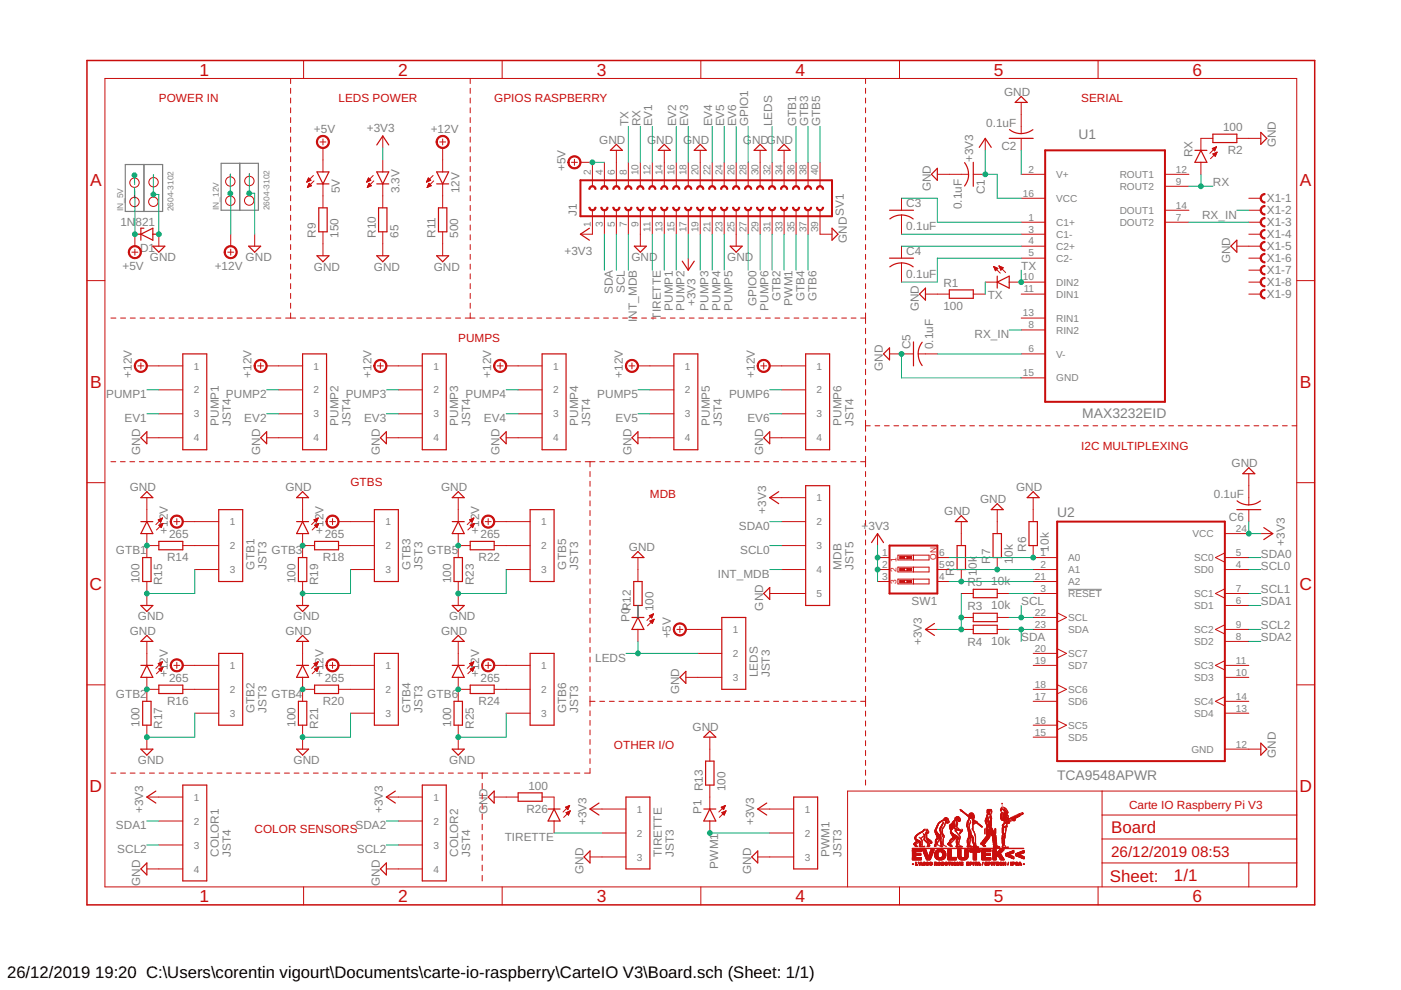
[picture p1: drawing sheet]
<svg xmlns="http://www.w3.org/2000/svg" width="297mm" height="210mm" viewBox="0 0 297 210" stroke-linecap="round" stroke-linejoin="round" font-family="sans-serif">
<defs><g id="words">
<g font-size="3.7" fill="#c90d0c">
<text x="42.3" y="16">1</text>
<text x="84.4" y="16">2</text>
<text x="126.5" y="16">3</text>
<text x="168.6" y="16">4</text>
<text x="210.7" y="16">5</text>
<text x="252.9" y="16">6</text>
<text x="19.1" y="39.4">A</text>
<text x="275.6" y="39.4">A</text>
<text x="19.1" y="82.2">B</text>
<text x="275.6" y="82.2">B</text>
<text x="19" y="125.1">C</text>
<text x="275.5" y="125.1">C</text>
<text x="19" y="167.9">D</text>
<text x="275.5" y="167.9">D</text>
<text x="42.3" y="191.2">1</text>
<text x="84.4" y="191.2">2</text>
<text x="126.5" y="191.2">3</text>
<text x="168.6" y="191.2">4</text>
<text x="210.7" y="191.2">5</text>
<text x="252.9" y="191.2">6</text>
</g>
<g font-size="3.6" fill="#c90d0c">
<text x="235.6" y="176.6">Board</text>
<text x="235.3" y="186.9">Sheet:</text>
<text x="248.9" y="186.8">1/1</text>
</g>
<g font-size="3.5">
<text x="1.5" y="207.4">26/12/2019</text>
<text x="20.2" y="207.4">19:20 C:\Users\corentin vigourt\Documents\carte-io-raspberry\CarteIO V3\Board.sch (Sheet: 1/1)</text>
</g>
<g font-size="3.2" fill="#c90d0c">
<text x="235.6" y="181.7">26/12/2019</text>
<text x="252.6" y="181.7">08:53</text>
</g>
<g font-size="2.9" fill="#808080">
<text x="228.6" y="29.5">U1</text>
<text x="229.5" y="88.6">MAX3232EID</text>
<text x="224.1" y="109.6">U2</text>
<text x="224.1" y="165.4">TCA9548APWR</text>
</g>
<g font-size="2.5" fill="#c90d0c">
<text x="33.7" y="21.7">POWER IN</text>
<text x="71.8" y="21.7">LEDS POWER</text>
<text x="104.8" y="21.7">GPIOS RASPBERRY</text>
<text x="229.2" y="21.7">SERIAL</text>
<text x="97.2" y="72.5">PUMPS</text>
<text x="229.2" y="95.4">I2C MULTIPLEXING</text>
<text x="74.3" y="103">GTBS</text>
<text x="137.8" y="105.5">MDB</text>
<text x="130.2" y="158.8">OTHER I/O</text>
<text x="239.4" y="171.5">Carte IO Raspberry Pi V3</text>
<text x="54" y="176.6">COLOR SENSORS</text>
</g>
<g font-size="2.5" fill="#808080">
<text x="212.9" y="20.3">GND</text>
<text x="66.6" y="28.2">+5V</text>
<text x="77.8" y="28.1">+3V3</text>
<text x="91.3" y="28.2">+12V</text>
<text x="133.2" y="26.8" transform="rotate(-90 133.2 26.8)">TX</text>
<text x="135.8" y="26.8" transform="rotate(-90 135.8 26.8)">RX</text>
<text x="138.3" y="26.8" transform="rotate(-90 138.3 26.8)">EV1</text>
<text x="143.4" y="26.8" transform="rotate(-90 143.4 26.8)">EV2</text>
<text x="145.9" y="26.8" transform="rotate(-90 145.9 26.8)">EV3</text>
<text x="151" y="26.8" transform="rotate(-90 151 26.8)">EV4</text>
<text x="153.5" y="26.8" transform="rotate(-90 153.5 26.8)">EV5</text>
<text x="156.1" y="26.8" transform="rotate(-90 156.1 26.8)">EV6</text>
<text x="158.6" y="26.8" transform="rotate(-90 158.6 26.8)">GPIO1</text>
<text x="163.7" y="26.8" transform="rotate(-90 163.7 26.8)">LEDS</text>
<text x="168.8" y="26.8" transform="rotate(-90 168.8 26.8)">GTB1</text>
<text x="171.3" y="26.8" transform="rotate(-90 171.3 26.8)">GTB3</text>
<text x="173.9" y="26.8" transform="rotate(-90 173.9 26.8)">GTB5</text>
<text x="209.1" y="26.9">0.1uF</text>
<text x="259.3" y="27.8">100</text>
<text x="127" y="30.5">GND</text>
<text x="137.2" y="30.5">GND</text>
<text x="144.8" y="30.5">GND</text>
<text x="157.5" y="30.5">GNDGND</text>
<text x="206.4" y="34.4" transform="rotate(-90 206.4 34.4)">+3V3</text>
<text x="212.3" y="31.7">C2</text>
<text x="252.8" y="33.3" transform="rotate(-90 252.8 33.3)">RX</text>
<text x="260.3" y="32.6">R2</text>
<text x="270.5" y="31.2" transform="rotate(-90 270.5 31.2)">GND</text>
<text x="72" y="41" transform="rotate(-90 72 41)">5V</text>
<text x="84.7" y="41" transform="rotate(-90 84.7 41)">3.3V</text>
<text x="97.4" y="41" transform="rotate(-90 97.4 41)">12V</text>
<text x="119.9" y="36.3" transform="rotate(-90 119.9 36.3)">+5V</text>
<text x="197.3" y="40.6" transform="rotate(-90 197.3 40.6)">GND</text>
<text x="208.8" y="41.2" transform="rotate(-90 208.8 41.2)">C1</text>
<text x="257.2" y="39.5">RX</text>
<text x="122.3" y="45.8" transform="rotate(-90 122.3 45.8)">J1</text>
<text x="178.9" y="45.8" transform="rotate(-90 178.9 45.8)">SV1</text>
<text x="192.1" y="43.9">C3</text>
<text x="204" y="44.4" transform="rotate(-90 204 44.4)">0.1uF</text>
<text x="254.9" y="46.4">RX_IN</text>
<text x="268.6" y="42.8">X1-1</text>
<text x="268.6" y="45.3">X1-2</text>
<text x="268.6" y="47.9">X1-3</text>
<text x="25.5" y="48">1N</text>
<text x="28.7" y="48">821</text>
<text x="29.7" y="53.3">D1</text>
<text x="67" y="50.4" transform="rotate(-90 67 50.4)">R9</text>
<text x="71.8" y="50.4" transform="rotate(-90 71.8 50.4)">150</text>
<text x="79.7" y="50.4" transform="rotate(-90 79.7 50.4)">R10</text>
<text x="84.5" y="50.4" transform="rotate(-90 84.5 50.4)">65</text>
<text x="92.4" y="50.4" transform="rotate(-90 92.4 50.4)">R11</text>
<text x="97.2" y="50.4" transform="rotate(-90 97.2 50.4)">500</text>
<text x="119.7" y="54">+3V3</text>
<text x="179.6" y="51.6" transform="rotate(-90 179.6 51.6)">GND</text>
<text x="192.1" y="48.8">0.1uF</text>
<text x="268.6" y="50.4">X1-4</text>
<text x="268.6" y="53">X1-5</text>
<text x="26" y="57.1">+5V</text>
<text x="31.8" y="55.4">GND</text>
<text x="45.5" y="57.1">+12V</text>
<text x="52.1" y="55.4">GND</text>
<text x="66.6" y="57.4">GND</text>
<text x="79.3" y="57.4">GND</text>
<text x="92" y="57.4">GND</text>
<text x="133.9" y="55.4">GND</text>
<text x="154.2" y="55.4">GND</text>
<text x="192.1" y="58.9">0.1uF</text>
<text x="192.1" y="54.1">C4</text>
<text x="216.5" y="57.3">TX</text>
<text x="260.8" y="55.8" transform="rotate(-90 260.8 55.8)">GND</text>
<text x="268.6" y="55.5">X1-6</text>
<text x="268.6" y="58">X1-7</text>
<text x="129.9" y="62.4" transform="rotate(-90 129.9 62.4)">SDA</text>
<text x="132.5" y="62.1" transform="rotate(-90 132.5 62.1)">SCL</text>
<text x="142.6" y="65.9" transform="rotate(-90 142.6 65.9)">PUMP1</text>
<text x="145.2" y="65.9" transform="rotate(-90 145.2 65.9)">PUMP2</text>
<text x="147.4" y="64.9" transform="rotate(-90 147.4 64.9)">+3V3</text>
<text x="150.2" y="65.9" transform="rotate(-90 150.2 65.9)">PUMP3</text>
<text x="152.8" y="65.9" transform="rotate(-90 152.8 65.9)">PUMP4</text>
<text x="155.3" y="65.9" transform="rotate(-90 155.3 65.9)">PUMP5</text>
<text x="160.4" y="64.9" transform="rotate(-90 160.4 64.9)">GPIO0</text>
<text x="162.9" y="65.9" transform="rotate(-90 162.9 65.9)">PUMP6</text>
<text x="165.5" y="63.8" transform="rotate(-90 165.5 63.8)">GTB2</text>
<text x="168" y="64.8" transform="rotate(-90 168 64.8)">PWM1</text>
<text x="170.6" y="63.8" transform="rotate(-90 170.6 63.8)">GTB4</text>
<text x="173.1" y="63.8" transform="rotate(-90 173.1 63.8)">GTB6</text>
<text x="194.8" y="66" transform="rotate(-90 194.8 66)">GND</text>
<text x="200" y="65.6">100</text>
<text x="200" y="60.8">R1</text>
<text x="209.4" y="63.4">TX</text>
<text x="268.6" y="60.6">X1-8</text>
<text x="268.6" y="63.1">X1-9</text>
<text x="135" y="68.3" transform="rotate(-90 135 68.3)">INT_MDB</text>
<text x="140.1" y="67.7" transform="rotate(-90 140.1 67.7)">TIRETTE</text>
<text x="206.6" y="71.7">RX_IN</text>
<text x="193" y="74" transform="rotate(-90 193 74)">C5</text>
<text x="197.9" y="74" transform="rotate(-90 197.9 74)">0.1uF</text>
<text x="28" y="80.1" transform="rotate(-90 28 80.1)">+12V</text>
<text x="53.4" y="80.1" transform="rotate(-90 53.4 80.1)">+12V</text>
<text x="78.8" y="80.1" transform="rotate(-90 78.8 80.1)">+12V</text>
<text x="104.1" y="80.1" transform="rotate(-90 104.1 80.1)">+12V</text>
<text x="132.1" y="80.1" transform="rotate(-90 132.1 80.1)">+12V</text>
<text x="160" y="80.1" transform="rotate(-90 160 80.1)">+12V</text>
<text x="187.2" y="78.7" transform="rotate(-90 187.2 78.7)">GND</text>
<text x="22.5" y="84.4">PUMP1</text>
<text x="26.4" y="89.5">EV1</text>
<text x="47.9" y="84.4">PUMP2</text>
<text x="51.8" y="89.5">EV2</text>
<text x="73.3" y="84.4">PUMP3</text>
<text x="77.2" y="89.5">EV3</text>
<text x="98.7" y="84.4">PUMP4</text>
<text x="102.6" y="89.5">EV4</text>
<text x="126.6" y="84.4">PUMP5</text>
<text x="130.5" y="89.5">EV5</text>
<text x="154.6" y="84.4">PUMP6</text>
<text x="158.4" y="89.5">EV6</text>
<text x="46.4" y="90.3" transform="rotate(-90 46.4 90.3)">PUMP1</text>
<text x="48.9" y="90.3" transform="rotate(-90 48.9 90.3)">JST4</text>
<text x="71.8" y="90.3" transform="rotate(-90 71.8 90.3)">PUMP2</text>
<text x="74.3" y="90.3" transform="rotate(-90 74.3 90.3)">JST4</text>
<text x="97.2" y="90.3" transform="rotate(-90 97.2 90.3)">PUMP3</text>
<text x="99.7" y="90.3" transform="rotate(-90 99.7 90.3)">JST4</text>
<text x="122.6" y="90.3" transform="rotate(-90 122.6 90.3)">PUMP4</text>
<text x="125.1" y="90.3" transform="rotate(-90 125.1 90.3)">JST4</text>
<text x="150.5" y="90.3" transform="rotate(-90 150.5 90.3)">PUMP5</text>
<text x="153" y="90.3" transform="rotate(-90 153 90.3)">JST4</text>
<text x="178.4" y="90.3" transform="rotate(-90 178.4 90.3)">PUMP6</text>
<text x="181" y="90.3" transform="rotate(-90 181 90.3)">JST4</text>
<text x="29.7" y="96.5" transform="rotate(-90 29.7 96.5)">GND</text>
<text x="55.1" y="96.5" transform="rotate(-90 55.1 96.5)">GND</text>
<text x="80.5" y="96.5" transform="rotate(-90 80.5 96.5)">GND</text>
<text x="105.9" y="96.5" transform="rotate(-90 105.9 96.5)">GND</text>
<text x="133.9" y="96.5" transform="rotate(-90 133.9 96.5)">GND</text>
<text x="161.8" y="96.5" transform="rotate(-90 161.8 96.5)">GND</text>
<text x="261.1" y="99">GND</text>
<text x="27.5" y="104.1">GND</text>
<text x="60.5" y="104.1">GND</text>
<text x="93.5" y="104.1">GND</text>
<text x="207.8" y="106.7">GND</text>
<text x="215.4" y="104.1">GND</text>
<text x="257.3" y="105.6">0.1uF</text>
<text x="35.6" y="113.1" transform="rotate(-90 35.6 113.1)">+12V</text>
<text x="68.6" y="113.1" transform="rotate(-90 68.6 113.1)">+12V</text>
<text x="101.6" y="113.1" transform="rotate(-90 101.6 113.1)">+12V</text>
<text x="156.7" y="112.4">SDA0</text>
<text x="162.4" y="108.9" transform="rotate(-90 162.4 108.9)">+3V3</text>
<text x="182.7" y="112.4">+3V3</text>
<text x="200.2" y="109.2">GND</text>
<text x="260.6" y="110.5">C6</text>
<text x="24.6" y="117.5">GTB1</text>
<text x="35.4" y="119">R14</text>
<text x="35.8" y="114.2">265</text>
<text x="57.6" y="117.5">GTB3</text>
<text x="68.4" y="119">R18</text>
<text x="68.8" y="114.2">265</text>
<text x="90.6" y="117.5">GTB5</text>
<text x="101.5" y="119">R22</text>
<text x="101.9" y="114.2">265</text>
<text x="133.4" y="116.8">GND</text>
<text x="156.9" y="117.5">SCL0</text>
<text x="209.9" y="119.5" transform="rotate(-90 209.9 119.5)">R</text>
<text x="209.9" y="117.7" transform="rotate(-90 209.9 117.7)">7</text>
<text x="214.7" y="119.5" transform="rotate(-90 214.7 119.5)">1</text>
<text x="214.7" y="118.1" transform="rotate(-90 214.7 118.1)">0k</text>
<text x="217.6" y="116.9" transform="rotate(-90 217.6 116.9)">R6</text>
<text x="222.4" y="116.9" transform="rotate(-90 222.4 116.9)">10k</text>
<text x="267.3" y="118.2">SDA0</text>
<text x="272.4" y="115.7" transform="rotate(-90 272.4 115.7)">+3V3</text>
<text x="29.6" y="123.7" transform="rotate(-90 29.6 123.7)">100</text>
<text x="34.4" y="124.1" transform="rotate(-90 34.4 124.1)">R15</text>
<text x="54" y="120.8" transform="rotate(-90 54 120.8)">GTB1</text>
<text x="56.5" y="120.8" transform="rotate(-90 56.5 120.8)">JST3</text>
<text x="62.6" y="123.7" transform="rotate(-90 62.6 123.7)">100</text>
<text x="67.4" y="124.1" transform="rotate(-90 67.4 124.1)">R19</text>
<text x="87" y="120.8" transform="rotate(-90 87 120.8)">GTB3</text>
<text x="89.5" y="120.8" transform="rotate(-90 89.5 120.8)">JST3</text>
<text x="95.6" y="123.7" transform="rotate(-90 95.6 123.7)">100</text>
<text x="100.4" y="124.1" transform="rotate(-90 100.4 124.1)">R23</text>
<text x="120" y="120.8" transform="rotate(-90 120 120.8)">GTB5</text>
<text x="122.6" y="120.8" transform="rotate(-90 122.6 120.8)">JST3</text>
<text x="152.2" y="122.5">INT_MDB</text>
<text x="178.4" y="120.8" transform="rotate(-90 178.4 120.8)">MDB</text>
<text x="181" y="120.8" transform="rotate(-90 181 120.8)">JST5</text>
<text x="202.3" y="122" transform="rotate(-90 202.3 122)">R</text>
<text x="202.3" y="120.2" transform="rotate(-90 202.3 120.2)">8</text>
<text x="205.1" y="124.3">R5</text>
<text x="207.1" y="122" transform="rotate(-90 207.1 122)">1</text>
<text x="207.1" y="120.6" transform="rotate(-90 207.1 120.6)">0k</text>
<text x="210.2" y="124.1">10k</text>
<text x="267.3" y="125.8">SCL1</text>
<text x="267.3" y="120.8">SCL0</text>
<text x="29.2" y="131.5">GND</text>
<text x="62.2" y="131.5">GND</text>
<text x="95.3" y="131.5">GND</text>
<text x="133.5" y="131.9" transform="rotate(-90 133.5 131.9)">P0R12</text>
<text x="138.6" y="129.6" transform="rotate(-90 138.6 129.6)">100</text>
<text x="161.8" y="129.5" transform="rotate(-90 161.8 129.5)">GND</text>
<text x="193.3" y="128.2">SW1</text>
<text x="205.1" y="129.4">R3</text>
<text x="210.2" y="129.1">10k</text>
<text x="216.5" y="128.4">SCL</text>
<text x="267.3" y="128.4">SDA1</text>
<text x="27.5" y="134.6">GND</text>
<text x="60.5" y="134.6">GND</text>
<text x="93.5" y="134.6">GND</text>
<text x="142.2" y="135.4" transform="rotate(-90 142.2 135.4)">+5V</text>
<text x="195.4" y="136.8" transform="rotate(-90 195.4 136.8)">+3V3</text>
<text x="205.1" y="137">R4</text>
<text x="210.2" y="136.8">10k</text>
<text x="216.5" y="136">SDA</text>
<text x="267.3" y="133.4">SCL2</text>
<text x="267.3" y="136">SDA2</text>
<text x="35.6" y="143.6" transform="rotate(-90 35.6 143.6)">+12V</text>
<text x="68.6" y="143.6" transform="rotate(-90 68.6 143.6)">+12V</text>
<text x="101.6" y="143.6" transform="rotate(-90 101.6 143.6)">+12V</text>
<text x="126.2" y="140.3">LEDS</text>
<text x="160.7" y="143.6" transform="rotate(-90 160.7 143.6)">LEDS</text>
<text x="163.2" y="143.6" transform="rotate(-90 163.2 143.6)">JST3</text>
<text x="24.6" y="147.9">GTB2</text>
<text x="35.4" y="149.4">R16</text>
<text x="35.8" y="144.6">265</text>
<text x="57.6" y="147.9">GTB4</text>
<text x="68.4" y="149.4">R20</text>
<text x="68.8" y="144.6">265</text>
<text x="90.6" y="147.9">GTB6</text>
<text x="101.5" y="149.4">R24</text>
<text x="101.9" y="144.6">265</text>
<text x="144" y="147.2" transform="rotate(-90 144 147.2)">GND</text>
<text x="29.6" y="154.1" transform="rotate(-90 29.6 154.1)">100</text>
<text x="34.4" y="154.5" transform="rotate(-90 34.4 154.5)">R17</text>
<text x="54" y="151.2" transform="rotate(-90 54 151.2)">GTB2</text>
<text x="56.5" y="151.2" transform="rotate(-90 56.5 151.2)">JST3</text>
<text x="62.6" y="154.1" transform="rotate(-90 62.6 154.1)">100</text>
<text x="67.4" y="154.5" transform="rotate(-90 67.4 154.5)">R21</text>
<text x="87" y="151.2" transform="rotate(-90 87 151.2)">GTB4</text>
<text x="89.5" y="151.2" transform="rotate(-90 89.5 151.2)">JST3</text>
<text x="95.6" y="154.1" transform="rotate(-90 95.6 154.1)">100</text>
<text x="100.4" y="154.5" transform="rotate(-90 100.4 154.5)">R25</text>
<text x="120" y="151.2" transform="rotate(-90 120 151.2)">GTB6</text>
<text x="122.6" y="151.2" transform="rotate(-90 122.6 151.2)">JST3</text>
<text x="146.9" y="154.9">GND</text>
<text x="270.5" y="160.7" transform="rotate(-90 270.5 160.7)">GND</text>
<text x="29.2" y="162">GND</text>
<text x="62.2" y="162">GND</text>
<text x="95.3" y="162">GND</text>
<text x="112" y="167.5">100</text>
<text x="149" y="167.7" transform="rotate(-90 149 167.7)">R13</text>
<text x="153.8" y="167.7" transform="rotate(-90 153.8 167.7)">100</text>
<text x="30.4" y="172.4" transform="rotate(-90 30.4 172.4)">+3V3</text>
<text x="81.2" y="172.4" transform="rotate(-90 81.2 172.4)">+3V3</text>
<text x="103.4" y="172.6" transform="rotate(-90 103.4 172.6)">GND</text>
<text x="111.6" y="172.3">R26</text>
<text x="148.7" y="172.6" transform="rotate(-90 148.7 172.6)">P1</text>
<text x="24.6" y="175.9">SDA1</text>
<text x="75.4" y="175.9">SDA2</text>
<text x="107" y="178.4">TIRETTE</text>
<text x="124.3" y="174.9" transform="rotate(-90 124.3 174.9)">+3V3</text>
<text x="159.9" y="174.9" transform="rotate(-90 159.9 174.9)">+3V3</text>
<text x="24.9" y="180.9">SCL2</text>
<text x="46.4" y="181.7" transform="rotate(-90 46.4 181.7)">COLOR1</text>
<text x="48.9" y="181.7" transform="rotate(-90 48.9 181.7)">JST4</text>
<text x="75.7" y="180.9">SCL2</text>
<text x="97.2" y="181.7" transform="rotate(-90 97.2 181.7)">COLOR2</text>
<text x="99.7" y="181.7" transform="rotate(-90 99.7 181.7)">JST4</text>
<text x="123.7" y="185.3" transform="rotate(-90 123.7 185.3)">GND</text>
<text x="140.3" y="181.7" transform="rotate(-90 140.3 181.7)">TIRETTE</text>
<text x="142.9" y="181.7" transform="rotate(-90 142.9 181.7)">JST3</text>
<text x="152.3" y="184.2" transform="rotate(-90 152.3 184.2)">PWM1</text>
<text x="159.3" y="185.3" transform="rotate(-90 159.3 185.3)">GND</text>
<text x="175.9" y="181.7" transform="rotate(-90 175.9 181.7)">PWM1</text>
<text x="178.4" y="181.7" transform="rotate(-90 178.4 181.7)">JST3</text>
<text x="29.7" y="187.9" transform="rotate(-90 29.7 187.9)">GND</text>
<text x="80.5" y="187.9" transform="rotate(-90 80.5 187.9)">GND</text>
</g>
<g font-size="2.1" fill="#808080">
<text x="125.2" y="37.2" transform="rotate(-90 125.2 37.2)">2</text>
<text x="127.8" y="37.2" transform="rotate(-90 127.8 37.2)">4</text>
<text x="130.3" y="37.2" transform="rotate(-90 130.3 37.2)">6</text>
<text x="132.9" y="37.2" transform="rotate(-90 132.9 37.2)">8</text>
<text x="135.4" y="37.2" transform="rotate(-90 135.4 37.2)">10</text>
<text x="137.9" y="37.2" transform="rotate(-90 137.9 37.2)">12</text>
<text x="140.5" y="37.2" transform="rotate(-90 140.5 37.2)">14</text>
<text x="143" y="37.2" transform="rotate(-90 143 37.2)">16</text>
<text x="145.6" y="37.2" transform="rotate(-90 145.6 37.2)">18</text>
<text x="148.1" y="37.2" transform="rotate(-90 148.1 37.2)">20</text>
<text x="150.6" y="37.2" transform="rotate(-90 150.6 37.2)">22</text>
<text x="153.2" y="37.2" transform="rotate(-90 153.2 37.2)">24</text>
<text x="155.7" y="37.2" transform="rotate(-90 155.7 37.2)">26</text>
<text x="158.3" y="37.2" transform="rotate(-90 158.3 37.2)">28</text>
<text x="160.8" y="37.2" transform="rotate(-90 160.8 37.2)">30</text>
<text x="163.3" y="37.2" transform="rotate(-90 163.3 37.2)">32</text>
<text x="165.9" y="37.2" transform="rotate(-90 165.9 37.2)">34</text>
<text x="168.4" y="37.2" transform="rotate(-90 168.4 37.2)">36</text>
<text x="171" y="37.2" transform="rotate(-90 171 37.2)">38</text>
<text x="173.5" y="37.2" transform="rotate(-90 173.5 37.2)">40</text>
<text x="216.9" y="41.7">16</text>
<text x="218.1" y="36.6">2</text>
<text x="223.9" y="37.7">V+</text>
<text x="237.4" y="37.7">ROUT1</text>
<text x="237.4" y="40.3">ROUT2</text>
<text x="249.3" y="36.6">12</text>
<text x="249.3" y="39.1">9</text>
<text x="218.1" y="46.8">1</text>
<text x="223.9" y="42.8">VCC</text>
<text x="223.9" y="47.9">C1+</text>
<text x="237.4" y="45.3">DOUT1</text>
<text x="237.4" y="47.9">DOUT2</text>
<text x="249.3" y="44.2">14</text>
<text x="249.3" y="46.8">7</text>
<text x="125.2" y="48.1" transform="rotate(-90 125.2 48.1)">1</text>
<text x="127.8" y="48.1" transform="rotate(-90 127.8 48.1)">3</text>
<text x="130.3" y="48.1" transform="rotate(-90 130.3 48.1)">5</text>
<text x="132.9" y="48.1" transform="rotate(-90 132.9 48.1)">7</text>
<text x="135.4" y="48.1" transform="rotate(-90 135.4 48.1)">9</text>
<text x="137.9" y="49.1" transform="rotate(-90 137.9 49.1)">11</text>
<text x="140.5" y="49.3" transform="rotate(-90 140.5 49.3)">13</text>
<text x="143" y="49.3" transform="rotate(-90 143 49.3)">15</text>
<text x="145.6" y="49.3" transform="rotate(-90 145.6 49.3)">17</text>
<text x="148.1" y="49.3" transform="rotate(-90 148.1 49.3)">19</text>
<text x="150.6" y="49.3" transform="rotate(-90 150.6 49.3)">21</text>
<text x="153.2" y="49.3" transform="rotate(-90 153.2 49.3)">23</text>
<text x="155.7" y="49.3" transform="rotate(-90 155.7 49.3)">25</text>
<text x="158.3" y="49.3" transform="rotate(-90 158.3 49.3)">27</text>
<text x="160.8" y="49.3" transform="rotate(-90 160.8 49.3)">29</text>
<text x="163.3" y="49.3" transform="rotate(-90 163.3 49.3)">31</text>
<text x="165.9" y="49.3" transform="rotate(-90 165.9 49.3)">33</text>
<text x="168.4" y="49.3" transform="rotate(-90 168.4 49.3)">35</text>
<text x="171" y="49.3" transform="rotate(-90 171 49.3)">37</text>
<text x="173.5" y="49.3" transform="rotate(-90 173.5 49.3)">39</text>
<text x="218.1" y="49.3">3</text>
<text x="218.1" y="51.8">4</text>
<text x="223.9" y="50.4">C1-</text>
<text x="223.9" y="53">C2+</text>
<text x="216.9" y="59.5">10</text>
<text x="218.1" y="54.4">5</text>
<text x="223.9" y="55.5">C2-</text>
<text x="217" y="62">11</text>
<text x="223.9" y="60.6">DIN2</text>
<text x="223.9" y="63.1">DIN1</text>
<text x="216.9" y="67.1">13</text>
<text x="218.1" y="69.6">8</text>
<text x="223.9" y="68.2">RIN1</text>
<text x="223.9" y="70.7">RIN2</text>
<text x="218.1" y="74.7">6</text>
<text x="223.9" y="75.8">V-</text>
<text x="41.1" y="78.3">1</text>
<text x="41.1" y="83.4">2</text>
<text x="66.5" y="78.3">1</text>
<text x="66.5" y="83.4">2</text>
<text x="91.9" y="78.3">1</text>
<text x="91.9" y="83.4">2</text>
<text x="117.3" y="78.3">1</text>
<text x="117.3" y="83.4">2</text>
<text x="145.2" y="78.3">1</text>
<text x="145.2" y="83.4">2</text>
<text x="173.1" y="78.3">1</text>
<text x="173.1" y="83.4">2</text>
<text x="216.9" y="79.8">15</text>
<text x="223.9" y="80.9">GND</text>
<text x="41.1" y="88.5">3</text>
<text x="66.5" y="88.5">3</text>
<text x="91.9" y="88.5">3</text>
<text x="117.3" y="88.5">3</text>
<text x="145.2" y="88.5">3</text>
<text x="173.1" y="88.5">3</text>
<text x="41.1" y="93.6">4</text>
<text x="66.5" y="93.6">4</text>
<text x="91.9" y="93.6">4</text>
<text x="117.3" y="93.6">4</text>
<text x="145.2" y="93.6">4</text>
<text x="173.1" y="93.6">4</text>
<text x="173.1" y="106.3">1</text>
<text x="48.7" y="111.4">1</text>
<text x="81.7" y="111.4">1</text>
<text x="114.7" y="111.4">1</text>
<text x="173.1" y="111.4">2</text>
<text x="252.8" y="113.9">VCC</text>
<text x="262" y="112.8">24</text>
<text x="48.7" y="116.4">2</text>
<text x="81.7" y="116.4">2</text>
<text x="114.7" y="116.4">2</text>
<text x="173.1" y="116.4">3</text>
<text x="187" y="117.9">1</text>
<text x="199.1" y="117.9">6</text>
<text x="220.6" y="117.9">1</text>
<text x="226.5" y="119">A0</text>
<text x="253.2" y="119">SC0</text>
<text x="262" y="117.9">5</text>
<text x="48.7" y="121.5">3</text>
<text x="81.7" y="121.5">3</text>
<text x="114.7" y="121.5">3</text>
<text x="173.1" y="121.5">4</text>
<text x="187" y="120.4">2</text>
<text x="187" y="122.9">3</text>
<text x="199.1" y="122.9">4</text>
<text x="199.1" y="120.4">5</text>
<text x="219.4" y="122.9">21</text>
<text x="220.6" y="120.4">2</text>
<text x="220.6" y="125.5">3</text>
<text x="226.5" y="121.5">A1</text>
<text x="226.5" y="124.1">A2</text>
<text x="253.2" y="121.5">SD0</text>
<text x="262" y="125.5">7</text>
<text x="262" y="120.4">4</text>
<text x="173.1" y="126.6">5</text>
<text x="219.4" y="130.6">22</text>
<text x="226.5" y="126.6">RESET</text>
<text x="226.5" y="131.7">SCL</text>
<text x="253.2" y="126.6">SC1</text>
<text x="253.2" y="129.1">SD1</text>
<text x="262" y="128">6</text>
<text x="155.4" y="134.2">1</text>
<text x="219.4" y="133.1">23</text>
<text x="226.5" y="134.2">SDA</text>
<text x="253.2" y="134.2">SC2</text>
<text x="253.2" y="136.8">SD2</text>
<text x="262" y="133.1">9</text>
<text x="262" y="135.6">8</text>
<text x="48.7" y="141.8">1</text>
<text x="81.7" y="141.8">1</text>
<text x="114.7" y="141.8">1</text>
<text x="155.4" y="139.3">2</text>
<text x="219.4" y="138.2">20</text>
<text x="219.4" y="140.7">19</text>
<text x="226.5" y="139.3">SC7</text>
<text x="226.5" y="141.8">SD7</text>
<text x="253.2" y="141.8">SC3</text>
<text x="262" y="140.7">11</text>
<text x="262" y="143.3">10</text>
<text x="48.7" y="146.9">2</text>
<text x="81.7" y="146.9">2</text>
<text x="114.7" y="146.9">2</text>
<text x="155.4" y="144.4">3</text>
<text x="219.4" y="145.8">18</text>
<text x="219.4" y="148.3">17</text>
<text x="226.5" y="146.9">SC6</text>
<text x="226.5" y="149.4">SD6</text>
<text x="253.2" y="149.4">SC4</text>
<text x="253.2" y="144.4">SD3</text>
<text x="262" y="148.3">14</text>
<text x="48.7" y="152">3</text>
<text x="81.7" y="152">3</text>
<text x="114.7" y="152">3</text>
<text x="219.4" y="153.4">16</text>
<text x="219.4" y="155.9">15</text>
<text x="226.5" y="154.5">SC5</text>
<text x="253.2" y="152">SD4</text>
<text x="262" y="150.9">13</text>
<text x="226.5" y="157.1">SD5</text>
<text x="252.6" y="159.6">GND</text>
<text x="262" y="158.5">12</text>
<text x="41.1" y="169.8">1</text>
<text x="91.9" y="169.8">1</text>
<text x="135.1" y="172.3">1</text>
<text x="170.6" y="172.3">1</text>
<text x="41.1" y="174.8">2</text>
<text x="41.1" y="179.9">3</text>
<text x="91.9" y="174.8">2</text>
<text x="91.9" y="179.9">3</text>
<text x="135.1" y="177.4">2</text>
<text x="170.6" y="177.4">2</text>
<text x="41.1" y="185">4</text>
<text x="91.9" y="185">4</text>
<text x="135.1" y="182.5">3</text>
<text x="170.6" y="182.5">3</text>
</g>
<g font-size="1.8" fill="#808080">
<text x="26.1" y="44.8" transform="rotate(-90 26.1 44.8)">IN_5V</text>
<text x="36.8" y="44.8" transform="rotate(-90 36.8 44.8)">2604-3102</text>
<text x="46.4" y="44.6" transform="rotate(-90 46.4 44.6)">IN_12V</text>
<text x="57.1" y="44.6" transform="rotate(-90 57.1 44.6)">2604-3102</text>
</g>
<g font-size="1.8" fill="#c90d0c">
<text x="190.1" y="119.1" transform="rotate(-90 190.1 119.1)">1</text>
<text x="198.5" y="118.7" transform="rotate(-90 198.5 118.7)">ON</text>
<text x="190.1" y="123.9" transform="rotate(-90 190.1 123.9)">3</text>
<text x="190.1" y="121.4" transform="rotate(-90 190.1 121.4)">2</text>
</g>
</g></defs>
<path d="M26.6 34.9h7.9v9.9h-7.9zM30.5 34.9v9.9M46.9 34.6h7.9v10h-7.9zM50.8 34.6v10" fill="none" stroke="#808080" stroke-width=".25"/>
<path d="M226.5 124.9h7.1" fill="none" stroke="#808080" stroke-width=".21"/>
<g fill="none" stroke="#c90d0c" stroke-width=".21">
<path d="M22.2 16.6h252.7v171.4h-252.7zM61.6 16.6v1.1M61.6 18.7v1.1M64.4 12.8v3.8M99.7 16.6v1.1M99.7 18.7v1.1M106.5 12.8v3.8M148.6 12.8v3.8M183.5 16.6v1.1M183.5 18.7v1.1M190.7 12.8v3.8M232.8 12.8v3.8"/>
<path d="M28.5 37.2v.5M32.6 37.1v.5M48.8 36.9v.6M52.9 36.8v.6M61.6 20.8v1M61.6 22.9v1M61.6 24.9v1.1M61.6 27v1.1M61.6 29.1v1M61.6 31.1v1.1M61.6 33.2v1.1M61.6 35.3v1.1"/>
<path d="M61.6 37.4v1M61.6 39.4v1.1M65.1 38.6h.1M65.1 38.4h.3M65.2 38.3h.5M65.2 38.2h.7M65.2 39.6h.2M65.3 38.1h.5M65.3 39.5h.4M65.3 38h.4M65.3 39.4h.7M65.4 37.8h.1"/>
<path d="M65.4 39.3h.6M65.4 37.7l.5 .5-.9 .4zM65.4 39.2h.4M65.5 39h.2M65.5 38.9h.1M65.6 38.9l.5 .5-.9 .4zM66.4 37.2l-1.4 1.4M66.6 38.4l-1.4 1.4M67.8 30.1h1.3M68.5 29.5v1.2M68.5 31.4v5M68.5 39v5.1"/>
<path d="M77.8 38.6h.1M77.8 38.4h.3M77.9 38.3h.5M77.9 38.2h.7M77.9 39.6h.2M78 38.1h.5M78 39.5h.4M78 38h.4M78 39.4h.7M78.1 37.8h.1M78.1 39.3h.6M78.1 39.2h.4"/>
<path d="M78.1 37.7l.5 .5-.9 .4zM78.2 39h.2M78.2 38.9h.1M78.3 38.9l.4 .5-.8 .4zM79.1 37.2l-1.4 1.4M79.2 38.4l-1.3 1.4M81.2 28.8v2.6M81.2 33.9v2.5M81.2 39v5.1M90.4 38.6h.2M90.5 38.4h.3M90.6 38.3h.5"/>
<path d="M90.6 38.2h.7M90.6 39.6h.2M90.7 38.1h.5M90.7 39.5h.4M90.7 39.4h.7M90.7 38h.4M90.8 37.8h.1M90.8 39.3h.6M90.8 39.2h.4M90.8 37.7l.5 .5-.9 .4zM90.9 39h.2M90.9 38.9h.1"/>
<path d="M90.9 38.9l.5 .5-.8 .4zM91.8 37.2l-1.4 1.4M91.9 38.4l-1.3 1.4M93.2 30.1h1.3M93.9 29.5v1.2M93.9 31.4v5M93.9 39v5.1M99.7 20.8v1M99.7 22.9v1M99.7 24.9v1.1M99.7 27v1.1M99.7 29.1v1"/>
<path d="M99.7 31.1v1.1M99.7 33.2v1.1M99.7 35.3v1.1M99.7 37.4v1M99.7 39.4v1.1M121.2 34.4h1.2M121.8 33.8v1.3M123.1 34.4h2.5v5.1M128.1 34.4v5.1M130.7 31.9v7.6M133.2 34.4v5.1M135.8 34.4v5.1"/>
<path d="M138.3 34.4v5.1M140.8 31.9v7.6M143.4 34.4v5.1M145.9 34.4v5.1M148.5 31.9v7.6M151 34.4v5.1M153.5 34.4v5.1M156.1 34.4v5.1M158.6 34.4v5.1M161.2 31.9v7.6M163.7 34.4v5.1M166.2 31.9v7.6"/>
<path d="M168.8 34.4v5.1M171.3 34.4v5.1M173.9 34.4v5.1M183.5 20.8v1M183.5 22.9v1M183.5 24.9v1.1M183.5 27v1.1M183.5 29.1v1M183.5 31.1v1.1M183.5 33.2v1.1M183.5 35.3v1.1M183.5 37.4v1"/>
<path d="M183.5 39.4v1.1M198.7 37h6.6M206.4 37h2.5M208.9 29.3v2.6M216.5 37h5.1M216.5 21.7v6.6M216.5 29.3v2.6M247 37h5.1M247 39.5h5.1M254.6 34.4v2.6M257 31.5l.9-.4-.4 .9zM257.1 31.6h.6"/>
<path d="M257.2 29.3h-2.6v2.6M257.2 32.6l.5 .5M257.2 32.6h.7M257.2 31.4h.6M257.2 31.7h.5M257.3 32.8h.5M257.3 31.8h.3M257.4 32.9h.4M257.4 32.5h.5M257.4 31.3h.4M257.5 31.9h.1M257.5 33h.2"/>
<path d="M257.6 33.1h.1M257.7 32.4h.3M257.7 31.2h.2M257.9 31.1l-1.4 1.4M258 32.3h.1M258 32.3l-1.4 1.4M258 32.3l-.3 .8M258 32.3l-.8 .3M262.2 29.3h5.1M18.4 59.5h3.8M28 53.5h1.2M28.5 41.3v.5"/>
<path d="M28.6 49.7v2.5M28.6 52.8v1.3M32.5 41.2v.6M33.7 49.7v2.5M48.3 53.5h1.3M48.8 41v.6M48.9 49.7v2.5M48.9 52.8v1.3M52.8 41v.5M54 49.7v2.5M61.6 41.5v1.1M61.6 43.6v1"/>
<path d="M61.6 45.6v1.1M61.6 47.7v1.1M61.6 49.8v1.1M61.6 51.9v1M61.6 53.9v1.1M61.6 56v1.1M61.6 58.1v1M68.5 49.1v5.1M81.2 49.1v5.1M93.9 49.1v5.1M99.7 41.5v1.1M99.7 43.6v1"/>
<path d="M99.7 45.6v1.1M99.7 47.7v1.1M99.7 49.8v1.1M99.7 51.9v1M99.7 53.9v1.1M99.7 56v1.1M99.7 58.1v1M125.6 44.6v5.1h-2.5M128.1 44.6v5.1M130.7 44.6v5.1M133.2 44.6v5.1M135.8 44.6v7.6"/>
<path d="M138.3 44.6v5.1M140.8 44.6v5.1M143.4 44.6v5.1M145.9 44.6v5.1M145.9 54.7v2.6M148.5 44.6v5.1M151 44.6v5.1M153.5 44.6v5.1M156.1 44.6v7.6M158.6 44.6v5.1M161.2 44.6v5.1M163.7 44.6v5.1"/>
<path d="M166.2 44.6v5.1M168.8 44.6v5.1M171.3 44.6v5.1M173.9 44.6v5.1h2.5M183.5 41.5v1.1M183.5 43.6v1M183.5 45.6v1.1M183.5 47.7v1.1M183.5 49.8v1.1M183.5 51.9v1M183.5 53.9v1.1M183.5 56v1.1"/>
<path d="M183.5 58.1v1M191.1 42v2.6M191.1 45.6v4.1M191.1 52.2v2.5M191.1 55.8v4M208.9 59.8h2.5M210.7 56.5l1.4 1.4M210.7 56.5l.9 .4M210.7 56.5l.4 .9 .5-.5M210.7 56.5h.1M210.7 56.6h.3M210.8 56.8h.5"/>
<path d="M210.8 56.9h.8M210.9 57h.6M210.9 57.1h.4M211 57.3h.2M211.1 57.4h.1M211.8 56.4l1.4 1.4M211.8 56.4l.9 .4M211.8 56.4l.4 .9 .5-.5M211.8 56.4h.1M211.9 56.5h.3M211.9 56.6h.5M212 56.8h.7"/>
<path d="M212 56.9h.6M212.1 57h.4M212.2 57.1h.1M212.2 57.3h.1M214 59.8h7.6M216.5 49.7h5.1M216.5 42h5.1M216.5 47.1h5.1M216.5 52.2h5.1M216.5 54.7h5.1M247 44.6h5.1M247 47.1h5.1"/>
<path d="M262.2 52.2h5.1M264.8 49.7h2.5M264.8 42h2.5M264.8 44.6h2.5M264.8 47.1h2.5M264.8 54.7h2.5M264.8 57.3h2.5M264.8 59.8h2.5M274.9 59.5h3.8M23.5 67.4h1.1M25.6 67.4h1M27.6 67.4h1.1"/>
<path d="M29.2 77.6h1.3M29.7 67.4h1.1M29.9 76.9v1.3M31.1 77.6h7.7M31.7 67.4h1.1M33.8 67.4h1.1M35.9 67.4h1M37.9 67.4h1.1M40 67.4h1M42 67.4h1.1M44.1 67.4h1M46.1 67.4h1.1"/>
<path d="M48.2 67.4h1.1M50.3 67.4h1M52.3 67.4h1.1M54.4 67.4h1M54.6 77.6h1.3M55.3 76.9v1.3M56.4 67.4h1.1M56.5 77.6h7.7M58.5 67.4h1M60.6 67.4h2.1M61.6 60.1v1.1M61.6 62.2v1.1"/>
<path d="M61.6 64.3v1.1M61.6 66.4v1M63.7 67.4h1M65.7 67.4h1.1M67.8 67.4h1M69.8 67.4h1.1M71.9 67.4h1.1M74 67.4h1M76 67.4h1.1M78.1 67.4h1M80 77.6h1.3M80.1 67.4h1.1"/>
<path d="M80.6 76.9v1.3M81.9 77.6h7.6M82.2 67.4h1M84.2 67.4h1.1M86.3 67.4h1.1M88.3 67.4h1.1M90.4 67.4h1.1M92.5 67.4h1M94.5 67.4h1.1M96.6 67.4h1M98.6 67.4h2.1M99.7 60.1v1.1"/>
<path d="M99.7 62.2v1.1M99.7 64.3v1.1M99.7 66.4v1M101.7 67.4h1M103.7 67.4h1.1M105.4 77.6h1.3M105.8 67.4h1M106 76.9v1.3M107.3 77.6h7.6M107.8 67.4h1M109.8 67.4h1M111.8 67.4h1"/>
<path d="M113.8 67.4h1.1M115.8 67.4h1.1M117.9 67.4h1M119.9 67.4h1M121.9 67.4h1M123.9 67.4h1M125.9 67.4h1.1M128 67.4h1M130 67.4h1M132 67.4h1M133.3 77.6h1.3M134 76.9v1.3"/>
<path d="M134 67.4h1M135.3 77.6h7.6M136 67.4h1.1M138.1 67.4h1M140.1 67.4h1M142.1 67.4h1M144.1 67.4h1M146.1 67.4h1.1M148.2 67.4h1M150.2 67.4h1M152.2 67.4h1M154.2 67.4h1"/>
<path d="M156.2 67.4h1.1M158.3 67.4h1M160.3 67.4h1M161.3 77.6h1.3M161.9 76.9v1.3M162.3 67.4h1M163.2 77.6h7.6M164.3 67.4h1M166.3 67.4h1M168.4 67.4h1M170.4 67.4h1M172.4 67.4h1"/>
<path d="M174.4 67.4h1M176.4 67.4h1M178.5 67.4h1M180.5 67.4h1M182.5 67.4h1M183.5 60.1v1.1M183.5 62.2v1.1M183.5 64.3v1.1M183.5 66.4v2.2M183.5 69.6v1.2M183.5 71.8v1.1M183.5 73.9v1.2"/>
<path d="M183.5 76.1v1.2M183.5 78.3v1.1M188.6 75h5.1M194.7 75h4M196.2 62.4h5.1M206.4 62.4h2.5M216.5 67.4h5.1M216.5 75h5.1M216.5 62.4h5.1M216.5 70h5.1M264.8 62.4h2.5M23.5 97.9h1"/>
<path d="M25.5 97.9h1M27.5 97.9h1.1M29.5 97.9h1.1M31.1 92.8h7.7M31.6 97.9h1M33.6 97.9h1M33.7 82.7h5.1M33.7 87.7h5.1M35.6 97.9h1M37.6 97.9h1M39.6 97.9h1M41.6 97.9h1"/>
<path d="M43.6 97.9h1M45.6 97.9h1.1M47.6 97.9h1.1M49.7 97.9h1M51.7 97.9h1M53.7 97.9h1M55.7 97.9h1M56.5 92.8h7.7M57.7 97.9h1M59.1 82.7h5.1M59.1 87.7h5.1M59.7 97.9h1"/>
<path d="M61.7 97.9h1M63.8 97.9h.9M65.8 97.9h1M67.8 97.9h1M69.8 97.9h1M71.8 97.9h1M73.8 97.9h1M75.8 97.9h1M77.8 97.9h1M79.8 97.9h1.1M81.9 97.9h1M81.9 92.8h7.6"/>
<path d="M83.9 97.9h1M84.5 82.7h5M84.5 87.7h5M85.9 97.9h1M87.9 97.9h1M89.9 97.9h1M91.9 97.9h1M93.9 97.9h1M95.9 97.9h1M97.9 97.9h1.1M99.9 97.9h1.1M102 97.9h1"/>
<path d="M104 97.9h1M106 97.9h1M107.3 92.8h7.6M108 97.9h1M109.9 82.7h5M109.9 87.7h5M110 97.9h1M112 97.9h1M114 97.9h1M116 97.9h1.1M118 97.9h1.1M120.1 97.9h1"/>
<path d="M122.1 97.9h1M124.1 97.9h2.1M125.1 97.9v1.1M125.1 100v1M127.1 97.9h1.1M129.2 97.9h1M131.2 97.9h1.1M133.3 97.9h1M135.3 92.8h7.6M135.3 97.9h1.1M137.4 97.9h1M137.8 82.7h5.1"/>
<path d="M137.8 87.7h5.1M139.4 97.9h1.1M141.5 97.9h1M143.5 97.9h1.1M145.6 97.9h1M147.6 97.9h1.1M149.7 97.9h1M151.7 97.9h1.1M153.8 97.9h1M155.8 97.9h1.1M157.9 97.9h1M159.9 97.9h1.1"/>
<path d="M162 97.9h1M163.2 92.8h7.6M164 97.9h1.1M165.7 82.7h5.1M165.7 87.7h5.1M166.1 97.9h1M168.1 97.9h1.1M170.2 97.9h1M172.2 97.9h1.1M174.3 97.9h1M176.3 97.9h1.1M178.4 97.9h1"/>
<path d="M180.4 97.9h1.1M182.5 97.9h1M183.5 80.4v1.2M183.5 82.6v1.2M183.5 84.8v1.1M183.5 87v1.1M183.5 89.1v2.3M183.5 92.4v1.2M183.5 94.6v1.1M183.5 96.8v2.2M183.5 100v1M183.5 90.3h1"/>
<path d="M185.5 90.3h1M187.5 90.3h1M189.5 90.3h1M191.5 90.3h1.1M193.5 90.3h1.1M195.6 90.3h1M197.6 90.3h1M199.6 90.3h1M201.6 90.3h1M203.6 90.3h1M205.6 90.3h1M207.6 90.3h1"/>
<path d="M209.6 90.3h1M211.6 90.3h1M213.6 90.3h1.1M215.6 90.3h1.1M216.5 80.1h5.1M217.7 90.3h1M219.7 90.3h1M221.7 90.3h1M223.7 90.3h1M225.7 90.3h1M227.7 90.3h1M229.7 90.3h1"/>
<path d="M231.7 90.3h1M233.7 90.3h1M235.8 90.3h.9M237.8 90.3h1M239.8 90.3h1M241.8 90.3h1M243.8 90.3h1M245.8 90.3h1M247.8 90.3h1M249.8 90.3h1M251.8 90.3h1M253.8 90.3h1"/>
<path d="M255.8 90.3h1.1M257.9 90.3h.9M259.9 90.3h1M261.9 90.3h1M263.9 90.3h1M265.9 90.3h1M267.9 90.3h1M269.9 90.3h1M271.9 90.3h1M273.9 90.3h1M18.4 102.3h3.8M31.1 115.7h2.6"/>
<path d="M31.1 105.5v5.1M31.1 113.1v5.1M33.5 110.2l.9-.4-.3 .9zM33.6 110.2h.7M33.7 110.3h.5M33.7 111.4l.9-.4-.4 .9zM33.7 111.4h.7M33.8 110.4h.4M33.8 111.5h.5M33.8 111.3h.6M33.9 110.1h.4M33.9 110.6h.2"/>
<path d="M34 111.7h.3M34 110.7h.1M34.1 111.8h.1M34.1 111.2h.4M34.1 110h.3M34.4 111h.1M34.4 109.8h.1M34.4 109.8l-1.4 1.4M34.6 111l-1.4 1.4M36.9 110.6h1.2M37.5 110v1.2M38.8 110.6h7.6"/>
<path d="M38.8 115.7h7.6M64.2 115.7h2.5M64.2 105.5v5.1M64.2 113.1v5.1M66.6 110.2h.7M66.7 110.3h.5M66.7 111.4l.9-.4-.4 .9zM66.7 111.4h.7M66.8 110.4h.4M66.9 111.5h.4M66.9 111.3h.5M66.9 110.1h.5"/>
<path d="M66.9 110.6h.2M67 111.7h.3M67 110.7h.1M67.1 111.8h.1M67.1 111.2h.4M67.2 110h.2M67.4 111h.1M67.4 109.8h.1M67.5 109.8l-1.4 1.4M67.5 109.8l-.4 .9-.5-.5M67.5 109.8l-.9 .4M67.6 111l-1.4 1.4"/>
<path d="M69.9 110.6h1.2M70.5 110v1.2M71.8 110.6h7.6M71.8 115.7h7.6M97.2 115.7h2.5M97.2 105.5v5.1M97.2 113.1v5.1M99.6 110.2l.9-.4-.4 .9zM99.6 110.2h.7M99.7 110.3h.5M99.7 111.4l.9-.4-.4 .9zM99.8 111.4h.6"/>
<path d="M99.8 110.4h.4M99.9 111.5h.5M99.9 111.3h.6M99.9 110.1h.5M99.9 110.6h.3M100 111.7h.3M100 110.7h.1M100.1 111.8h.1M100.2 111.2h.3M100.2 110h.2M100.4 111h.2M100.5 109.8l-1.4 1.4"/>
<path d="M100.5 109.8v.1M100.6 111l-1.4 1.4M102.9 110.6h1.2M103.5 110v1.2M104.8 110.6h7.6M104.8 115.7h7.6M125.1 102v1.1M125.1 104.1v1.1M125.1 106.2v1.1M125.1 108.2v1.1M125.1 110.3v1.1M125.1 112.4v1.1"/>
<path d="M125.1 114.5v1M125.1 116.5v1.1M125.1 118.6v1.1M135.3 118.2v5.1M163.2 105.5h7.6M165.7 110.6h5.1M165.7 115.7h5.1M183.5 102v1.1M183.5 104.1v1.1M183.5 106.2v1.1M183.5 108.2v1.1M183.5 110.3v1.1"/>
<path d="M183.5 112.4v1.1M183.5 114.5v1M183.5 116.5v1.1M183.5 118.6v1.1M186.1 118.2h2.5M186.1 113.1v2.6M190.4 117.7h6.6v1h-6.6zM191.8 118.5h.5M191.8 118h.5M193.7 117.7v1M198.7 118.2h2.6M203.8 110.6v5.1"/>
<path d="M211.4 108.1v5M211.4 118.2v2.6M219.1 115.7v2.5h5M219.1 105.5v5.1M259.7 118.2h5.1M259.7 117.2l-2 1 2 1M259.7 113.1h5.1M264.8 100.4v6.6M264.8 108.1v2.5M267.3 113.1h2.6M274.9 102.3h3.8M31.1 123.3v5.1"/>
<path d="M31.1 136v5.1M41.3 120.8h5.1M64.2 123.3v5.1M64.2 136v5.1M74.3 120.8h5.1M97.2 123.3v5.1M97.2 136v5.1M107.3 120.8h5.1M125.1 120.7v1.1M125.1 122.8v1M125.1 124.8v1.1M125.1 126.9v1.1"/>
<path d="M125.1 129v1M125.1 131v1.1M125.1 133.1v1.1M125.1 135.2v1M125.1 137.3v1M125.1 139.3v1.1M135.3 128.4v2.5M135.3 133.5v2.5M137.7 130.5l.9-.3-.4 .8zM137.7 130.6h.7M137.8 131.7h.7M137.8 130.5h.6"/>
<path d="M137.8 130.7h.5M137.9 131.8h.6M138 130.8h.3M138 131.9h.4M138.1 131.6h.5M138.1 130.9h.1M138.1 130.3h.4M138.2 132h.2M138.3 132.1h.1M138.4 131.4h.2M138.4 130.2h.1M138.6 130.2l-1.4 1.4"/>
<path d="M138.6 131.3h.1M138.7 131.3l-1.4 1.4M138.7 131.3l-.4 .9-.5-.5M138.7 131.3l-.9 .4M143.5 133.5h1.3M144.1 132.8v1.3M145.4 133.5h7.6M148 138.5h5M163.2 125.8h7.6M165.7 120.8h5.1M183.5 120.7v1.1M183.5 122.8v1"/>
<path d="M183.5 124.8v1.1M183.5 126.9v1.1M183.5 129v1M183.5 131v1.1M183.5 133.1v1.1M183.5 135.2v1M183.5 137.3v1M183.5 139.3v1.1M186.1 120.8h2.5M186.1 123.3h2.5M190.4 122.8h6.6v1h-6.6zM190.4 120.2h6.6v1.1h-6.6z"/>
<path d="M191.8 123.5h.5M191.8 123h.5M191.8 121h.5M191.8 120.5h.5M193.7 120.2v1.1M193.7 122.8v1M196.2 133.5h2.5M198.7 120.8h2.6M198.7 123.3h2.6M203.8 133.5h2.6M203.8 130.9h2.6M203.8 125.8h2.6"/>
<path d="M203.8 120.8v2.5M211.4 133.5h2.6M211.4 130.9h2.6M211.4 125.8h2.6M219.1 133.5h5M219.1 138.5h5M219.1 130.9h5M219.1 120.8h5M219.1 123.3h5M219.1 125.8h5M224.1 137.5l2 1-2 1M224.1 129.9l2 1-2 1"/>
<path d="M259.7 133.5h5.1M259.7 120.8h5.1M259.7 125.8h5.1M259.7 124.8l-2 1 2 1M259.7 132.5l-2 1 2 .9M259.7 128.4h5.1M259.7 136h5.1M18.4 145.2h3.8M31.1 146.2h2.6M31.1 143.6v5.1M31.1 153.8v5M33.5 140.7l.9-.4-.3 .9z"/>
<path d="M33.6 140.7h.7M33.7 141.8l.9-.3-.4 .8zM33.7 140.8h.5M33.7 141.8h.7M33.8 141.9h.6M33.8 140.6h.5M33.8 140.9h.4M33.9 142h.4M33.9 141.1h.2M34 142.2h.2M34 141.7h.5M34 140.5h.4"/>
<path d="M34.1 142.3h.1M34.3 141.6h.2M34.3 140.4h.1M34.4 140.3l-1.4 1.4M34.6 141.5l-1.4 1.4M36.9 141.1h1.2M37.5 140.4v1.3M38.8 141.1h7.6M38.8 146.2h7.6M41.3 151.2h5.1M64.2 146.2h2.5M64.2 143.6v5.1"/>
<path d="M64.2 153.8v5M66.6 140.7l.9-.4-.4 .9zM66.6 140.7h.7M66.7 141.8l.9-.3-.4 .8zM66.7 140.8h.5M66.8 141.8h.6M66.8 141.9h.6M66.8 140.6h.5M66.8 140.9h.4M66.9 142h.4M67 141.1h.1M67 142.2h.3"/>
<path d="M67 141.7h.5M67.1 140.5h.3M67.1 142.3h.1M67.3 141.6h.2M67.3 140.4h.1M67.5 140.3l-1.4 1.4M67.6 141.5l-1.4 1.4M69.9 141.1h1.2M70.5 140.4v1.3M71.8 141.1h7.6M71.8 146.2h7.6M74.3 151.2h5.1"/>
<path d="M97.2 146.2h2.5M97.2 143.6v5.1M97.2 153.8v5M99.6 140.7l.9-.4-.4 .9zM99.6 140.7h.7M99.7 141.8l.9-.3-.4 .8zM99.7 140.8h.5M99.8 141.8h.6M99.8 141.9h.6M99.8 140.6h.5M99.8 140.9h.4M99.9 142h.4"/>
<path d="M100 141.1h.1M100 142.2h.3M100.1 141.7h.4M100.1 140.5h.3M100.2 142.3h.1M100.3 141.6h.2M100.4 140.4h.1M100.5 140.3l-1.4 1.4M100.6 141.5l-1.4 1.4M102.9 141.1h1.2M103.5 140.4v1.3M104.8 141.1h7.6"/>
<path d="M104.8 146.2h7.6M107.3 151.2h5.1M125.1 141.4v1.1M125.1 143.5v1M125.1 145.5v1.1M125.1 147.6v2.1M125.1 150.7v1M125.1 152.7v1.1M125.1 154.8v1M125.1 156.8v1M125.1 158.8v1.1M125.1 148.7h1.1"/>
<path d="M127.1 148.7h1.1M129.2 148.7h1M131.2 148.7h1.1M133.3 148.7h1M135.3 148.7h1.1M137.4 148.7h1M139.4 148.7h1.1M141.5 148.7h1M143.5 148.7h1.1M145.4 143.6h7.6M145.6 148.7h1M147.6 148.7h1.1"/>
<path d="M149.7 148.7h1M150.5 156.3v5.1M151.7 148.7h1.1M153.8 148.7h1M155.8 148.7h1.1M157.9 148.7h1M159.9 148.7h1.1M162 148.7h1M164 148.7h1.1M166.1 148.7h1M168.1 148.7h1.1M170.2 148.7h1"/>
<path d="M172.2 148.7h1.1M174.3 148.7h1M176.3 148.7h1.1M178.4 148.7h1M180.4 148.7h1.1M182.5 148.7h1M183.5 141.4v1.1M183.5 143.5v1M183.5 145.5v1.1M183.5 147.6v2.2M183.5 150.8v1M183.5 152.9v1"/>
<path d="M183.5 154.9v1.1M183.5 157v1.1M183.5 159.1v1.1M219.1 148.7h5M219.1 141.1h5M219.1 153.8h5M219.1 146.2h5M219.1 156.3h5M224.1 152.8l2 1-2 .9M224.1 145.2l2 1-2 .9M259.7 148.7h5.1M259.7 143.6h5.1"/>
<path d="M259.7 140.1l-2 1 2 .9M259.7 141.1h5.1M259.7 147.7l-2 1 2 1M259.7 151.2h5.1M259.7 158.8h7.6M274.9 145.2h3.8M23.5 163.9h1.1M25.6 163.9h1M27.6 163.9h1M29.7 163.9h1M31.1 169h7.7M31.7 163.9h1"/>
<path d="M33.7 174.1h5.1M33.7 179.2h5.1M33.7 163.9h1.1M35.8 163.9h1M37.8 163.9h1.1M39.9 163.9h1M41.9 163.9h1.1M44 163.9h1M46 163.9h1.1M48 163.9h1.1M50.1 163.9h1M52.1 163.9h1.1"/>
<path d="M54.2 163.9h1M56.2 163.9h1.1M58.3 163.9h1M60.3 163.9h1.1M62.4 163.9h1M64.4 163.9h1M66.4 163.9h1.1M68.5 163.9h1M70.5 163.9h1.1M72.6 163.9h1M74.6 163.9h1.1M76.7 163.9h1"/>
<path d="M78.7 163.9h1.1M80.8 163.9h1M81.9 169h7.6M82.8 163.9h1M84.5 174.1h5M84.5 179.2h5M84.8 163.9h1.1M86.9 163.9h1M88.9 163.9h1.1M91 163.9h1M93 163.9h1.1M95.1 163.9h1"/>
<path d="M97.1 163.9h1M99.1 163.9h1.1M101.2 163.9h2.2M102.2 163.9v1.2M102.2 166.1v1.2M102.2 168.3v1.1M102.2 170.4v1.2M102.2 172.6v1.2M102.2 174.8v1.1M102.2 176.9v1.2M102.2 179.1v1.2M104.4 163.9h1.2"/>
<path d="M104.8 169h5.1M106.6 163.9h1.1M108.8 163.9h1.1M110.9 163.9h1.2M113.1 163.9h1.2M114.9 169h2.6v2.5M115.3 163.9h1.1M117.4 163.9h1.2M117.5 174.1v2.5M119.6 163.9h1.2M119.9 171.2l.9-.4-.4 .9zM120 171.2h.6"/>
<path d="M120 171.1h.6M120 172.3h.7M120.1 171.3h.4M120.2 172.4h.5M120.2 171.5h.3M120.3 172.6h.3M120.3 172.2h.5M120.3 171h.4M120.3 171.6h.1M120.4 172.7h.2M120.5 172.1h.3M120.6 170.9h.1"/>
<path d="M120.8 170.8l-1.4 1.4M120.8 172h.1M120.9 171.9l-1.4 1.4M120.9 171.9l-.4 .9M120.9 171.9l-.9 .4 .5 .5M121.8 163.9h1.1M125.1 162.9v1h-1.2M125.1 160.9v1M125.1 171.5h7.6M127.6 176.6h5.1M150.5 166.5v5M150.5 174.1v2.5"/>
<path d="M152.9 171.2l.9-.4-.4 .9zM153 171.2h.6M153 171.1h.6M153.1 172.3h.7M153.1 171.3h.4M153.2 172.4h.5M153.2 171.5h.3M153.3 172.6h.3M153.3 172.2h.5M153.3 171h.4M153.3 171.6h.1M153.4 172.7h.2"/>
<path d="M153.5 172.8h.1M153.6 172.1h.3M153.6 170.9h.2M153.8 170.8l-1.4 1.4M153.8 172h.1M153.9 171.9l-1.4 1.4M153.9 171.9l-.4 .9M153.9 171.9l-.9 .4 .5 .5M160.7 171.5h7.6M163.2 176.6h5.1M183.5 161.2v1.1M183.5 163.3v1.1"/>
<path d="M183.5 165.4v1.1M233.7 172.8h41.2M233.7 167.7v20.3M233.7 177.9h41.2M274.9 167.7h-95.2v20.3M31.1 184.2h7.7M64.4 188v3.9M81.9 184.2h7.6M102.2 181.3v1.1M102.2 183.4v1.2M102.2 185.6v1.2M106.5 188v3.9"/>
<path d="M125.1 181.7h7.6M148.6 188v3.9M160.7 181.7h7.6M190.7 188v3.9M232.8 188v3.9M233.7 183h41.2M264.8 183v5"/>
<circle cx="28.5" cy="38.7" r=".99"/>
<circle cx="32.6" cy="38.6" r=".99"/>
<circle cx="48.8" cy="38.5" r=".99"/>
<circle cx="52.9" cy="38.4" r=".99"/>
<circle cx="28.5" cy="42.8" r=".99"/>
<circle cx="32.5" cy="42.8" r=".99"/>
<circle cx="48.8" cy="42.6" r=".99"/>
<circle cx="52.8" cy="42.5" r=".99"/>
</g>
<g fill="#c90d0c" stroke="#c90d0c" stroke-width=".21">
<path d="M194.1 183.4l.5 .1z"/>
<path d="M194.9 183.4l.2 .1z"/>
<path d="M195.4 183.4l.2 .1z"/>
<path d="M195.8 183.4l.3 .1z"/>
<path d="M196.4 183.4l.4 .1z"/>
<path d="M197.2 183.4l.3 .1z"/>
<path d="M198.1 183.4l.2 .1z"/>
<path d="M198.5 183.4l.3 .1z"/>
<path d="M199 183.4l.3 .1z"/>
<path d="M199.6 183.4l.5 .1z"/>
<path d="M200.4 183.4l.4 .1z"/>
<path d="M201.2 183.4l.2 .1z"/>
<path d="M201.8 183.4l.2 .1z"/>
<path d="M202.2 183.4l.6 .1z"/>
<path d="M203 183.4l.3 .1z"/>
<path d="M203.6 183.4l.6 .1z"/>
<path d="M204.9 183.4l.6 .1z"/>
<path d="M205.6 183.4l.2 .1z"/>
<path d="M206.3 183.4l.2 .1z"/>
<path d="M206.8 183.4l.2 .1z"/>
<path d="M207.2 183.4l.2 .1z"/>
<path d="M207.7 183.4l.2 .1z"/>
<path d="M208.8 183.4l.6 .1z"/>
<path d="M209.5 183.4l.2 .1z"/>
<path d="M210.2 183.4l.2 .1z"/>
<path d="M210.7 183.4l.2 .1z"/>
<path d="M211.2 183.4l.6 .1z"/>
<path d="M212 183.4l.4 .1z"/>
<path d="M212.6 183.4l.2 .1z"/>
<path d="M213 183.4l.3 .1z"/>
<path d="M214.2 183.4l.3 .1z"/>
<path d="M214.6 183.4l.2 .1z"/>
<path d="M215.4 183.4l.3 .1z"/>
<path d="M215.9 183.4l.2 .1z"/>
<path d="M216.4 183.4l.2 .1z"/>
<path d="M194.1 183.3l.5 .1z"/>
<path d="M194.9 183.3l.2 .1z"/>
<path d="M195.4 183.3l.2 .1z"/>
<path d="M195.7 183.3l.5 .1z"/>
<path d="M196.4 183.3l.5 .1z"/>
<path d="M197.1 183.3l.5 .1z"/>
<path d="M198.1 183.3l.2 .1z"/>
<path d="M198.5 183.3l.2 .1z"/>
<path d="M198.9 183.3l.5 .1z"/>
<path d="M199.6 183.3l.5 .1z"/>
<path d="M200.4 183.3l.5 .1z"/>
<path d="M201.2 183.3l.2 .1z"/>
<path d="M201.7 183.3l.3 .1z"/>
<path d="M202.2 183.3l.5 .1z"/>
<path d="M202.9 183.3l.5 .1z"/>
<path d="M203.6 183.3l.6 .1z"/>
<path d="M204.9 183.3l.6 .1z"/>
<path d="M205.6 183.3l.2 .1z"/>
<path d="M206.3 183.3l.2 .1z"/>
<path d="M206.8 183.3l.2 .1z"/>
<path d="M207.2 183.3l.2 .1z"/>
<path d="M207.6 183.3l.3 .1z"/>
<path d="M208.8 183.3l.6 .1z"/>
<path d="M209.5 183.3l.2 .1z"/>
<path d="M210.2 183.3l.2 .1z"/>
<path d="M210.7 183.3l.2 .1z"/>
<path d="M211.2 183.3l.6 .1z"/>
<path d="M212 183.3l.4 .1z"/>
<path d="M212.6 183.3l.2 .1z"/>
<path d="M213 183.3l.3 .1z"/>
<path d="M214.2 183.3l.3 .1z"/>
<path d="M214.6 183.3l.2 .1z"/>
<path d="M215.3 183.3l.5 .1z"/>
<path d="M215.9 183.3l.3 .1z"/>
<path d="M216.4 183.3l.2 .1z"/>
<path d="M194.1 183.3h.5z"/>
<path d="M195 183.3h.6z"/>
<path d="M195.7 183.3h.2z"/>
<path d="M196 183.3h.2z"/>
<path d="M196.3 183.3h.3z"/>
<path d="M196.6 183.3h.3z"/>
<path d="M197.1 183.3h.6z"/>
<path d="M198.1 183.3h.2z"/>
<path d="M198.5 183.3h.2z"/>
<path d="M198.8 183.3h.6z"/>
<path d="M199.6 183.3h.6z"/>
<path d="M200.3 183.3h.6z"/>
<path d="M201.2 183.3h.2z"/>
<path d="M201.7 183.3h.3z"/>
<path d="M202.1 183.3h.6z"/>
<path d="M202.9 183.3h.6z"/>
<path d="M203.6 183.3h.6z"/>
<path d="M204.9 183.3h.6z"/>
<path d="M205.6 183.3h.2z"/>
<path d="M206.3 183.3h.2z"/>
<path d="M206.8 183.3h.2z"/>
<path d="M207.2 183.3h.7z"/>
<path d="M208.8 183.3h.6z"/>
<path d="M209.5 183.3h.2z"/>
<path d="M210.2 183.3h.2z"/>
<path d="M210.7 183.3h.2z"/>
<path d="M211.2 183.3h.6z"/>
<path d="M211.9 183.3h.6z"/>
<path d="M212.6 183.3h.2z"/>
<path d="M213 183.3h.3z"/>
<path d="M214.2 183.3h.3z"/>
<path d="M214.6 183.3h.2z"/>
<path d="M215.3 183.3h.2z"/>
<path d="M215.6 183.3h.2z"/>
<path d="M215.9 183.3h.7z"/>
<path d="M193.4 183.3h.3z"/>
<path d="M194.1 183.3h.2z"/>
<path d="M196.3 183.3h.2z"/>
<path d="M196.7 183.3h.2z"/>
<path d="M197 183.3h.3z"/>
<path d="M197.4 183.3h.3z"/>
<path d="M198.4 183.3h.3z"/>
<path d="M198.8 183.3h.3z"/>
<path d="M199.2 183.3h.3z"/>
<path d="M199.6 183.3h.2z"/>
<path d="M200 183.3h.2z"/>
<path d="M200.3 183.3h.3z"/>
<path d="M200.7 183.3h.3z"/>
<path d="M202.1 183.3h.2z"/>
<path d="M202.4 183.3h.3z"/>
<path d="M202.9 183.3h.2z"/>
<path d="M203.3 183.3h.2z"/>
<path d="M203.6 183.3h.3z"/>
<path d="M204.9 183.3h.3z"/>
<path d="M207.3 183.3h.5z"/>
<path d="M208.8 183.3h.2z"/>
<path d="M211.2 183.3h.2z"/>
<path d="M211.9 183.3h.2z"/>
<path d="M212.3 183.3h.2z"/>
<path d="M215.9 183.3h.6z"/>
<path d="M217 183.3h.2z"/>
<path d="M193.4 183.2h.3z"/>
<path d="M194.1 183.2h.2z"/>
<path d="M195 183.2h.5z"/>
<path d="M196 183.2h.2z"/>
<path d="M196.7 183.2h.2z"/>
<path d="M197 183.2h.3z"/>
<path d="M197.4 183.2h.3z"/>
<path d="M198.1 183.2h.2z"/>
<path d="M198.4 183.2h.3z"/>
<path d="M198.8 183.2h.2z"/>
<path d="M199.3 183.2h.2z"/>
<path d="M199.6 183.2h.2z"/>
<path d="M200 183.2h.2z"/>
<path d="M200.3 183.2h.2z"/>
<path d="M200.7 183.2h.3z"/>
<path d="M201.2 183.2h.2z"/>
<path d="M201.7 183.2h.3z"/>
<path d="M202.1 183.2h.2z"/>
<path d="M202.5 183.2h.2z"/>
<path d="M202.9 183.2h.2z"/>
<path d="M203.3 183.2h.2z"/>
<path d="M203.6 183.2h.3z"/>
<path d="M204.9 183.2h.2z"/>
<path d="M205.6 183.2h.2z"/>
<path d="M206.3 183.2h.2z"/>
<path d="M206.8 183.2h.2z"/>
<path d="M207.3 183.2h.5z"/>
<path d="M208.8 183.2h.2z"/>
<path d="M209.5 183.2h.2z"/>
<path d="M210.2 183.2h.2z"/>
<path d="M210.7 183.2h.2z"/>
<path d="M211.2 183.2h.2z"/>
<path d="M211.9 183.2h.2z"/>
<path d="M212.3 183.2h.2z"/>
<path d="M212.6 183.2h.2z"/>
<path d="M213 183.2h.3z"/>
<path d="M214.2 183.2h.3z"/>
<path d="M214.6 183.2h.2z"/>
<path d="M215.6 183.2h.2z"/>
<path d="M216 183.2h.5z"/>
<path d="M217 183.2h.2z"/>
<path d="M195 183.2h.2z"/>
<path d="M195.3 183.2h.2z"/>
<path d="M195.9 183.2h.3z"/>
<path d="M196.6 183.2h.3z"/>
<path d="M197 183.2h.2z"/>
<path d="M197.5 183.2h.2z"/>
<path d="M198.1 183.2h.5z"/>
<path d="M199.6 183.2h.6z"/>
<path d="M202.5 183.2h.3z"/>
<path d="M203.6 183.2h.6z"/>
<path d="M204.9 183.2h.5z"/>
<path d="M205.6 183.2h.5z"/>
<path d="M207.2 183.2h.3z"/>
<path d="M207.6 183.2h.2z"/>
<path d="M208.8 183.2h.5z"/>
<path d="M209.5 183.2h.5z"/>
<path d="M211.2 183.2h.5z"/>
<path d="M212.6 183.2h.7z"/>
<path d="M214.6 183.2h.5z"/>
<path d="M215.5 183.2h.3z"/>
<path d="M216 183.2h.2z"/>
<path d="M216.3 183.2h.2z"/>
<path d="M194.1 183.1h.2z"/>
<path d="M195 183.1h.2z"/>
<path d="M195.3 183.1h.2z"/>
<path d="M195.7 183.1h.5z"/>
<path d="M196.4 183.1h.5z"/>
<path d="M197 183.1h.2z"/>
<path d="M197.5 183.1h.2z"/>
<path d="M198.1 183.1h.6z"/>
<path d="M198.8 183.1h.2z"/>
<path d="M199.3 183.1h.2z"/>
<path d="M199.6 183.1h.5z"/>
<path d="M200.3 183.1h.2z"/>
<path d="M200.7 183.1h.3z"/>
<path d="M201.2 183.1h.2z"/>
<path d="M201.7 183.1h.3z"/>
<path d="M202.1 183.1h.2z"/>
<path d="M202.5 183.1h.3z"/>
<path d="M202.9 183.1h.2z"/>
<path d="M203.3 183.1h.2z"/>
<path d="M203.6 183.1h.6z"/>
<path d="M204.9 183.1h.6z"/>
<path d="M205.6 183.1h.5z"/>
<path d="M206.3 183.1h.2z"/>
<path d="M206.8 183.1h.2z"/>
<path d="M207.3 183.1h.2z"/>
<path d="M207.6 183.1h.2z"/>
<path d="M208.8 183.1h.6z"/>
<path d="M209.5 183.1h.5z"/>
<path d="M210.2 183.1h.2z"/>
<path d="M210.7 183.1h.2z"/>
<path d="M211.2 183.1h.5z"/>
<path d="M211.9 183.1h.2z"/>
<path d="M212.6 183.1h.7z"/>
<path d="M214.2 183.1h.3z"/>
<path d="M214.6 183.1h.6z"/>
<path d="M215.3 183.1h.5z"/>
<path d="M216 183.1h.2z"/>
<path d="M216.3 183.1h.2z"/>
<path d="M194.1 183l.2 .1z"/>
<path d="M195.1 183l.1 .1z"/>
<path d="M195.3 183l.2 .1z"/>
<path d="M195.7 183l.4 .1z"/>
<path d="M196.4 183l.4 .1z"/>
<path d="M197 183l.2 .1z"/>
<path d="M197.5 183l.2 .1z"/>
<path d="M198.1 183l.6 .1z"/>
<path d="M198.8 183l.2 .1z"/>
<path d="M199.3 183l.2 .1z"/>
<path d="M199.6 183l.5 .1z"/>
<path d="M200.3 183l.2 .1z"/>
<path d="M200.7 183l.3 .1z"/>
<path d="M201.2 183l.2 .1z"/>
<path d="M201.7 183l.3 .1z"/>
<path d="M202.1 183l.2 .1z"/>
<path d="M202.5 183l.2 .1z"/>
<path d="M202.9 183l.2 .1z"/>
<path d="M203.3 183l.2 .1z"/>
<path d="M203.6 183l.6 .1z"/>
<path d="M204.9 183l.6 .1z"/>
<path d="M205.6 183l.2 .1z"/>
<path d="M205.9 183l.2 .1z"/>
<path d="M206.3 183l.2 .1z"/>
<path d="M206.8 183l.2 .1z"/>
<path d="M207.3 183l.2 .1z"/>
<path d="M207.6 183l.2 .1z"/>
<path d="M208.8 183l.6 .1z"/>
<path d="M209.5 183l.2 .1z"/>
<path d="M209.8 183l.3 .1z"/>
<path d="M210.2 183l.2 .1z"/>
<path d="M210.7 183l.2 .1z"/>
<path d="M211.2 183l.5 .1z"/>
<path d="M211.9 183l.2 .1z"/>
<path d="M212.6 183l.7 .1z"/>
<path d="M214.2 183l.3 .1z"/>
<path d="M214.6 183l.2 .1z"/>
<path d="M214.9 183l.3 .1z"/>
<path d="M215.3 183l.4 .1z"/>
<path d="M216 183l.2 .1z"/>
<path d="M216.3 183l.2 .1z"/>
<path d="M194.1 183h.2z"/>
<path d="M194.7 183h.2z"/>
<path d="M195.1 183h.4z"/>
<path d="M195.7 183h.3z"/>
<path d="M196.3 183h.3z"/>
<path d="M197 183h.3z"/>
<path d="M197.4 183h.3z"/>
<path d="M198.1 183h.2z"/>
<path d="M198.5 183h.2z"/>
<path d="M198.8 183h.2z"/>
<path d="M199.2 183h.3z"/>
<path d="M199.6 183h.2z"/>
<path d="M199.9 183h.3z"/>
<path d="M200.3 183h.2z"/>
<path d="M200.7 183h.3z"/>
<path d="M201.2 183h.2z"/>
<path d="M201.7 183h.3z"/>
<path d="M202.1 183h.2z"/>
<path d="M202.5 183h.2z"/>
<path d="M202.9 183h.2z"/>
<path d="M203.3 183h.2z"/>
<path d="M203.6 183h.3z"/>
<path d="M204.9 183h.2z"/>
<path d="M205.6 183h.2z"/>
<path d="M206 183h.2z"/>
<path d="M206.3 183h.2z"/>
<path d="M206.8 183h.2z"/>
<path d="M207.4 183h.3z"/>
<path d="M208.8 183h.2z"/>
<path d="M209.5 183h.2z"/>
<path d="M209.8 183h.3z"/>
<path d="M210.2 183h.2z"/>
<path d="M210.7 183h.2z"/>
<path d="M211.2 183h.2z"/>
<path d="M211.9 183h.2z"/>
<path d="M212.6 183h.2z"/>
<path d="M213 183h.3z"/>
<path d="M214.2 183h.3z"/>
<path d="M214.6 183h.2z"/>
<path d="M215 183h.2z"/>
<path d="M215.3 183h.3z"/>
<path d="M216 183h.5z"/>
<path d="M194.1 182.9l.2 .1z"/>
<path d="M194.6 182.9l.3 .1z"/>
<path d="M195.1 182.9l.3 .1z"/>
<path d="M195.7 182.9l.2 .1z"/>
<path d="M196 182.9l.2 .1z"/>
<path d="M196.3 182.9l.2 .1z"/>
<path d="M196.7 182.9l.2 .1z"/>
<path d="M197 182.9l.3 .1z"/>
<path d="M197.4 182.9l.3 .1z"/>
<path d="M198.1 182.9l.2 .1z"/>
<path d="M198.5 182.9l.2 .1z"/>
<path d="M198.8 182.9l.3 .1z"/>
<path d="M199.2 182.9l.2 .1z"/>
<path d="M199.6 182.9l.2 .1z"/>
<path d="M199.9 182.9l.3 .1z"/>
<path d="M200.3 182.9l.3 .1z"/>
<path d="M200.7 182.9l.3 .1z"/>
<path d="M201 182.9l.6 .1z"/>
<path d="M201.7 182.9l.3 .1z"/>
<path d="M202.1 182.9l.3 .1z"/>
<path d="M202.5 182.9l.2 .1z"/>
<path d="M202.9 182.9l.2 .1z"/>
<path d="M203.3 182.9l.2 .1z"/>
<path d="M203.6 182.9l.3 .1z"/>
<path d="M204.9 182.9l.3 .1z"/>
<path d="M205.6 182.9l.2 .1z"/>
<path d="M205.9 182.9l.3 .1z"/>
<path d="M206.3 182.9l.2 .1z"/>
<path d="M206.6 182.9l.6 .1z"/>
<path d="M207.4 182.9l.3 .1z"/>
<path d="M208.8 182.9l.3 .1z"/>
<path d="M209.5 182.9l.2 .1z"/>
<path d="M209.8 182.9l.3 .1z"/>
<path d="M210.2 182.9l.2 .1z"/>
<path d="M210.5 182.9l.6 .1z"/>
<path d="M211.2 182.9l.2 .1z"/>
<path d="M211.9 182.9l.2 .1z"/>
<path d="M212.2 182.9l.3 .1z"/>
<path d="M212.6 182.9l.2 .1z"/>
<path d="M213 182.9l.3 .1z"/>
<path d="M214.2 182.9l.3 .1z"/>
<path d="M214.6 182.9l.2 .1z"/>
<path d="M215 182.9l.2 .1z"/>
<path d="M215.3 182.9l.2 .1z"/>
<path d="M215.6 182.9l.2 .1z"/>
<path d="M216.1 182.9l.3 .1z"/>
<path d="M194.1 182.9h.2z"/>
<path d="M194.6 182.9h.3z"/>
<path d="M195.1 182.9h.3z"/>
<path d="M195.7 182.9h.5z"/>
<path d="M196.4 182.9h.5z"/>
<path d="M197.1 182.9h.6z"/>
<path d="M198.1 182.9h.6z"/>
<path d="M198.9 182.9h.5z"/>
<path d="M199.6 182.9h.5z"/>
<path d="M200.3 182.9h.6z"/>
<path d="M201 182.9h.7z"/>
<path d="M201.7 182.9h.3z"/>
<path d="M202.1 182.9h.6z"/>
<path d="M202.9 182.9h.2z"/>
<path d="M203.3 182.9h.2z"/>
<path d="M203.6 182.9h.6z"/>
<path d="M204.9 182.9h.6z"/>
<path d="M205.6 182.9h.5z"/>
<path d="M206.3 182.9h.2z"/>
<path d="M206.6 182.9h.6z"/>
<path d="M207.4 182.9h.3z"/>
<path d="M208.8 182.9h.6z"/>
<path d="M209.5 182.9h.5z"/>
<path d="M210.2 182.9h.2z"/>
<path d="M210.5 182.9h.6z"/>
<path d="M211.2 182.9h.6z"/>
<path d="M211.9 182.9h.6z"/>
<path d="M212.6 182.9h.2z"/>
<path d="M213 182.9h.3z"/>
<path d="M214.2 182.9h.3z"/>
<path d="M214.6 182.9h.6z"/>
<path d="M215.3 182.9h.5z"/>
<path d="M216.1 182.9h.3z"/>
<path d="M194.1 182.8l.2 .1z"/>
<path d="M194.6 182.8l.3 .1z"/>
<path d="M195.1 182.8l.3 .1z"/>
<path d="M195.7 182.8l.5 .1z"/>
<path d="M196.4 182.8l.4 .1z"/>
<path d="M197.1 182.8l.5 .1z"/>
<path d="M198.1 182.8l.6 .1z"/>
<path d="M198.9 182.8l.5 .1z"/>
<path d="M199.6 182.8l.5 .1z"/>
<path d="M200.4 182.8l.5 .1z"/>
<path d="M201 182.8l.7 .1z"/>
<path d="M201.7 182.8l.3 .1z"/>
<path d="M202.2 182.8l.4 .1z"/>
<path d="M202.9 182.8l.2 .1z"/>
<path d="M203.3 182.8l.2 .1z"/>
<path d="M203.6 182.8l.6 .1z"/>
<path d="M204.9 182.8l.6 .1z"/>
<path d="M205.6 182.8l.5 .1z"/>
<path d="M206.3 182.8l.2 .1z"/>
<path d="M206.6 182.8l.6 .1z"/>
<path d="M207.4 182.8l.3 .1z"/>
<path d="M208.8 182.8l.6 .1z"/>
<path d="M209.5 182.8l.5 .1z"/>
<path d="M210.2 182.8l.2 .1z"/>
<path d="M210.5 182.8l.6 .1z"/>
<path d="M211.2 182.8l.6 .1z"/>
<path d="M212 182.8l.4 .1z"/>
<path d="M212.6 182.8l.2 .1z"/>
<path d="M213 182.8l.3 .1z"/>
<path d="M214.2 182.8l.3 .1z"/>
<path d="M214.6 182.8l.5 .1z"/>
<path d="M215.3 182.8l.5 .1z"/>
<path d="M216.1 182.8l.3 .1z"/>
<path d="M194.1 182.8h.2z"/>
<path d="M194.7 182.8h.2z"/>
<path d="M195.2 182.8h.2z"/>
<path d="M195.8 182.8h.3z"/>
<path d="M196.5 182.8h.2z"/>
<path d="M197.2 182.8h.2z"/>
<path d="M198.1 182.8h.4z"/>
<path d="M199 182.8h.3z"/>
<path d="M199.6 182.8h.4z"/>
<path d="M200.5 182.8h.2z"/>
<path d="M201 182.8h.6z"/>
<path d="M201.8 182.8h.1z"/>
<path d="M202.3 182.8h.2z"/>
<path d="M202.9 182.8h.2z"/>
<path d="M203.3 182.8h.2z"/>
<path d="M203.6 182.8h.6z"/>
<path d="M205 182.8h.5z"/>
<path d="M205.6 182.8h.4z"/>
<path d="M206.3 182.8h.1z"/>
<path d="M206.6 182.8h.6z"/>
<path d="M207.5 182.8h.1z"/>
<path d="M208.9 182.8h.5z"/>
<path d="M209.5 182.8h.4z"/>
<path d="M210.2 182.8h.2z"/>
<path d="M210.5 182.8h.6z"/>
<path d="M211.2 182.8h.5z"/>
<path d="M212.1 182.8h.2z"/>
<path d="M212.6 182.8h.2z"/>
<path d="M213 182.8h.3z"/>
<path d="M214.2 182.8h.3z"/>
<path d="M214.6 182.8h.4z"/>
<path d="M215.4 182.8h.3z"/>
<path d="M216.1 182.8h.2z"/>
<path d="M193.4 182.3h2z"/>
<path d="M196.4 182.3h.8z"/>
<path d="M198.9 182.3h.9z"/>
<path d="M201 182.3h1.8z"/>
<path d="M203.7 182.3h1z"/>
<path d="M206.4 182.3h.7z"/>
<path d="M208.2 182.3h1.9z"/>
<path d="M210.5 182.3h.7z"/>
<path d="M212.1 182.3h.8z"/>
<path d="M193.4 182.2l2 .1z"/>
<path d="M196.4 182.2l.9 .1z"/>
<path d="M198.8 182.2l1.1 .1z"/>
<path d="M201 182.2l1.8 .1z"/>
<path d="M203.5 182.2l1.3 .1z"/>
<path d="M206.3 182.2l.8 .1z"/>
<path d="M208.2 182.2l1.9 .1z"/>
<path d="M210.5 182.2l.7 .1z"/>
<path d="M212.1 182.2l.8 .1z"/>
<path d="M193.4 182.2h2z"/>
<path d="M196.4 182.2h.8z"/>
<path d="M198.7 182.2h1.3z"/>
<path d="M201 182.2h1.8z"/>
<path d="M203.4 182.2h1.5z"/>
<path d="M206.3 182.2h.8z"/>
<path d="M208.2 182.2h1.9z"/>
<path d="M210.5 182.2h.7z"/>
<path d="M212 182.2h.9z"/>
<path d="M193.4 182.1l2 .1z"/>
<path d="M196.4 182.1l.9 .1z"/>
<path d="M198.6 182.1l1.5 .1z"/>
<path d="M201 182.1l1.8 .1z"/>
<path d="M203.4 182.1l1.6 .1z"/>
<path d="M206.3 182.1l.8 .1z"/>
<path d="M208.2 182.1l1.9 .1z"/>
<path d="M210.5 182.1l.7 .1z"/>
<path d="M212 182.1l.9 .1z"/>
<path d="M193.4 182.1h2z"/>
<path d="M196.4 182.1h.9z"/>
<path d="M198.5 182.1h1.7z"/>
<path d="M201 182.1h1.8z"/>
<path d="M203.3 182.1h1.7z"/>
<path d="M206.3 182.1h.8z"/>
<path d="M208.2 182.1h1.9z"/>
<path d="M210.5 182.1h.7z"/>
<path d="M212 182.1h.8z"/>
<path d="M193.4 182l2 .1z"/>
<path d="M196.3 182l1.1 .1z"/>
<path d="M198.5 182l1.7 .1z"/>
<path d="M201 182l1.8 .1z"/>
<path d="M203.3 182l1.8 .1z"/>
<path d="M206.3 182l.8 .1z"/>
<path d="M208.2 182l1.9 .1z"/>
<path d="M210.5 182l.7 .1z"/>
<path d="M212 182l.8 .1z"/>
<path d="M214.8 182l.2 .1z"/>
<path d="M216.9 182l.2 .1z"/>
<path d="M193.4 182h2z"/>
<path d="M196.3 182h1.1z"/>
<path d="M198.4 182h1.9z"/>
<path d="M201 182h1.8z"/>
<path d="M203.2 182h1.9z"/>
<path d="M206.3 182h.8z"/>
<path d="M208.2 182h1.9z"/>
<path d="M210.5 182h.7z"/>
<path d="M211.9 182h.9z"/>
<path d="M214.6 182h.4z"/>
<path d="M216.7 182h.5z"/>
<path d="M193.4 181.9l2 .1z"/>
<path d="M196.3 181.9l1 .1z"/>
<path d="M198.4 181.9l1.9 .1z"/>
<path d="M201 181.9l1.8 .1z"/>
<path d="M203.2 181.9l2 .1z"/>
<path d="M206.3 181.9l.8 .1z"/>
<path d="M208.2 181.9l1.9 .1z"/>
<path d="M210.5 181.9l.7 .1z"/>
<path d="M211.9 181.9l.8 .1z"/>
<path d="M214.5 181.9l.5 .1z"/>
<path d="M216.6 181.9l.5 .1z"/>
<path d="M193.4 181.9h2z"/>
<path d="M196.3 181.9h1.1z"/>
<path d="M198.3 181.9h2.1z"/>
<path d="M201 181.9h1.8z"/>
<path d="M203.1 181.9h2.1z"/>
<path d="M206.3 181.9h.8z"/>
<path d="M208.2 181.9h1.9z"/>
<path d="M210.5 181.9h.7z"/>
<path d="M211.9 181.9h.8z"/>
<path d="M214.4 181.9h.6z"/>
<path d="M216.5 181.9h.7z"/>
<path d="M193.4 181.8l2 .1z"/>
<path d="M196.2 181.8l1.2 .1z"/>
<path d="M198.3 181.8l1 .1z"/>
<path d="M199.4 181.8l1 .1z"/>
<path d="M201 181.8l1.8 .1z"/>
<path d="M203.1 181.8l2.1 .1z"/>
<path d="M206.3 181.8l.8 .1z"/>
<path d="M208.2 181.8l1.9 .1z"/>
<path d="M210.5 181.8l.7 .1z"/>
<path d="M211.9 181.8l.8 .1z"/>
<path d="M214.2 181.8l.8 .1z"/>
<path d="M216.4 181.8l.7 .1z"/>
<path d="M193.4 181.8h.8z"/>
<path d="M196.2 181.8h1.3z"/>
<path d="M198.3 181.8h.8z"/>
<path d="M199.6 181.8h.8z"/>
<path d="M201 181.8h1.8z"/>
<path d="M203.1 181.8h.8z"/>
<path d="M204.4 181.8h.8z"/>
<path d="M206.3 181.8h.8z"/>
<path d="M208.2 181.8h.7z"/>
<path d="M210.5 181.8h.7z"/>
<path d="M211.8 181.8h.8z"/>
<path d="M214.1 181.8h.9z"/>
<path d="M216.2 181.8h1z"/>
<path d="M193.4 181.7l.8 .1z"/>
<path d="M196.2 181.7l1.3 .1z"/>
<path d="M198.2 181.7l.8 .1z"/>
<path d="M199.7 181.7l.7 .1z"/>
<path d="M201 181.7l.7 .1z"/>
<path d="M203.1 181.7l.8 .1z"/>
<path d="M204.4 181.7l.8 .1z"/>
<path d="M206.3 181.7l.8 .1z"/>
<path d="M208.2 181.7l.7 .1z"/>
<path d="M210.5 181.7l.8 .1z"/>
<path d="M211.8 181.7l.8 .1z"/>
<path d="M214 181.7l1 .1z"/>
<path d="M216.1 181.7l1 .1z"/>
<path d="M193.4 181.7h.8z"/>
<path d="M196.2 181.7h1.2z"/>
<path d="M198.2 181.7h.8z"/>
<path d="M199.7 181.7h.8z"/>
<path d="M201 181.7h.7z"/>
<path d="M203.1 181.7h.8z"/>
<path d="M204.5 181.7h.8z"/>
<path d="M206.3 181.7h.8z"/>
<path d="M208.2 181.7h.7z"/>
<path d="M210.5 181.7h.8z"/>
<path d="M211.8 181.7h.8z"/>
<path d="M213.9 181.7h1.1z"/>
<path d="M216 181.7h1.2z"/>
<path d="M193.4 181.6l.8 .1z"/>
<path d="M196.2 181.6l1.3 .1z"/>
<path d="M198.2 181.6l.7 .1z"/>
<path d="M199.7 181.6l.8 .1z"/>
<path d="M201 181.6l.7 .1z"/>
<path d="M203.1 181.6l.7 .1z"/>
<path d="M204.6 181.6l.7 .1z"/>
<path d="M206.3 181.6l.8 .1z"/>
<path d="M208.2 181.6l.7 .1z"/>
<path d="M210.5 181.6l.8 .1z"/>
<path d="M211.7 181.6l.8 .1z"/>
<path d="M213.7 181.6l1.3 .1z"/>
<path d="M215.9 181.6l1.2 .1z"/>
<path d="M193.4 181.6h.8z"/>
<path d="M196.1 181.6h.7z"/>
<path d="M196.9 181.6h.6z"/>
<path d="M198.2 181.6h.7z"/>
<path d="M199.8 181.6h.7z"/>
<path d="M201 181.6h.7z"/>
<path d="M203.1 181.6h.7z"/>
<path d="M204.6 181.6h.7z"/>
<path d="M206.3 181.6h.8z"/>
<path d="M208.2 181.6h.7z"/>
<path d="M210.5 181.6h.9z"/>
<path d="M211.7 181.6h.8z"/>
<path d="M213.6 181.6h1.3z"/>
<path d="M215.7 181.6h1.3z"/>
<path d="M193.4 181.5l.8 .1z"/>
<path d="M196.1 181.5l.7 .1z"/>
<path d="M196.9 181.5l.7 .1z"/>
<path d="M198.2 181.5l.7 .1z"/>
<path d="M199.8 181.5l.7 .1z"/>
<path d="M201 181.5l.7 .1z"/>
<path d="M203 181.5l.8 .1z"/>
<path d="M204.6 181.5l.7 .1z"/>
<path d="M206.3 181.5l.8 .1z"/>
<path d="M208.2 181.5l.7 .1z"/>
<path d="M210.5 181.5l1 .1z"/>
<path d="M211.7 181.5l.8 .1z"/>
<path d="M213.4 181.5l1.4 .1z"/>
<path d="M215.6 181.5l1.3 .1z"/>
<path d="M193.4 181.5h.8z"/>
<path d="M196.1 181.5h.7z"/>
<path d="M196.9 181.5h.7z"/>
<path d="M198.2 181.5h.7z"/>
<path d="M199.8 181.5h.8z"/>
<path d="M201 181.5h.7z"/>
<path d="M203 181.5h.8z"/>
<path d="M204.6 181.5h.7z"/>
<path d="M206.3 181.5h.8z"/>
<path d="M208.2 181.5h.7z"/>
<path d="M210.5 181.5h1z"/>
<path d="M211.7 181.5h.7z"/>
<path d="M213.3 181.5h1.3z"/>
<path d="M215.5 181.5h1.3z"/>
<path d="M193.4 181.4l.8 .1z"/>
<path d="M196.1 181.4l.6 .1z"/>
<path d="M197 181.4l.5 .1z"/>
<path d="M198.2 181.4l.7 .1z"/>
<path d="M199.8 181.4l.8 .1z"/>
<path d="M201 181.4l.7 .1z"/>
<path d="M203 181.4l.8 .1z"/>
<path d="M204.6 181.4l.7 .1z"/>
<path d="M206.3 181.4l.8 .1z"/>
<path d="M208.2 181.4l.7 .1z"/>
<path d="M210.5 181.4l1.1 .1z"/>
<path d="M211.6 181.4l.8 .1z"/>
<path d="M213.2 181.4l1.3 .1z"/>
<path d="M215.3 181.4l1.3 .1z"/>
<path d="M193.4 181.4h.8z"/>
<path d="M196.1 181.4h.6z"/>
<path d="M196.9 181.4h.7z"/>
<path d="M198.2 181.4h.7z"/>
<path d="M199.8 181.4h.8z"/>
<path d="M201 181.4h.7z"/>
<path d="M203 181.4h.8z"/>
<path d="M204.6 181.4h.7z"/>
<path d="M206.3 181.4h.8z"/>
<path d="M208.2 181.4h.7z"/>
<path d="M210.5 181.4h1.9z"/>
<path d="M213.2 181.4h1.2z"/>
<path d="M215.3 181.4h1.2z"/>
<path d="M193.4 181.3l1.9 .1z"/>
<path d="M196 181.3l.7 .1z"/>
<path d="M196.9 181.3l.7 .1z"/>
<path d="M198.2 181.3l.7 .1z"/>
<path d="M199.8 181.3l.8 .1z"/>
<path d="M201 181.3l.7 .1z"/>
<path d="M203 181.3l.8 .1z"/>
<path d="M204.6 181.3l.7 .1z"/>
<path d="M206.3 181.3l.8 .1z"/>
<path d="M208.2 181.3l1.8 .1z"/>
<path d="M210.5 181.3l1.8 .1z"/>
<path d="M213.2 181.3l1 .1z"/>
<path d="M215.3 181.3l1 .1z"/>
<path d="M193.4 181.3h1.9z"/>
<path d="M196 181.3h.7z"/>
<path d="M197 181.3h.6z"/>
<path d="M198.1 181.3h.8z"/>
<path d="M199.8 181.3h.8z"/>
<path d="M201 181.3h.7z"/>
<path d="M203 181.3h.8z"/>
<path d="M204.6 181.3h.7z"/>
<path d="M206.3 181.3h.8z"/>
<path d="M208.2 181.3h1.8z"/>
<path d="M210.5 181.3h1.8z"/>
<path d="M213.2 181.3h.9z"/>
<path d="M215.3 181.3h1z"/>
<path d="M193.4 181.2l1.9 .1z"/>
<path d="M196 181.2l.7 .1z"/>
<path d="M197 181.2l.7 .1z"/>
<path d="M198.1 181.2l.8 .1z"/>
<path d="M199.8 181.2l.8 .1z"/>
<path d="M201 181.2l.7 .1z"/>
<path d="M203 181.2l.8 .1z"/>
<path d="M204.6 181.2l.7 .1z"/>
<path d="M206.3 181.2l.8 .1z"/>
<path d="M208.2 181.2l1.8 .1z"/>
<path d="M210.5 181.2l1.8 .1z"/>
<path d="M213.2 181.2l.7 .1z"/>
<path d="M215.3 181.2l.8 .1z"/>
<path d="M193.4 181.2h1.9z"/>
<path d="M196 181.2h.7z"/>
<path d="M197 181.2h.7z"/>
<path d="M198.1 181.2h.8z"/>
<path d="M199.8 181.2h.8z"/>
<path d="M201 181.2h.7z"/>
<path d="M203 181.2h.8z"/>
<path d="M204.6 181.2h.7z"/>
<path d="M206.3 181.2h.8z"/>
<path d="M208.2 181.2h1.8z"/>
<path d="M210.5 181.2h1.7z"/>
<path d="M213.2 181.2h.8z"/>
<path d="M215.3 181.2h.8z"/>
<path d="M193.4 181.1l1.9 .1z"/>
<path d="M196 181.1l.6 .1z"/>
<path d="M197 181.1l.7 .1z"/>
<path d="M198.1 181.1l.8 .1z"/>
<path d="M199.8 181.1l.8 .1z"/>
<path d="M201 181.1l.7 .1z"/>
<path d="M203 181.1l.8 .1z"/>
<path d="M204.6 181.1l.7 .1z"/>
<path d="M206.3 181.1l.8 .1z"/>
<path d="M208.2 181.1l1.8 .1z"/>
<path d="M210.5 181.1l1.7 .1z"/>
<path d="M213.2 181.1l.9 .1z"/>
<path d="M215.3 181.1l1 .1z"/>
<path d="M193.4 181.1h1.9z"/>
<path d="M195.9 181.1h.7z"/>
<path d="M197 181.1h.7z"/>
<path d="M198.2 181.1h.7z"/>
<path d="M199.8 181.1h.8z"/>
<path d="M201 181.1h.7z"/>
<path d="M203 181.1h.8z"/>
<path d="M204.6 181.1h.7z"/>
<path d="M206.3 181.1h.8z"/>
<path d="M208.2 181.1h1.8z"/>
<path d="M210.5 181.1h1.7z"/>
<path d="M213.2 181.1h1z"/>
<path d="M215.3 181.1h1.1z"/>
<path d="M193.4 181l1.9 .1z"/>
<path d="M195.9 181l.7 .1z"/>
<path d="M197 181l.7 .1z"/>
<path d="M198.2 181l.7 .1z"/>
<path d="M199.8 181l.8 .1z"/>
<path d="M201 181l.7 .1z"/>
<path d="M203 181l.8 .1z"/>
<path d="M204.6 181l.7 .1z"/>
<path d="M206.3 181l.8 .1z"/>
<path d="M208.2 181l1.8 .1z"/>
<path d="M210.5 181l1.7 .1z"/>
<path d="M213.2 181l1.2 .1z"/>
<path d="M215.3 181l1.3 .1z"/>
<path d="M193.4 181h1.9z"/>
<path d="M195.9 181h.7z"/>
<path d="M197.1 181h.7z"/>
<path d="M198.2 181h.7z"/>
<path d="M199.8 181h.8z"/>
<path d="M201 181h.7z"/>
<path d="M203 181h.8z"/>
<path d="M204.6 181h.7z"/>
<path d="M206.3 181h.8z"/>
<path d="M208.2 181h1.8z"/>
<path d="M210.5 181h1.6z"/>
<path d="M213.2 181h1.3z"/>
<path d="M215.4 181h1.2z"/>
<path d="M193.4 180.9l.8 .1z"/>
<path d="M195.9 180.9l.7 .1z"/>
<path d="M197.1 180.9l.7 .1z"/>
<path d="M198.2 180.9l.7 .1z"/>
<path d="M199.8 180.9l.8 .1z"/>
<path d="M201 180.9l.7 .1z"/>
<path d="M203 180.9l.8 .1z"/>
<path d="M204.6 180.9l.7 .1z"/>
<path d="M206.3 180.9l.8 .1z"/>
<path d="M208.2 180.9l.7 .1z"/>
<path d="M210.5 180.9l1.6 .1z"/>
<path d="M213.3 180.9l1.4 .1z"/>
<path d="M215.5 180.9l1.3 .1z"/>
<path d="M193.4 180.9h.8z"/>
<path d="M195.9 180.9h.7z"/>
<path d="M197.1 180.9h.7z"/>
<path d="M198.2 180.9h.7z"/>
<path d="M199.8 180.9h.7z"/>
<path d="M201 180.9h.7z"/>
<path d="M203 180.9h.8z"/>
<path d="M204.6 180.9h.7z"/>
<path d="M206.3 180.9h.8z"/>
<path d="M208.2 180.9h.7z"/>
<path d="M210.5 180.9h.7z"/>
<path d="M211.3 180.9h.9z"/>
<path d="M213.4 180.9h1.4z"/>
<path d="M215.6 180.9h1.4z"/>
<path d="M193.4 180.8h.8z"/>
<path d="M195.8 180.8h.7z"/>
<path d="M197.1 180.8h.7z"/>
<path d="M198.2 180.8h.7z"/>
<path d="M199.8 180.8h.7z"/>
<path d="M201 180.8h.7z"/>
<path d="M203 180.8h.8z"/>
<path d="M204.6 180.8h.7z"/>
<path d="M206.3 180.8h.8z"/>
<path d="M208.2 180.8h.7z"/>
<path d="M210.5 180.8h.7z"/>
<path d="M211.4 180.8h.8z"/>
<path d="M213.6 180.8h1.3z"/>
<path d="M215.8 180.8h1.3z"/>
<path d="M199.7 180.8h.8z"/>
<path d="M211.3 180.8h1z"/>
<path d="M213.7 180.8h1.3z"/>
<path d="M215.9 180.8h1.2z"/>
<path d="M193.4 180.7l.8 .1z"/>
<path d="M195.8 180.7l.7 .1z"/>
<path d="M197.1 180.7l.8 .1z"/>
<path d="M198.2 180.7l.8 .1z"/>
<path d="M199.7 180.7l.8 .1z"/>
<path d="M201 180.7l.7 .1z"/>
<path d="M203 180.7l.8 .1z"/>
<path d="M204.6 180.7l.7 .1z"/>
<path d="M206.3 180.7l.8 .1z"/>
<path d="M208.2 180.7l.7 .1z"/>
<path d="M210.5 180.7l.7 .1z"/>
<path d="M211.4 180.7l.9 .1z"/>
<path d="M213.9 180.7l1.1 .1z"/>
<path d="M216 180.7l1.2 .1z"/>
<path d="M193.4 180.7h.8z"/>
<path d="M195.8 180.7h.7z"/>
<path d="M197.2 180.7h.7z"/>
<path d="M198.3 180.7h.7z"/>
<path d="M199.6 180.7h.8z"/>
<path d="M201 180.7h.7z"/>
<path d="M203 180.7h.8z"/>
<path d="M204.6 180.7h.7z"/>
<path d="M206.3 180.7h.8z"/>
<path d="M208.2 180.7h.7z"/>
<path d="M210.5 180.7h.7z"/>
<path d="M211.5 180.7h.9z"/>
<path d="M214 180.7h1z"/>
<path d="M216.1 180.7h1z"/>
<path d="M193.4 180.6l.8 .1z"/>
<path d="M195.8 180.6l.7 .1z"/>
<path d="M197.2 180.6l.7 .1z"/>
<path d="M198.3 180.6l.8 .1z"/>
<path d="M199.5 180.6l.9 .1z"/>
<path d="M201 180.6l.7 .1z"/>
<path d="M203 180.6l.8 .1z"/>
<path d="M204.6 180.6l.7 .1z"/>
<path d="M205.6 180.6l2.2 .1z"/>
<path d="M208.2 180.6l.7 .1z"/>
<path d="M210.5 180.6l.7 .1z"/>
<path d="M211.5 180.6l.9 .1z"/>
<path d="M214.1 180.6l.9 .1z"/>
<path d="M216.3 180.6l.8 .1z"/>
<path d="M193.4 180.6h1.9z"/>
<path d="M195.7 180.6h.8z"/>
<path d="M197.2 180.6h.7z"/>
<path d="M198.3 180.6h2.1z"/>
<path d="M201 180.6h.7z"/>
<path d="M203 180.6h.8z"/>
<path d="M204.6 180.6h.7z"/>
<path d="M205.6 180.6h2.2z"/>
<path d="M208.2 180.6h1.8z"/>
<path d="M210.5 180.6h.7z"/>
<path d="M211.6 180.6h.9z"/>
<path d="M214.2 180.6h.8z"/>
<path d="M216.4 180.6h.7z"/>
<path d="M193.4 180.5l2 .1z"/>
<path d="M195.7 180.5l.7 .1z"/>
<path d="M197.2 180.5l.7 .1z"/>
<path d="M198.3 180.5l2 .1z"/>
<path d="M201 180.5l.7 .1z"/>
<path d="M203 180.5l.8 .1z"/>
<path d="M204.6 180.5l.7 .1z"/>
<path d="M205.6 180.5l2.2 .1z"/>
<path d="M208.2 180.5l1.9 .1z"/>
<path d="M210.5 180.5l.7 .1z"/>
<path d="M211.6 180.5l.9 .1z"/>
<path d="M214.4 180.5l.6 .1z"/>
<path d="M216.6 180.5l.5 .1z"/>
<path d="M193.4 180.5h2z"/>
<path d="M195.7 180.5h.7z"/>
<path d="M197.3 180.5h.7z"/>
<path d="M198.4 180.5h1.9z"/>
<path d="M201 180.5h.7z"/>
<path d="M203 180.5h.8z"/>
<path d="M204.6 180.5h.7z"/>
<path d="M205.6 180.5h2.2z"/>
<path d="M208.2 180.5h1.9z"/>
<path d="M210.5 180.5h.7z"/>
<path d="M211.7 180.5h.9z"/>
<path d="M214.5 180.5h.5z"/>
<path d="M216.6 180.5h.5z"/>
<path d="M193.4 180.4h2z"/>
<path d="M195.7 180.4h.7z"/>
<path d="M197.3 180.4h.7z"/>
<path d="M198.4 180.4h1.9z"/>
<path d="M201 180.4h.7z"/>
<path d="M203 180.4h.8z"/>
<path d="M204.6 180.4h.7z"/>
<path d="M205.6 180.4h2.2z"/>
<path d="M208.2 180.4h1.9z"/>
<path d="M210.5 180.4h.7z"/>
<path d="M211.7 180.4h.9z"/>
<path d="M214.6 180.4h.4z"/>
<path d="M216.8 180.4h.3z"/>
<path d="M198.5 180.4h1.7z"/>
<path d="M211.8 180.4h.9z"/>
<path d="M214.8 180.4h.2z"/>
<path d="M216.9 180.4h.2z"/>
<path d="M193.4 180.3h2z"/>
<path d="M195.6 180.3h.8z"/>
<path d="M197.3 180.3h.7z"/>
<path d="M198.5 180.3h1.7z"/>
<path d="M201 180.3h.7z"/>
<path d="M203 180.3h.8z"/>
<path d="M204.6 180.3h.7z"/>
<path d="M205.6 180.3h2.2z"/>
<path d="M208.2 180.3h1.9z"/>
<path d="M210.5 180.3h.7z"/>
<path d="M211.8 180.3h.9z"/>
<path d="M198.6 180.3h1.5z"/>
<path d="M211.9 180.3h.9z"/>
<path d="M193.4 180.2l2 .1z"/>
<path d="M195.6 180.2l.7 .1z"/>
<path d="M197.3 180.2l.8 .1z"/>
<path d="M198.7 180.2l1.3 .1z"/>
<path d="M201 180.2l.7 .1z"/>
<path d="M203 180.2l.8 .1z"/>
<path d="M204.6 180.2l.7 .1z"/>
<path d="M205.6 180.2l2.2 .1z"/>
<path d="M208.2 180.2l1.9 .1z"/>
<path d="M210.5 180.2l.7 .1z"/>
<path d="M211.9 180.2l1 .1z"/>
<path d="M193.4 180.1l2 .1z"/>
<path d="M195.6 180.1l.7 .1z"/>
<path d="M197.3 180.1l.8 .1z"/>
<path d="M198.8 180.1l1.1 .1z"/>
<path d="M201 180.1l.7 .1z"/>
<path d="M203 180.1l.8 .1z"/>
<path d="M204.6 180.1l.7 .1z"/>
<path d="M205.6 180.1l2.2 .1z"/>
<path d="M208.2 180.1l1.9 .1z"/>
<path d="M210.5 180.1l.7 .1z"/>
<path d="M211.9 180.1l1 .1z"/>
<path d="M193.4 180.1h1.9z"/>
<path d="M195.6 180.1h.7z"/>
<path d="M197.4 180.1h.7z"/>
<path d="M198.9 180.1h.8z"/>
<path d="M201 180.1h.7z"/>
<path d="M203.1 180.1h.7z"/>
<path d="M204.6 180.1h.7z"/>
<path d="M205.6 180.1h2.2z"/>
<path d="M208.2 180.1h1.8z"/>
<path d="M210.5 180.1h.7z"/>
<path d="M212 180.1h.9z"/>
<path d="M193.4 179.9h23.6z"/>
<path d="M193.4 179.9h23.7z"/>
<path d="M211.4 179.7h.6z"/>
<path d="M212.5 179.7h1.2z"/>
<path d="M206.4 179.6l.3 .1z"/>
<path d="M207.1 179.6l.4 .1z"/>
<path d="M210.6 179.6l.5 .1z"/>
<path d="M211.2 179.6l.8 .1z"/>
<path d="M212.5 179.6l1.3 .1z"/>
<path d="M206 179.6h.1z"/>
<path d="M206.3 179.6h1z"/>
<path d="M210.6 179.6h1.4z"/>
<path d="M212.5 179.6h.1z"/>
<path d="M202.7 179.5l1.3 .1z"/>
<path d="M205.1 179.5l.3 .1z"/>
<path d="M205.6 179.5l.4 .1z"/>
<path d="M206.3 179.5l.8 .1z"/>
<path d="M210.6 179.5l1.4 .1z"/>
<path d="M195 179.5h1.1z"/>
<path d="M199.5 179.5h.3z"/>
<path d="M202.7 179.5h.7z"/>
<path d="M205.1 179.5h.7z"/>
<path d="M206.3 179.5h.2z"/>
<path d="M210.6 179.5h1.3z"/>
<path d="M194.1 179.5h.5z"/>
<path d="M196.5 179.5h.5z"/>
<path d="M199.5 179.5h.4z"/>
<path d="M201.5 179.5h.3z"/>
<path d="M202.7 179.5h.4z"/>
<path d="M205 179.5h.3z"/>
<path d="M205.5 179.5h.1z"/>
<path d="M208.6 179.5h.4z"/>
<path d="M210.7 179.5h1z"/>
<path d="M194 179.4h.5z"/>
<path d="M194.9 179.4h.2z"/>
<path d="M196.6 179.4h.3z"/>
<path d="M198.2 179.4h.2z"/>
<path d="M199.5 179.4h.1z"/>
<path d="M201.4 179.4h.2z"/>
<path d="M202.7 179.4h.3z"/>
<path d="M205.1 179.4h.2z"/>
<path d="M206.3 179.4h.3z"/>
<path d="M208.5 179.4h.5z"/>
<path d="M210.7 179.4h.9z"/>
<path d="M212.5 179.4h.1z"/>
<path d="M194 179.3l.2 .1z"/>
<path d="M194.9 179.3l.2 .1z"/>
<path d="M196.6 179.3l.3 .1z"/>
<path d="M198.1 179.3l.4 .1z"/>
<path d="M201.4 179.3l.2 .1z"/>
<path d="M202.7 179.3l.2 .1z"/>
<path d="M205.1 179.3l.2 .1z"/>
<path d="M206.4 179.3l.2 .1z"/>
<path d="M208.5 179.3l.5 .1z"/>
<path d="M210.7 179.3l.7 .1z"/>
<path d="M212.5 179.3l.2 .1z"/>
<path d="M194 179.3h.2z"/>
<path d="M194.9 179.3h.2z"/>
<path d="M196.7 179.3h.1z"/>
<path d="M198.1 179.3h.3z"/>
<path d="M199.5 179.3h.1z"/>
<path d="M202.8 179.3h.1z"/>
<path d="M205.1 179.3h.2z"/>
<path d="M206.4 179.3h.3z"/>
<path d="M208.4 179.3h.5z"/>
<path d="M210.7 179.3h.6z"/>
<path d="M212.5 179.3h.2z"/>
<path d="M193.9 179.2l.2 .1z"/>
<path d="M194.9 179.2l.2 .1z"/>
<path d="M198.2 179.2l.2 .1z"/>
<path d="M201.3 179.2l.1 .1z"/>
<path d="M202.8 179.2l.1 .1z"/>
<path d="M205.1 179.2l.3 .1z"/>
<path d="M206.4 179.2l.3 .1z"/>
<path d="M208.4 179.2l.4 .1z"/>
<path d="M210.7 179.2l.5 .1z"/>
<path d="M212.6 179.2l.1 .1z"/>
<path d="M193.9 179.2h.2z"/>
<path d="M194.9 179.2h.2z"/>
<path d="M198.2 179.2h.2z"/>
<path d="M199.5 179.2h.2z"/>
<path d="M201.2 179.2h.2z"/>
<path d="M202.8 179.2h.2z"/>
<path d="M205.1 179.2h.3z"/>
<path d="M206.4 179.2h.3z"/>
<path d="M208.3 179.2h.4z"/>
<path d="M210.7 179.2h.5z"/>
<path d="M193.8 179.1l.3 .1z"/>
<path d="M194.9 179.1l.2 .1z"/>
<path d="M198.2 179.1l.2 .1z"/>
<path d="M199.5 179.1l.2 .1z"/>
<path d="M201.1 179.1l.2 .1z"/>
<path d="M202.8 179.1l.2 .1z"/>
<path d="M205.1 179.1l.3 .1z"/>
<path d="M206.4 179.1l.3 .1z"/>
<path d="M208.3 179.1l.4 .1z"/>
<path d="M210.7 179.1l.5 .1z"/>
<path d="M193.8 179.1h.2z"/>
<path d="M194.9 179.1h.2z"/>
<path d="M198.2 179.1h.3z"/>
<path d="M199.5 179.1h.2z"/>
<path d="M201 179.1h.3z"/>
<path d="M202.8 179.1h.2z"/>
<path d="M205.1 179.1h.3z"/>
<path d="M206.4 179.1h.3z"/>
<path d="M208.2 179.1h.5z"/>
<path d="M210.6 179.1h.4z"/>
<path d="M212.5 179.1h.2z"/>
<path d="M193.7 179l.3 .1z"/>
<path d="M194.9 179l.2 .1z"/>
<path d="M198.2 179l.2 .1z"/>
<path d="M199.5 179l.2 .1z"/>
<path d="M201 179l.2 .1z"/>
<path d="M202.8 179l.2 .1z"/>
<path d="M205.1 179l.3 .1z"/>
<path d="M206.4 179l.3 .1z"/>
<path d="M208 179l.7 .1z"/>
<path d="M210.6 179l.4 .1z"/>
<path d="M212.5 179l.2 .1z"/>
<path d="M193.7 179h.3z"/>
<path d="M194.9 179h.2z"/>
<path d="M198.2 179h.2z"/>
<path d="M199.5 179h.2z"/>
<path d="M200.9 179h.2z"/>
<path d="M202.8 179h.2z"/>
<path d="M205.1 179h.2z"/>
<path d="M206.4 179h.2z"/>
<path d="M208 179h.6z"/>
<path d="M210.6 179h.4z"/>
<path d="M212.5 179h.2z"/>
<path d="M193.7 178.9l.3 .1z"/>
<path d="M194.9 178.9l.2 .1z"/>
<path d="M198.3 178.9l.2 .1z"/>
<path d="M199.5 178.9l.2 .1z"/>
<path d="M200.9 178.9l.2 .1z"/>
<path d="M202.8 178.9l.2 .1z"/>
<path d="M205.1 178.9l.2 .1z"/>
<path d="M206.4 178.9l.2 .1z"/>
<path d="M208 178.9l.6 .1z"/>
<path d="M210.6 178.9l.5 .1z"/>
<path d="M212.5 178.9l.2 .1z"/>
<path d="M193.7 178.9h.3z"/>
<path d="M194.9 178.9h.2z"/>
<path d="M198.3 178.9h.2z"/>
<path d="M199.5 178.9h.2z"/>
<path d="M200.9 178.9h.3z"/>
<path d="M202.8 178.9h.2z"/>
<path d="M205.1 178.9h.2z"/>
<path d="M206.4 178.9h.2z"/>
<path d="M208 178.9h.6z"/>
<path d="M210.6 178.9h.5z"/>
<path d="M212.5 178.9h.2z"/>
<path d="M193.8 178.8l.3 .1z"/>
<path d="M194.9 178.8l.2 .1z"/>
<path d="M198.3 178.8l.2 .1z"/>
<path d="M199.5 178.8l.2 .1z"/>
<path d="M201 178.8l.2 .1z"/>
<path d="M202.8 178.8l.2 .1z"/>
<path d="M205.1 178.8l.2 .1z"/>
<path d="M206.3 178.8l.2 .1z"/>
<path d="M207.9 178.8l.7 .1z"/>
<path d="M208.6 178.8l.2 .1z"/>
<path d="M210.6 178.8l.5 .1z"/>
<path d="M212.5 178.8l.2 .1z"/>
<path d="M193.8 178.8h.3z"/>
<path d="M194.9 178.8h.2z"/>
<path d="M198.3 178.8h.2z"/>
<path d="M199.4 178.8h.2z"/>
<path d="M201 178.8h.3z"/>
<path d="M202.8 178.8h.2z"/>
<path d="M205.1 178.8h.2z"/>
<path d="M206.3 178.8h.2z"/>
<path d="M207.9 178.8h1z"/>
<path d="M210.6 178.8h.5z"/>
<path d="M212.5 178.8h.2z"/>
<path d="M193.9 178.7l.2 .1z"/>
<path d="M194.9 178.7l.2 .1z"/>
<path d="M197.2 178.7l.3 .1z"/>
<path d="M198.3 178.7l.3 .1z"/>
<path d="M199.4 178.7l.2 .1z"/>
<path d="M201.1 178.7l.2 .1z"/>
<path d="M202.8 178.7l.2 .1z"/>
<path d="M205.1 178.7l.2 .1z"/>
<path d="M206.3 178.7l.2 .1z"/>
<path d="M208 178.7l.9 .1z"/>
<path d="M210.6 178.7l.5 .1z"/>
<path d="M212.5 178.7l.2 .1z"/>
<path d="M194 178.7h.2z"/>
<path d="M194.9 178.7h.2z"/>
<path d="M196.5 178.7h.2z"/>
<path d="M197.2 178.7h.2z"/>
<path d="M198.3 178.7h.3z"/>
<path d="M199.4 178.7h.2z"/>
<path d="M201.1 178.7h.3z"/>
<path d="M202.8 178.7h.2z"/>
<path d="M205.1 178.7h.2z"/>
<path d="M206.3 178.7h.2z"/>
<path d="M208.1 178.7h.8z"/>
<path d="M210.6 178.7h.5z"/>
<path d="M212.5 178.7h.2z"/>
<path d="M194 178.6l.3 .1z"/>
<path d="M195 178.6l.2 .1z"/>
<path d="M196.5 178.6l.1 .1z"/>
<path d="M197.2 178.6l.2 .1z"/>
<path d="M198.3 178.6l.3 .1z"/>
<path d="M199.4 178.6l.2 .1z"/>
<path d="M201.1 178.6l.3 .1z"/>
<path d="M202.7 178.6l.3 .1z"/>
<path d="M205.1 178.6l.2 .1z"/>
<path d="M206.2 178.6l.3 .1z"/>
<path d="M208.1 178.6l.9 .1z"/>
<path d="M210.5 178.6l.6 .1z"/>
<path d="M212.5 178.6l.2 .1z"/>
<path d="M194.1 178.6h.3z"/>
<path d="M195 178.6h.2z"/>
<path d="M196.4 178.6h.2z"/>
<path d="M198.3 178.6h.3z"/>
<path d="M199.4 178.6h.2z"/>
<path d="M201.2 178.6h.3z"/>
<path d="M202.7 178.6h.2z"/>
<path d="M205.1 178.6h.2z"/>
<path d="M206.2 178.6h.2z"/>
<path d="M208.2 178.6h.8z"/>
<path d="M210.6 178.6h.5z"/>
<path d="M212.5 178.6h.2z"/>
<path d="M194.1 178.5l.3 .1z"/>
<path d="M195 178.5l.2 .1z"/>
<path d="M196.4 178.5l.2 .1z"/>
<path d="M198.3 178.5l.3 .1z"/>
<path d="M199.4 178.5l.2 .1z"/>
<path d="M201.3 178.5l.2 .1z"/>
<path d="M202.7 178.5l.2 .1z"/>
<path d="M205.1 178.5l.2 .1z"/>
<path d="M206.2 178.5l.2 .1z"/>
<path d="M208.2 178.5l.8 .1z"/>
<path d="M210.6 178.5l.5 .1z"/>
<path d="M212.5 178.5l.2 .1z"/>
<path d="M194.2 178.5h.3z"/>
<path d="M195 178.5h.2z"/>
<path d="M196.3 178.5h.2z"/>
<path d="M198.3 178.5h.3z"/>
<path d="M199.4 178.5h.1z"/>
<path d="M201.3 178.5h.2z"/>
<path d="M202.7 178.5h.2z"/>
<path d="M205.1 178.5h.2z"/>
<path d="M206.2 178.5h.2z"/>
<path d="M208.2 178.5h.9z"/>
<path d="M210.6 178.5h.5z"/>
<path d="M212.5 178.5h.2z"/>
<path d="M194.2 178.4l.3 .1z"/>
<path d="M195 178.4l.2 .1z"/>
<path d="M196.3 178.4l.1 .1z"/>
<path d="M198.3 178.4l.3 .1z"/>
<path d="M199.4 178.4l.1 .1z"/>
<path d="M201.3 178.4l.2 .1z"/>
<path d="M202.7 178.4l.2 .1z"/>
<path d="M205.1 178.4l.2 .1z"/>
<path d="M206.2 178.4l.2 .1z"/>
<path d="M208.3 178.4l.8 .1z"/>
<path d="M210.5 178.4l.6 .1z"/>
<path d="M212.5 178.4l.2 .1z"/>
<path d="M194.3 178.4h.3z"/>
<path d="M194.9 178.4h.3z"/>
<path d="M196.2 178.4h.2z"/>
<path d="M198.3 178.4h.3z"/>
<path d="M199.3 178.4h.2z"/>
<path d="M201.4 178.4h.1z"/>
<path d="M202.7 178.4h.2z"/>
<path d="M205.1 178.4h.2z"/>
<path d="M206.1 178.4h.3z"/>
<path d="M208.3 178.4h.9z"/>
<path d="M210.5 178.4h.6z"/>
<path d="M212.5 178.4h.2z"/>
<path d="M194.3 178.3l.8 .1z"/>
<path d="M196.2 178.3l.1 .1z"/>
<path d="M197 178.3l.2 .1z"/>
<path d="M198.3 178.3l.2 .1z"/>
<path d="M199.3 178.3l.2 .1z"/>
<path d="M201.4 178.3l.1 .1z"/>
<path d="M202.7 178.3l.2 .1z"/>
<path d="M205.1 178.3l.1 .1z"/>
<path d="M206.1 178.3l.3 .1z"/>
<path d="M208.3 178.3l.9 .1z"/>
<path d="M210.5 178.3l.6 .1z"/>
<path d="M212.5 178.3l.2 .1z"/>
<path d="M194.3 178.3h.7z"/>
<path d="M196.1 178.3h.2z"/>
<path d="M197 178.3h.1z"/>
<path d="M198.3 178.3h.2z"/>
<path d="M199.3 178.3h.2z"/>
<path d="M201.4 178.3h.2z"/>
<path d="M202.7 178.3h.2z"/>
<path d="M205.1 178.3h.1z"/>
<path d="M206.1 178.3h.2z"/>
<path d="M208.4 178.3h.8z"/>
<path d="M210.6 178.3h.5z"/>
<path d="M212.5 178.3h.2z"/>
<path d="M194.3 178.2l.6 .1z"/>
<path d="M196.1 178.2l.1 .1z"/>
<path d="M196.9 178.2l.2 .1z"/>
<path d="M198.3 178.2l.2 .1z"/>
<path d="M199.3 178.2l.2 .1z"/>
<path d="M201.4 178.2l.2 .1z"/>
<path d="M202.7 178.2l.2 .1z"/>
<path d="M205.1 178.2l.1 .1z"/>
<path d="M206.1 178.2l.2 .1z"/>
<path d="M208.4 178.2l.9 .1z"/>
<path d="M210.5 178.2l.6 .1z"/>
<path d="M212.5 178.2l.2 .1z"/>
<path d="M194.2 178.2h.6z"/>
<path d="M196 178.2h.2z"/>
<path d="M196.6 178.2h.4z"/>
<path d="M198.3 178.2h.2z"/>
<path d="M199.3 178.2h.2z"/>
<path d="M201.4 178.2h.2z"/>
<path d="M202.8 178.2h.2z"/>
<path d="M205.1 178.2h.1z"/>
<path d="M206.1 178.2h.2z"/>
<path d="M208.4 178.2h.9z"/>
<path d="M210.5 178.2h.6z"/>
<path d="M212.5 178.2h.2z"/>
<path d="M194.2 178.1l.5 .1z"/>
<path d="M196 178.1l.1 .1z"/>
<path d="M196.5 178.1l.5 .1z"/>
<path d="M198.4 178.1l.2 .1z"/>
<path d="M199.3 178.1l.2 .1z"/>
<path d="M201.4 178.1l.2 .1z"/>
<path d="M202.8 178.1l.2 .1z"/>
<path d="M205.1 178.1l.2 .1z"/>
<path d="M206.1 178.1l.2 .1z"/>
<path d="M208.5 178.1l.9 .1z"/>
<path d="M210.5 178.1l.6 .1z"/>
<path d="M212.5 178.1l.2 .1z"/>
<path d="M194.1 178.1h.5z"/>
<path d="M195.9 178.1h.2z"/>
<path d="M196.6 178.1h.3z"/>
<path d="M198.4 178.1h.2z"/>
<path d="M199.3 178.1h.2z"/>
<path d="M201.5 178.1h.2z"/>
<path d="M202.8 178.1h.2z"/>
<path d="M205.1 178.1h.2z"/>
<path d="M206.1 178.1h.2z"/>
<path d="M208.5 178.1h.9z"/>
<path d="M210.5 178.1h.6z"/>
<path d="M212.5 178.1h.2z"/>
<path d="M194.1 178l.3 .1z"/>
<path d="M195.9 178l.1 .1z"/>
<path d="M198.4 178l.2 .1z"/>
<path d="M199.3 178l.2 .1z"/>
<path d="M201.5 178l.3 .1z"/>
<path d="M202.8 178l.3 .1z"/>
<path d="M205.1 178l.2 .1z"/>
<path d="M206.1 178l.2 .1z"/>
<path d="M208.6 178l.8 .1z"/>
<path d="M210.5 178l.6 .1z"/>
<path d="M212.5 178l.2 .1z"/>
<path d="M194.1 178h.3z"/>
<path d="M195.9 178h.1z"/>
<path d="M198.4 178h.3z"/>
<path d="M199.3 178h.2z"/>
<path d="M201.5 178h.4z"/>
<path d="M202.8 178h.3z"/>
<path d="M205.1 178h.3z"/>
<path d="M206.1 178h.2z"/>
<path d="M208.6 178h.9z"/>
<path d="M210.5 178h.6z"/>
<path d="M212.5 178h.2z"/>
<path d="M194 177.9l.3 .1z"/>
<path d="M195.9 177.9l.1 .1z"/>
<path d="M198.5 177.9l.2 .1z"/>
<path d="M199.3 177.9l.2 .1z"/>
<path d="M201.5 177.9l.5 .1z"/>
<path d="M202.9 177.9l.2 .1z"/>
<path d="M205.2 177.9l.2 .1z"/>
<path d="M206.1 177.9l.2 .1z"/>
<path d="M208.6 177.9l.9 .1z"/>
<path d="M210.5 177.9l.6 .1z"/>
<path d="M212.5 177.9l.2 .1z"/>
<path d="M194 177.9h.2z"/>
<path d="M195.9 177.9h.1z"/>
<path d="M198.5 177.9h.3z"/>
<path d="M199.3 177.9h.2z"/>
<path d="M201.7 177.9h.4z"/>
<path d="M202.9 177.9h.3z"/>
<path d="M205.2 177.9h.2z"/>
<path d="M206.1 177.9h.2z"/>
<path d="M208.7 177.9h.8z"/>
<path d="M210.5 177.9h.6z"/>
<path d="M212.5 177.9h.2z"/>
<path d="M194 177.8l.2 .1z"/>
<path d="M198.5 177.8l.4 .1z"/>
<path d="M199 177.8l.3 .1z"/>
<path d="M199.3 177.8l.2 .1z"/>
<path d="M201.7 177.8l.5 .1z"/>
<path d="M202.9 177.8l.3 .1z"/>
<path d="M205.2 177.8l.3 .1z"/>
<path d="M206.1 177.8l.3 .1z"/>
<path d="M208.7 177.8l.7 .1z"/>
<path d="M210.5 177.8l.6 .1z"/>
<path d="M212.4 177.8l.3 .1z"/>
<path d="M194 177.8h.2z"/>
<path d="M198.6 177.8h.7z"/>
<path d="M199.3 177.8h.2z"/>
<path d="M201.8 177.8h.5z"/>
<path d="M202.9 177.8h.3z"/>
<path d="M205.2 177.8h.3z"/>
<path d="M206.1 177.8h.3z"/>
<path d="M208.8 177.8h.6z"/>
<path d="M210.5 177.8h.6z"/>
<path d="M212.4 177.8h.3z"/>
<path d="M194 177.7l.2 .1z"/>
<path d="M198.6 177.7l.9 .1z"/>
<path d="M201.9 177.7l.5 .1z"/>
<path d="M202.9 177.7l.3 .1z"/>
<path d="M205.2 177.7l.4 .1z"/>
<path d="M206.1 177.7l.3 .1z"/>
<path d="M208.8 177.7l.7 .1z"/>
<path d="M210.5 177.7l.6 .1z"/>
<path d="M212.4 177.7l.3 .1z"/>
<path d="M194 177.7h.2z"/>
<path d="M198.7 177.7h.8z"/>
<path d="M201.9 177.7h.8z"/>
<path d="M202.9 177.7h.3z"/>
<path d="M205.3 177.7h.4z"/>
<path d="M206.1 177.7h.3z"/>
<path d="M208.8 177.7h.7z"/>
<path d="M210.5 177.7h.6z"/>
<path d="M212.4 177.7h.2z"/>
<path d="M212.9 177.7h.2z"/>
<path d="M194 177.6l.2 .1z"/>
<path d="M198.7 177.6l.8 .1z"/>
<path d="M202 177.6l.7 .1z"/>
<path d="M202.9 177.6l.3 .1z"/>
<path d="M205.3 177.6l.5 .1z"/>
<path d="M206.1 177.6l.3 .1z"/>
<path d="M208.9 177.6l.7 .1z"/>
<path d="M210.5 177.6l.6 .1z"/>
<path d="M212.4 177.6l.2 .1z"/>
<path d="M194 177.6h.2z"/>
<path d="M198.7 177.6h.8z"/>
<path d="M202 177.6h.7z"/>
<path d="M202.9 177.6h.3z"/>
<path d="M205.3 177.6h.6z"/>
<path d="M206.1 177.6h.3z"/>
<path d="M208.9 177.6h.7z"/>
<path d="M210.5 177.6h.6z"/>
<path d="M212.5 177.6h.1z"/>
<path d="M194 177.5h.2z"/>
<path d="M198.7 177.5h.8z"/>
<path d="M202 177.5h.7z"/>
<path d="M202.8 177.5h.4z"/>
<path d="M205.3 177.5h.6z"/>
<path d="M206.1 177.5h.2z"/>
<path d="M209 177.5h.6z"/>
<path d="M210.5 177.5h.6z"/>
<path d="M212.5 177.5h.4z"/>
<path d="M198.7 177.5h.7z"/>
<path d="M205.3 177.5h.7z"/>
<path d="M209 177.5h.5z"/>
<path d="M212.5 177.5h.5z"/>
<path d="M194 177.4l.2 .1z"/>
<path d="M198.7 177.4l.6 .1z"/>
<path d="M199.3 177.4l.2 .1z"/>
<path d="M202 177.4l.7 .1z"/>
<path d="M202.8 177.4l.3 .1z"/>
<path d="M205.3 177.4l.7 .1z"/>
<path d="M206.1 177.4l.2 .1z"/>
<path d="M209 177.4l.7 .1z"/>
<path d="M210.5 177.4l.6 .1z"/>
<path d="M212.5 177.4l.2 .1z"/>
<path d="M194 177.4h.2z"/>
<path d="M198.6 177.4h.6z"/>
<path d="M199.2 177.4h.3z"/>
<path d="M202 177.4h.7z"/>
<path d="M202.7 177.4h.4z"/>
<path d="M205.3 177.4h.9z"/>
<path d="M209.1 177.4h.6z"/>
<path d="M210.5 177.4h.6z"/>
<path d="M212.5 177.4h.1z"/>
<path d="M194.1 177.3l.2 .1z"/>
<path d="M198.6 177.3l.5 .1z"/>
<path d="M199.2 177.3l.3 .1z"/>
<path d="M202 177.3l1 .1z"/>
<path d="M205.4 177.3l.6 .1z"/>
<path d="M206 177.3l.2 .1z"/>
<path d="M209.1 177.3l.6 .1z"/>
<path d="M210.4 177.3l.6 .1z"/>
<path d="M212.9 177.3l.2 .1z"/>
<path d="M194.1 177.2l.2 .1z"/>
<path d="M198.6 177.2l.4 .1z"/>
<path d="M199.1 177.2l.4 .1z"/>
<path d="M201.9 177.2l.6 .1z"/>
<path d="M202.5 177.2l.4 .1z"/>
<path d="M205.4 177.2l.6 .1z"/>
<path d="M206 177.2l.2 .1z"/>
<path d="M209.2 177.2l.5 .1z"/>
<path d="M210.4 177.2l.6 .1z"/>
<path d="M212.4 177.2l.2 .1z"/>
<path d="M212.9 177.2l.2 .1z"/>
<path d="M194.1 177.2h.3z"/>
<path d="M198.6 177.2h.4z"/>
<path d="M199 177.2h.5z"/>
<path d="M201.9 177.2h.5z"/>
<path d="M202.5 177.2h.3z"/>
<path d="M205.4 177.2h.7z"/>
<path d="M209.2 177.2h.5z"/>
<path d="M210.3 177.2h.7z"/>
<path d="M212.9 177.2h.2z"/>
<path d="M194.2 177.2h.2z"/>
<path d="M198.6 177.2h.3z"/>
<path d="M198.9 177.2h.6z"/>
<path d="M201.9 177.2h.4z"/>
<path d="M202.4 177.2h.4z"/>
<path d="M205.4 177.2h.5z"/>
<path d="M194.2 177.1h.3z"/>
<path d="M198.5 177.1h.3z"/>
<path d="M198.9 177.1h.6z"/>
<path d="M201.9 177.1h.3z"/>
<path d="M202.3 177.1h.4z"/>
<path d="M205.4 177.1h.5z"/>
<path d="M209.2 177.1h.6z"/>
<path d="M210.2 177.1h.8z"/>
<path d="M212.5 177.1h.1z"/>
<path d="M212.9 177.1h.2z"/>
<path d="M194.3 177.1h.2z"/>
<path d="M198.8 177.1h.5z"/>
<path d="M201.8 177.1h.4z"/>
<path d="M202.2 177.1h.4z"/>
<path d="M205.4 177.1h.6z"/>
<path d="M212.5 177.1h.2z"/>
<path d="M194.4 177h.2z"/>
<path d="M198.5 177h.7z"/>
<path d="M201.8 177h.3z"/>
<path d="M202.2 177h.3z"/>
<path d="M205.4 177h.6z"/>
<path d="M209.2 177h.6z"/>
<path d="M210.2 177h.7z"/>
<path d="M198.5 177h.6z"/>
<path d="M202.1 177h.3z"/>
<path d="M205.4 177h.5z"/>
<path d="M210.1 177h.8z"/>
<path d="M194.5 176.9l.2 .1z"/>
<path d="M198.4 176.9l.3 .1z"/>
<path d="M198.7 176.9l.4 .1z"/>
<path d="M201.7 176.9l.3 .1z"/>
<path d="M202.1 176.9l.2 .1z"/>
<path d="M205.4 176.9l.6 .1z"/>
<path d="M209.2 176.9l.6 .1z"/>
<path d="M210.1 176.9l.8 .1z"/>
<path d="M212.6 176.9l.3 .1z"/>
<path d="M194.5 176.8l.3 .1z"/>
<path d="M198.4 176.8l.2 .1z"/>
<path d="M198.7 176.8l.3 .1z"/>
<path d="M201.7 176.8l.5 .1z"/>
<path d="M205.4 176.8l.6 .1z"/>
<path d="M209.2 176.8l.6 .1z"/>
<path d="M210.1 176.8l.8 .1z"/>
<path d="M212.6 176.8l.3 .1z"/>
<path d="M194.6 176.8h.3z"/>
<path d="M198.4 176.8h.2z"/>
<path d="M198.6 176.8h.4z"/>
<path d="M199.8 176.8h.1z"/>
<path d="M201.7 176.8h.5z"/>
<path d="M205.4 176.8h.4z"/>
<path d="M209.1 176.8h.7z"/>
<path d="M209.9 176.8h.9z"/>
<path d="M212.6 176.8h.5z"/>
<path d="M194.6 176.7l.3 .1z"/>
<path d="M198.4 176.7l.5 .1z"/>
<path d="M201.6 176.7l.5 .1z"/>
<path d="M205.4 176.7l.4 .1z"/>
<path d="M209.2 176.7l.6 .1z"/>
<path d="M209.9 176.7l.9 .1z"/>
<path d="M212.6 176.7l.5 .1z"/>
<path d="M194.8 176.7h.2z"/>
<path d="M198.4 176.7h.1z"/>
<path d="M198.6 176.7h.3z"/>
<path d="M199.4 176.7h.1z"/>
<path d="M201.6 176.7h.5z"/>
<path d="M203.4 176.7h.2z"/>
<path d="M205.4 176.7h.5z"/>
<path d="M209.2 176.7h1.6z"/>
<path d="M212.5 176.7h.7z"/>
<path d="M194.8 176.7h.3z"/>
<path d="M196.5 176.7h.2z"/>
<path d="M198.3 176.7h.2z"/>
<path d="M198.5 176.7h.4z"/>
<path d="M201.5 176.7h.5z"/>
<path d="M205.4 176.7h.4z"/>
<path d="M210.8 176.7h.2z"/>
<path d="M212.5 176.7h.2z"/>
<path d="M194.9 176.6h.3z"/>
<path d="M196.4 176.6h.4z"/>
<path d="M198.3 176.6h.5z"/>
<path d="M199.4 176.6h.1z"/>
<path d="M201.6 176.6h.3z"/>
<path d="M205.4 176.6h.4z"/>
<path d="M209.2 176.6h1.5z"/>
<path d="M212.5 176.6h.2z"/>
<path d="M195 176.6h.3z"/>
<path d="M196.3 176.6h.2z"/>
<path d="M196.7 176.6h.1z"/>
<path d="M195.1 176.5h.3z"/>
<path d="M198.3 176.5h.4z"/>
<path d="M199.4 176.5h.1z"/>
<path d="M201.5 176.5h.3z"/>
<path d="M205.4 176.5h.4z"/>
<path d="M209.2 176.5h1.5z"/>
<path d="M212.5 176.5h.2z"/>
<path d="M195.2 176.4l.3 .1z"/>
<path d="M198.3 176.4l.4 .1z"/>
<path d="M199.4 176.4l.1 .1z"/>
<path d="M201.5 176.4l.3 .1z"/>
<path d="M205.4 176.4l.5 .1z"/>
<path d="M209.2 176.4l1.4 .1z"/>
<path d="M212.5 176.4l.2 .1z"/>
<path d="M195.3 176.4h.3z"/>
<path d="M198.2 176.4h.5z"/>
<path d="M199.4 176.4h.1z"/>
<path d="M201.5 176.4h.3z"/>
<path d="M203.5 176.4h.2z"/>
<path d="M205.3 176.4h.4z"/>
<path d="M209.2 176.4h1.4z"/>
<path d="M212.5 176.4h.2z"/>
<path d="M195.4 176.3l.2 .1z"/>
<path d="M198.2 176.3l.4 .1z"/>
<path d="M199.3 176.3l.2 .1z"/>
<path d="M201.5 176.3l.3 .1z"/>
<path d="M203.6 176.3l.2 .1z"/>
<path d="M205.3 176.3l.3 .1z"/>
<path d="M209.2 176.3l1.3 .1z"/>
<path d="M212.5 176.3l.2 .1z"/>
<path d="M195.5 176.3h.2z"/>
<path d="M198.2 176.3h.4z"/>
<path d="M199.3 176.3h.2z"/>
<path d="M201.5 176.3h.2z"/>
<path d="M205.3 176.3h.3z"/>
<path d="M209.2 176.3h1.3z"/>
<path d="M212.5 176.3h.2z"/>
<path d="M195.6 176.2l.2 .1z"/>
<path d="M198.2 176.2l.4 .1z"/>
<path d="M199.3 176.2l.2 .1z"/>
<path d="M201.5 176.2l.2 .1z"/>
<path d="M203.8 176.2l.2 .1z"/>
<path d="M205.3 176.2l.3 .1z"/>
<path d="M209.2 176.2l1.3 .1z"/>
<path d="M212.5 176.2l.2 .1z"/>
<path d="M195.6 176.2h.2z"/>
<path d="M198.2 176.2h.3z"/>
<path d="M199.3 176.2h.2z"/>
<path d="M201.5 176.2h.2z"/>
<path d="M202.5 176.2h.2z"/>
<path d="M203.8 176.2h.2z"/>
<path d="M205.3 176.2h.2z"/>
<path d="M209.2 176.2h1.3z"/>
<path d="M212.5 176.2h.2z"/>
<path d="M195.7 176.1l.1 .1z"/>
<path d="M198.2 176.1l.3 .1z"/>
<path d="M199.3 176.1l.2 .1z"/>
<path d="M201.5 176.1l.2 .1z"/>
<path d="M203.8 176.1l.2 .1z"/>
<path d="M205.3 176.1l.2 .1z"/>
<path d="M209.2 176.1l1.3 .1z"/>
<path d="M212.5 176.1l.3 .1z"/>
<path d="M195.7 176.1h.2z"/>
<path d="M198.2 176.1h.3z"/>
<path d="M199.3 176.1h.2z"/>
<path d="M201.5 176.1h.2z"/>
<path d="M203.5 176.1h.2z"/>
<path d="M203.7 176.1h.2z"/>
<path d="M205.3 176.1h.2z"/>
<path d="M209.2 176.1h1.2z"/>
<path d="M212.5 176.1h.3z"/>
<path d="M195.8 176l.1 .1z"/>
<path d="M196.5 176l.2 .1z"/>
<path d="M198.2 176l.3 .1z"/>
<path d="M199.2 176l.3 .1z"/>
<path d="M201.5 176l.2 .1z"/>
<path d="M203.5 176l.3 .1z"/>
<path d="M205.2 176l.3 .1z"/>
<path d="M209.2 176l1.2 .1z"/>
<path d="M212.5 176l.3 .1z"/>
<path d="M195.8 176h.2z"/>
<path d="M198.2 176h.3z"/>
<path d="M199.3 176h.2z"/>
<path d="M201.5 176h.3z"/>
<path d="M203.1 176h.6z"/>
<path d="M205.2 176h.3z"/>
<path d="M209.2 176h1.2z"/>
<path d="M212.5 176h.3z"/>
<path d="M195.8 175.9l.2 .1z"/>
<path d="M198.3 175.9l.2 .1z"/>
<path d="M199.3 175.9l.2 .1z"/>
<path d="M201.5 175.9l.3 .1z"/>
<path d="M202.8 175.9l.8 .1z"/>
<path d="M205.2 175.9l.3 .1z"/>
<path d="M209.2 175.9l1.2 .1z"/>
<path d="M212.5 175.9l.3 .1z"/>
<path d="M195.9 175.9h.2z"/>
<path d="M198.3 175.9h.2z"/>
<path d="M199.3 175.9h.2z"/>
<path d="M201.5 175.9h.3z"/>
<path d="M202.7 175.9h.7z"/>
<path d="M205.2 175.9h.3z"/>
<path d="M209.2 175.9h1.1z"/>
<path d="M212.5 175.9h.3z"/>
<path d="M196 175.8l.1 .1z"/>
<path d="M198.3 175.8l.2 .1z"/>
<path d="M199.3 175.8l.2 .1z"/>
<path d="M201.4 175.8l.5 .1z"/>
<path d="M202.6 175.8l.5 .1z"/>
<path d="M205.2 175.8l.3 .1z"/>
<path d="M209.2 175.8l1 .1z"/>
<path d="M212.5 175.8l.3 .1z"/>
<path d="M198.3 175.8h.3z"/>
<path d="M199.3 175.8h.2z"/>
<path d="M201.4 175.8h.2z"/>
<path d="M201.7 175.8h.2z"/>
<path d="M202.5 175.8h.4z"/>
<path d="M205.2 175.8h.3z"/>
<path d="M206.1 175.8h.2z"/>
<path d="M209.2 175.8h.3z"/>
<path d="M209.7 175.8h.5z"/>
<path d="M212.5 175.8h.3z"/>
<path d="M198.4 175.7l.2 .1z"/>
<path d="M199.3 175.7l.2 .1z"/>
<path d="M201.4 175.7l.2 .1z"/>
<path d="M201.7 175.7l.2 .1z"/>
<path d="M202.4 175.7l.4 .1z"/>
<path d="M205.2 175.7l.2 .1z"/>
<path d="M209.1 175.7l.3 .1z"/>
<path d="M209.8 175.7l.4 .1z"/>
<path d="M212.5 175.7l.3 .1z"/>
<path d="M198.4 175.7h.2z"/>
<path d="M199.3 175.7h.2z"/>
<path d="M201.4 175.7h.2z"/>
<path d="M201.8 175.7h.2z"/>
<path d="M202.4 175.7h.3z"/>
<path d="M205.2 175.7h.2z"/>
<path d="M209.1 175.7h.3z"/>
<path d="M209.7 175.7h.5z"/>
<path d="M212.5 175.7h.3z"/>
<path d="M198.4 175.6l.2 .1z"/>
<path d="M199.3 175.6l.2 .1z"/>
<path d="M199.8 175.6l.1 .1z"/>
<path d="M201.4 175.6l.2 .1z"/>
<path d="M201.8 175.6l.2 .1z"/>
<path d="M202.3 175.6l.3 .1z"/>
<path d="M205.2 175.6l.2 .1z"/>
<path d="M209.1 175.6l.3 .1z"/>
<path d="M209.7 175.6l.5 .1z"/>
<path d="M212.5 175.6l.3 .1z"/>
<path d="M198.4 175.6h.2z"/>
<path d="M199.3 175.6h.2z"/>
<path d="M201.4 175.6h.1z"/>
<path d="M201.8 175.6h.2z"/>
<path d="M202.2 175.6h.3z"/>
<path d="M205.2 175.6h.1z"/>
<path d="M209.1 175.6h.3z"/>
<path d="M209.7 175.6h.5z"/>
<path d="M212.5 175.6h.3z"/>
<path d="M198.5 175.5l.2 .1z"/>
<path d="M199.3 175.5l.2 .1z"/>
<path d="M201.4 175.5l.1 .1z"/>
<path d="M201.8 175.5l.2 .1z"/>
<path d="M202.2 175.5l.3 .1z"/>
<path d="M205.1 175.5l.2 .1z"/>
<path d="M209.1 175.5l.3 .1z"/>
<path d="M209.7 175.5l.4 .1z"/>
<path d="M212.5 175.5l.3 .1z"/>
<path d="M198.5 175.5h.2z"/>
<path d="M199.3 175.5h.2z"/>
<path d="M201.4 175.5h.1z"/>
<path d="M201.8 175.5h.2z"/>
<path d="M202.2 175.5h.2z"/>
<path d="M205.1 175.5h.2z"/>
<path d="M209.1 175.5h.3z"/>
<path d="M209.7 175.5h.3z"/>
<path d="M212.5 175.5h.3z"/>
<path d="M198.5 175.4l.2 .1z"/>
<path d="M199.4 175.4l.1 .1z"/>
<path d="M201.4 175.4l.1 .1z"/>
<path d="M201.8 175.4l.2 .1z"/>
<path d="M202.2 175.4l.2 .1z"/>
<path d="M205.1 175.4l.2 .1z"/>
<path d="M209.1 175.4l.3 .1z"/>
<path d="M212.5 175.4l.3 .1z"/>
<path d="M198.5 175.4h.2z"/>
<path d="M199.4 175.4h.2z"/>
<path d="M201.4 175.4h.1z"/>
<path d="M201.8 175.4h.2z"/>
<path d="M202.2 175.4h.2z"/>
<path d="M205.1 175.4h.1z"/>
<path d="M209.1 175.4h.3z"/>
<path d="M209.6 175.4h.2z"/>
<path d="M212.6 175.4h.2z"/>
<path d="M198.6 175.3l.1 .1z"/>
<path d="M199.4 175.3l.2 .1z"/>
<path d="M201.3 175.3l.2 .1z"/>
<path d="M201.8 175.3l.2 .1z"/>
<path d="M202.2 175.3l.2 .1z"/>
<path d="M205.1 175.3l.1 .1z"/>
<path d="M208.1 175.3l.2 .1z"/>
<path d="M209.2 175.3l.2 .1z"/>
<path d="M209.6 175.3l.5 .1z"/>
<path d="M212.6 175.3l.5 .1z"/>
<path d="M198.6 175.3h.2z"/>
<path d="M199.4 175.3h.2z"/>
<path d="M201.3 175.3h.2z"/>
<path d="M201.8 175.3h.2z"/>
<path d="M202.2 175.3h.2z"/>
<path d="M205 175.3h.2z"/>
<path d="M208.1 175.3h.2z"/>
<path d="M209.2 175.3h.2z"/>
<path d="M209.6 175.3h.5z"/>
<path d="M212.6 175.3h.5z"/>
<path d="M213.4 175.3h.2z"/>
<path d="M198.6 175.2l.2 .1z"/>
<path d="M199.5 175.2l.1 .1z"/>
<path d="M201.3 175.2l.2 .1z"/>
<path d="M201.7 175.2l.3 .1z"/>
<path d="M202.2 175.2l.2 .1z"/>
<path d="M205 175.2l.2 .1z"/>
<path d="M208 175.2l.2 .1z"/>
<path d="M209.2 175.2l.3 .1z"/>
<path d="M212.7 175.2l.2 .1z"/>
<path d="M198.6 175.2h.2z"/>
<path d="M199.5 175.2h.2z"/>
<path d="M201.3 175.2h.2z"/>
<path d="M201.8 175.2h.2z"/>
<path d="M202.2 175.2h.2z"/>
<path d="M205 175.2h.2z"/>
<path d="M208 175.2h.2z"/>
<path d="M209.2 175.2h.2z"/>
<path d="M212.6 175.2h.2z"/>
<path d="M213.2 175.2h.2z"/>
<path d="M198.6 175.1l.2 .1z"/>
<path d="M199.5 175.1l.2 .1z"/>
<path d="M201.3 175.1l.2 .1z"/>
<path d="M201.7 175.1l.3 .1z"/>
<path d="M202.2 175.1l.2 .1z"/>
<path d="M205 175.1l.2 .1z"/>
<path d="M207.9 175.1l.2 .1z"/>
<path d="M209.2 175.1l.2 .1z"/>
<path d="M212.5 175.1l.2 .1z"/>
<path d="M213.2 175.1l.2 .1z"/>
<path d="M198.6 175.1h.2z"/>
<path d="M199.6 175.1h.1z"/>
<path d="M201.3 175.1h.2z"/>
<path d="M201.8 175.1h.2z"/>
<path d="M202.2 175.1h.2z"/>
<path d="M205 175.1h.2z"/>
<path d="M207.8 175.1h.2z"/>
<path d="M209.2 175.1h.2z"/>
<path d="M209.6 175.1h.2z"/>
<path d="M212.5 175.1h.2z"/>
<path d="M198.7 175l.2 .1z"/>
<path d="M199.6 175l.1 .1z"/>
<path d="M201.3 175l.2 .1z"/>
<path d="M201.8 175l.2 .1z"/>
<path d="M202.2 175l.2 .1z"/>
<path d="M202.7 175l.2 .1z"/>
<path d="M205 175l.2 .1z"/>
<path d="M207.8 175l.1 .1z"/>
<path d="M209.2 175l.2 .1z"/>
<path d="M212.5 175l.2 .1z"/>
<path d="M198.7 175h.2z"/>
<path d="M199.6 175h.2z"/>
<path d="M201.3 175h.2z"/>
<path d="M201.8 175h.2z"/>
<path d="M202.2 175h.2z"/>
<path d="M205 175h.2z"/>
<path d="M207.7 175h.3z"/>
<path d="M209.2 175h.2z"/>
<path d="M212.5 175h.3z"/>
<path d="M198.7 174.9l.2 .1z"/>
<path d="M199.6 174.9l.2 .1z"/>
<path d="M201.4 174.9l.2 .1z"/>
<path d="M201.8 174.9l.2 .1z"/>
<path d="M202.2 174.9l.2 .1z"/>
<path d="M205 174.9l.2 .1z"/>
<path d="M207.6 174.9l.3 .1z"/>
<path d="M209.2 174.9l.1 .1z"/>
<path d="M209.7 174.9l.3 .1z"/>
<path d="M212.7 174.9l.2 .1z"/>
<path d="M198.8 174.9h.1z"/>
<path d="M199.7 174.9h.1z"/>
<path d="M201.4 174.9h.2z"/>
<path d="M201.8 174.9h.2z"/>
<path d="M202.2 174.9h.2z"/>
<path d="M205 174.9h.2z"/>
<path d="M207.5 174.9h.2z"/>
<path d="M209.1 174.9h.2z"/>
<path d="M209.6 174.9h.5z"/>
<path d="M212.5 174.9h.2z"/>
<path d="M198.8 174.8l.1 .1z"/>
<path d="M201.5 174.8l.2 .1z"/>
<path d="M201.8 174.8l.2 .1z"/>
<path d="M202.2 174.8l.2 .1z"/>
<path d="M205 174.8l.2 .1z"/>
<path d="M207.5 174.8l.2 .1z"/>
<path d="M209.1 174.8l.2 .1z"/>
<path d="M209.6 174.8l.5 .1z"/>
<path d="M212.6 174.8l.1 .1z"/>
<path d="M198.8 174.8h.2z"/>
<path d="M199.7 174.8h.2z"/>
<path d="M201.5 174.8h.2z"/>
<path d="M201.9 174.8h.1z"/>
<path d="M202.1 174.8h.3z"/>
<path d="M205 174.8h.2z"/>
<path d="M207.5 174.8h.2z"/>
<path d="M209.1 174.8h.2z"/>
<path d="M209.6 174.8h.3z"/>
<path d="M212.6 174.8h.2z"/>
<path d="M198.8 174.7l.2 .1z"/>
<path d="M201.6 174.7l.2 .1z"/>
<path d="M201.9 174.7l.1 .1z"/>
<path d="M202.1 174.7l.3 .1z"/>
<path d="M205 174.7l.2 .1z"/>
<path d="M206.2 174.7l.3 .1z"/>
<path d="M207.4 174.7l.2 .1z"/>
<path d="M209.1 174.7l.2 .1z"/>
<path d="M209.6 174.7l.3 .1z"/>
<path d="M212.7 174.7l.2 .1z"/>
<path d="M198.9 174.7h.1z"/>
<path d="M199.8 174.7h.1z"/>
<path d="M201.7 174.7h.1z"/>
<path d="M201.9 174.7h.2z"/>
<path d="M202.1 174.7h.3z"/>
<path d="M205 174.7h.2z"/>
<path d="M206.3 174.7h.2z"/>
<path d="M207.3 174.7h.2z"/>
<path d="M209.1 174.7h.1z"/>
<path d="M209.5 174.7h.3z"/>
<path d="M212.8 174.7h.2z"/>
<path d="M201.7 174.6l.4 .1z"/>
<path d="M202.1 174.6l.3 .1z"/>
<path d="M205 174.6l.2 .1z"/>
<path d="M206.3 174.6l.3 .1z"/>
<path d="M207.2 174.6l.3 .1z"/>
<path d="M209.1 174.6l.1 .1z"/>
<path d="M209.5 174.6l.3 .1z"/>
<path d="M210 174.6l.2 .1z"/>
<path d="M198.9 174.6h.2z"/>
<path d="M201.8 174.6h.3z"/>
<path d="M202.1 174.6h.3z"/>
<path d="M205 174.6h.2z"/>
<path d="M206.5 174.6h.2z"/>
<path d="M207.2 174.6h.2z"/>
<path d="M209 174.6h.2z"/>
<path d="M209.5 174.6h.3z"/>
<path d="M210 174.6h.2z"/>
<path d="M213.7 174.6h.2z"/>
<path d="M199 174.5l.1 .1z"/>
<path d="M201.8 174.5l.6 .1z"/>
<path d="M205 174.5l.2 .1z"/>
<path d="M206.6 174.5l.2 .1z"/>
<path d="M207.1 174.5l.2 .1z"/>
<path d="M209 174.5l.2 .1z"/>
<path d="M209.5 174.5l.4 .1z"/>
<path d="M210 174.5l.2 .1z"/>
<path d="M212.9 174.5l.2 .1z"/>
<path d="M213.7 174.5l.3 .1z"/>
<path d="M199 174.5h.2z"/>
<path d="M200.7 174.5h.3z"/>
<path d="M201.9 174.5h.5z"/>
<path d="M205 174.5h.2z"/>
<path d="M206.7 174.5h.2z"/>
<path d="M207 174.5h.2z"/>
<path d="M209 174.5h.2z"/>
<path d="M209.5 174.5h.3z"/>
<path d="M210 174.5h.2z"/>
<path d="M212.9 174.5h.4z"/>
<path d="M199.1 174.4l.1 .1z"/>
<path d="M200.5 174.4l.5 .1z"/>
<path d="M201.9 174.4l.5 .1z"/>
<path d="M205.1 174.4l.2 .1z"/>
<path d="M206.1 174.4l.2 .1z"/>
<path d="M206.8 174.4l.5 .1z"/>
<path d="M209 174.4l.1 .1z"/>
<path d="M209.5 174.4l.3 .1z"/>
<path d="M210 174.4l.2 .1z"/>
<path d="M213 174.4l.3 .1z"/>
<path d="M199.1 174.4h.2z"/>
<path d="M199.9 174.4h.2z"/>
<path d="M200.5 174.4h.5z"/>
<path d="M202 174.4h.4z"/>
<path d="M202.8 174.4h.2z"/>
<path d="M205.1 174.4h.2z"/>
<path d="M206.2 174.4h.2z"/>
<path d="M206.9 174.4h.3z"/>
<path d="M209 174.4h.1z"/>
<path d="M209.5 174.4h.4z"/>
<path d="M210 174.4h.2z"/>
<path d="M212.9 174.4h.5z"/>
<path d="M213.6 174.4h.2z"/>
<path d="M199.2 174.3h.2z"/>
<path d="M200.5 174.3h.5z"/>
<path d="M202 174.3h.4z"/>
<path d="M205.1 174.3h.2z"/>
<path d="M206.9 174.3h.3z"/>
<path d="M208.9 174.3h.2z"/>
<path d="M209.5 174.3h.3z"/>
<path d="M210 174.3h.2z"/>
<path d="M212.9 174.3h.2z"/>
<path d="M213.4 174.3h.2z"/>
<path d="M199.2 174.3h.3z"/>
<path d="M200.6 174.3h.3z"/>
<path d="M206.3 174.3h.1z"/>
<path d="M206.8 174.3h.2z"/>
<path d="M209.4 174.3h.4z"/>
<path d="M212.9 174.3h.1z"/>
<path d="M199.3 174.2h.2z"/>
<path d="M200.5 174.2h.3z"/>
<path d="M202 174.2h.4z"/>
<path d="M205.1 174.2h.2z"/>
<path d="M208.9 174.2h.3z"/>
<path d="M209.4 174.2h.4z"/>
<path d="M210 174.2h.2z"/>
<path d="M212.9 174.2h.1z"/>
<path d="M199.4 174.2h.2z"/>
<path d="M202.1 174.2h.3z"/>
<path d="M203.2 174.2h.2z"/>
<path d="M206.7 174.2h.2z"/>
<path d="M208.9 174.2h.2z"/>
<path d="M213.4 174.2h.2z"/>
<path d="M199.5 174.1l.2 .1z"/>
<path d="M200.5 174.1l.2 .1z"/>
<path d="M202.1 174.1l.3 .1z"/>
<path d="M203.1 174.1l.4 .1z"/>
<path d="M205.1 174.1l.2 .1z"/>
<path d="M206.7 174.1l.2 .1z"/>
<path d="M208.9 174.1l.2 .1z"/>
<path d="M209.4 174.1l.3 .1z"/>
<path d="M210 174.1l.2 .1z"/>
<path d="M213.3 174.1l.5 .1z"/>
<path d="M199.5 174.1h.3z"/>
<path d="M200.4 174.1h.3z"/>
<path d="M202.2 174.1h.2z"/>
<path d="M203.1 174.1h.5z"/>
<path d="M205.2 174.1h.2z"/>
<path d="M206.6 174.1h.2z"/>
<path d="M208.9 174.1h.3z"/>
<path d="M209.4 174.1h.3z"/>
<path d="M210 174.1h.2z"/>
<path d="M213 174.1h.1z"/>
<path d="M213.3 174.1h.2z"/>
<path d="M199.6 174l.3 .1z"/>
<path d="M200.4 174l.3 .1z"/>
<path d="M202.2 174l.2 .1z"/>
<path d="M202.7 174l.2 .1z"/>
<path d="M203.1 174l.5 .1z"/>
<path d="M205.2 174l.2 .1z"/>
<path d="M206.5 174l.2 .1z"/>
<path d="M208.9 174l.2 .1z"/>
<path d="M209.4 174l.3 .1z"/>
<path d="M210 174l.2 .1z"/>
<path d="M213.7 174l.3 .1z"/>
<path d="M214.9 174l.2 .1z"/>
<path d="M199.7 173.9l.3 .1z"/>
<path d="M200.3 173.9l.4 .1z"/>
<path d="M202.3 173.9l.2 .1z"/>
<path d="M202.6 173.9l.3 .1z"/>
<path d="M203.1 173.9l.3 .1z"/>
<path d="M205.2 173.9l.2 .1z"/>
<path d="M206.4 173.9l.3 .1z"/>
<path d="M208.9 173.9l.3 .1z"/>
<path d="M209.4 173.9l.2 .1z"/>
<path d="M210 173.9l.2 .1z"/>
<path d="M213.2 173.9l.2 .1z"/>
<path d="M215 173.9l.2 .1z"/>
<path d="M199.8 173.9h.8z"/>
<path d="M200.6 173.9h.2z"/>
<path d="M202.3 173.9h.6z"/>
<path d="M203.1 173.9h.3z"/>
<path d="M205.3 173.9h.1z"/>
<path d="M206.4 173.9h.2z"/>
<path d="M208.9 173.9h.2z"/>
<path d="M209.4 173.9h.2z"/>
<path d="M210 173.9h.2z"/>
<path d="M212.5 173.9h.2z"/>
<path d="M212.9 173.9h.2z"/>
<path d="M214.7 173.9h.2z"/>
<path d="M199.9 173.9h.6z"/>
<path d="M202.4 173.9h.5z"/>
<path d="M203.1 173.9h.2z"/>
<path d="M206.3 173.9h.2z"/>
<path d="M212.4 173.9h.3z"/>
<path d="M200 173.8h.5z"/>
<path d="M200.9 173.8h.2z"/>
<path d="M202.4 173.8h.5z"/>
<path d="M203.1 173.8h.2z"/>
<path d="M206.2 173.8h.3z"/>
<path d="M208.9 173.8h.2z"/>
<path d="M209.4 173.8h.2z"/>
<path d="M210 173.8h.2z"/>
<path d="M212.3 173.8h.4z"/>
<path d="M212.9 173.8h.2z"/>
<path d="M213.2 173.8h.2z"/>
<path d="M215.1 173.8h.2z"/>
<path d="M200.6 173.8h.2z"/>
<path d="M200.9 173.8h.1z"/>
<path d="M202.5 173.8h.4z"/>
<path d="M203 173.8h.3z"/>
<path d="M205.3 173.8h.2z"/>
<path d="M206.1 173.8h.3z"/>
<path d="M212.3 173.8h.5z"/>
<path d="M214.5 173.8h.3z"/>
<path d="M200.1 173.7h.4z"/>
<path d="M200.6 173.7h.3z"/>
<path d="M202.5 173.7h.5z"/>
<path d="M206.1 173.7h.2z"/>
<path d="M209 173.7h.2z"/>
<path d="M210 173.7h.2z"/>
<path d="M212.3 173.7h.2z"/>
<path d="M212.6 173.7h.3z"/>
<path d="M213.2 173.7h.2z"/>
<path d="M214.6 173.7h.3z"/>
<path d="M200.1 173.7h.9z"/>
<path d="M205.4 173.7h.1z"/>
<path d="M212.2 173.7h.2z"/>
<path d="M212.6 173.7h.4z"/>
<path d="M213.6 173.7h.2z"/>
<path d="M214.8 173.7h.2z"/>
<path d="M200.2 173.6l.8 .1z"/>
<path d="M202.5 173.6l.5 .1z"/>
<path d="M209 173.6l.2 .1z"/>
<path d="M210 173.6l.2 .1z"/>
<path d="M212.2 173.6l.2 .1z"/>
<path d="M212.6 173.6l.4 .1z"/>
<path d="M214.1 173.6l.1 .1z"/>
<path d="M214.4 173.6l.1 .1z"/>
<path d="M200.2 173.5l.8 .1z"/>
<path d="M202.5 173.5l.5 .1z"/>
<path d="M203.1 173.5l.1 .1z"/>
<path d="M203.3 173.5l.2 .1z"/>
<path d="M206.1 173.5l.1 .1z"/>
<path d="M209 173.5l.3 .1z"/>
<path d="M210 173.5l.2 .1z"/>
<path d="M212.2 173.5l.1 .1z"/>
<path d="M212.6 173.5l.3 .1z"/>
<path d="M214 173.5l.2 .1z"/>
<path d="M214.2 173.5l.4 .1z"/>
<path d="M215 173.5l.2 .1z"/>
<path d="M200.2 173.5h.8z"/>
<path d="M202.5 173.5h.8z"/>
<path d="M203.3 173.5h.2z"/>
<path d="M206.1 173.5h.1z"/>
<path d="M209 173.5h.3z"/>
<path d="M210 173.5h.2z"/>
<path d="M212.2 173.5h.1z"/>
<path d="M212.6 173.5h.2z"/>
<path d="M214.2 173.5h.5z"/>
<path d="M215 173.5h.2z"/>
<path d="M200.3 173.4l.6 .1z"/>
<path d="M202.5 173.4l.8 .1z"/>
<path d="M205.5 173.4l.3 .1z"/>
<path d="M206 173.4l.5 .1z"/>
<path d="M209.1 173.4l.2 .1z"/>
<path d="M210 173.4l.2 .1z"/>
<path d="M212.2 173.4l.1 .1z"/>
<path d="M212.6 173.4l.2 .1z"/>
<path d="M213.1 173.4l.2 .1z"/>
<path d="M214.5 173.4l.3 .1z"/>
<path d="M215.1 173.4l.2 .1z"/>
<path d="M200.3 173.4h.5z"/>
<path d="M202.5 173.4h1z"/>
<path d="M205.5 173.4h.4z"/>
<path d="M206 173.4h.5z"/>
<path d="M209.1 173.4h.2z"/>
<path d="M210 173.4h.2z"/>
<path d="M212.2 173.4h.1z"/>
<path d="M212.6 173.4h.2z"/>
<path d="M214.7 173.4h.2z"/>
<path d="M215.2 173.4h.2z"/>
<path d="M205.4 173.4h.5z"/>
<path d="M206 173.4h.6z"/>
<path d="M213 173.4h.2z"/>
<path d="M214.8 173.4h.2z"/>
<path d="M215.1 173.4h.1z"/>
<path d="M215.3 173.4h.2z"/>
<path d="M202.6 173.3h.8z"/>
<path d="M205.4 173.3h.5z"/>
<path d="M206 173.3h.6z"/>
<path d="M209.1 173.3h.3z"/>
<path d="M210 173.3h.2z"/>
<path d="M212.2 173.3h.1z"/>
<path d="M212.6 173.3h.2z"/>
<path d="M214.9 173.3h.1z"/>
<path d="M215.2 173.3h.1z"/>
<path d="M215.4 173.3h.2z"/>
<path d="M202.7 173.2l.6 .1z"/>
<path d="M205.4 173.2l.5 .1z"/>
<path d="M206 173.2l.5 .1z"/>
<path d="M209.1 173.2l.2 .1z"/>
<path d="M210 173.2l.2 .1z"/>
<path d="M212.2 173.2l.1 .1z"/>
<path d="M213 173.2l.1 .1z"/>
<path d="M215 173.2l.1 .1z"/>
<path d="M215.3 173.2l.1 .1z"/>
<path d="M215.6 173.2l.2 .1z"/>
<path d="M202.8 173.2h.5z"/>
<path d="M205.4 173.2h1z"/>
<path d="M209.2 173.2h.2z"/>
<path d="M210 173.2h.2z"/>
<path d="M212.2 173.2h.1z"/>
<path d="M213 173.2h.1z"/>
<path d="M215.1 173.2h.1z"/>
<path d="M215.4 173.2h.1z"/>
<path d="M215.7 173.2h.1z"/>
<path d="M205.3 173.1l.9 .1z"/>
<path d="M206.2 173.1l.3 .1z"/>
<path d="M209.2 173.1l.2 .1z"/>
<path d="M210 173.1l.2 .1z"/>
<path d="M212.2 173.1l.1 .1z"/>
<path d="M215.2 173.1l.1 .1z"/>
<path d="M215.5 173.1l.1 .1z"/>
<path d="M215.8 173.1l.1 .1z"/>
<path d="M205.3 173.1h.8z"/>
<path d="M206.3 173.1h.2z"/>
<path d="M209.2 173.1h.2z"/>
<path d="M210 173.1h.2z"/>
<path d="M212.2 173.1h.1z"/>
<path d="M212.9 173.1h.2z"/>
<path d="M215.3 173.1h.1z"/>
<path d="M215.6 173.1h.2z"/>
<path d="M215.9 173.1h.1z"/>
<path d="M205.2 173l.7 .1z"/>
<path d="M206 173l.1 .1z"/>
<path d="M209.2 173l.2 .1z"/>
<path d="M212.2 173l.1 .1z"/>
<path d="M213.2 173l.2 .1z"/>
<path d="M215.7 173l.1 .1z"/>
<path d="M216 173l.2 .1z"/>
<path d="M205.2 173h.2z"/>
<path d="M205.4 173h.4z"/>
<path d="M206 173h.1z"/>
<path d="M209.2 173h.2z"/>
<path d="M212.2 173h.1z"/>
<path d="M212.9 173h.1z"/>
<path d="M215.8 173h.1z"/>
<path d="M216.1 173h.2z"/>
<path d="M205.1 172.9l.2 .1z"/>
<path d="M205.4 172.9l.5 .1z"/>
<path d="M206 172.9l.1 .1z"/>
<path d="M209.2 172.9l.2 .1z"/>
<path d="M212.2 172.9l.1 .1z"/>
<path d="M212.8 172.9l.2 .1z"/>
<path d="M215.9 172.9l.1 .1z"/>
<path d="M205 172.9h.3z"/>
<path d="M205.4 172.9h.5z"/>
<path d="M206 172.9h.1z"/>
<path d="M209.2 172.9h.2z"/>
<path d="M212.2 172.9h.1z"/>
<path d="M212.8 172.9h.2z"/>
<path d="M213.3 172.9h.2z"/>
<path d="M215.6 172.9h.2z"/>
<path d="M216 172.9h.2z"/>
<path d="M205 172.8l.2 .1z"/>
<path d="M205.4 172.8l.7 .1z"/>
<path d="M206.3 172.8l.2 .1z"/>
<path d="M209.9 172.8l.2 .1z"/>
<path d="M212.2 172.8l.1 .1z"/>
<path d="M212.8 172.8l.2 .1z"/>
<path d="M213.3 172.8l.2 .1z"/>
<path d="M215.7 172.8l.2 .1z"/>
<path d="M216.1 172.8l.2 .1z"/>
<path d="M204.9 172.8h.2z"/>
<path d="M205.4 172.8h.7z"/>
<path d="M206.3 172.8h.2z"/>
<path d="M209.9 172.8h.2z"/>
<path d="M212.2 172.8h.1z"/>
<path d="M212.8 172.8h.2z"/>
<path d="M213.3 172.8h.2z"/>
<path d="M216.2 172.8h.2z"/>
<path d="M204.9 172.7l.2 .1z"/>
<path d="M205.4 172.7l.7 .1z"/>
<path d="M209.8 172.7l.3 .1z"/>
<path d="M212.2 172.7l.1 .1z"/>
<path d="M212.8 172.7l.3 .1z"/>
<path d="M213.3 172.7l.2 .1z"/>
<path d="M216.3 172.7l.3 .1z"/>
<path d="M204.8 172.7h.2z"/>
<path d="M205.5 172.7h.6z"/>
<path d="M209.6 172.7h.2z"/>
<path d="M209.9 172.7h.2z"/>
<path d="M212.2 172.7h.1z"/>
<path d="M212.8 172.7h.2z"/>
<path d="M213.2 172.7h.2z"/>
<path d="M216 172.7h.2z"/>
<path d="M216.5 172.7h.2z"/>
<path d="M204.7 172.6l.2 .1z"/>
<path d="M205.5 172.6l.6 .1z"/>
<path d="M212.9 172.6l.1 .1z"/>
<path d="M213.3 172.6l.2 .1z"/>
<path d="M216.1 172.6l.2 .1z"/>
<path d="M216.5 172.6l.2 .1z"/>
<path d="M204.7 172.6h.2z"/>
<path d="M205.5 172.6h.6z"/>
<path d="M212.2 172.6h.2z"/>
<path d="M213.2 172.6h.2z"/>
<path d="M216.6 172.6h.3z"/>
<path d="M204.6 172.5l.2 .1z"/>
<path d="M205.5 172.5l.8 .1z"/>
<path d="M209.5 172.5l.2 .1z"/>
<path d="M212.2 172.5l.2 .1z"/>
<path d="M212.9 172.5l.3 .1z"/>
<path d="M216.7 172.5l.2 .1z"/>
<path d="M204.5 172.5h.3z"/>
<path d="M205.6 172.5h.7z"/>
<path d="M209.5 172.5h.2z"/>
<path d="M212.2 172.5h.2z"/>
<path d="M213.1 172.5h.2z"/>
<path d="M216.8 172.5h.2z"/>
<path d="M204.4 172.4l.3 .1z"/>
<path d="M205.6 172.4l.7 .1z"/>
<path d="M209.5 172.4l.2 .1z"/>
<path d="M213.1 172.4l.2 .1z"/>
<path d="M216.7 172.4l.2 .1z"/>
<path d="M204.4 172.4h.2z"/>
<path d="M205.8 172.4h.4z"/>
<path d="M209.3 172.4h.4z"/>
<path d="M213.5 172.4h.2z"/>
<path d="M216.7 172.4h.2z"/>
<path d="M209.3 172.3l.4 .1z"/>
<path d="M213 172.3l.2 .1z"/>
<path d="M213.5 172.3l.2 .1z"/>
<path d="M204.3 172.3h.2z"/>
<path d="M209.3 172.3h.4z"/>
<path d="M204.2 172.2l.2 .1z"/>
<path d="M209.3 172.2l.5 .1z"/>
<path d="M212.3 172.2l.2 .1z"/>
<path d="M204.2 172.2h.2z"/>
<path d="M209.3 172.2h.5z"/>
<path d="M209.3 172.1l.5 .1z"/>
<path d="M204 172.1h.3z"/>
<path d="M209.3 172.1h.4z"/>
<path d="M213.2 172.1h.2z"/>
<path d="M203.9 172l.3 .1z"/>
<path d="M209.3 172l.3 .1z"/>
<path d="M203.9 172h.2z"/>
<path d="M209.3 172h.3z"/>
<path d="M212.9 172h.2z"/>
<path d="M203.7 171.9l.2 .1z"/>
<path d="M209.3 171.9l.7 .1z"/>
<path d="M203.7 171.9h.3z"/>
<path d="M209.3 171.9h.8z"/>
<path d="M212.2 171.9h.1z"/>
<path d="M212.9 171.9h.1z"/>
<path d="M203.6 171.8l.2 .1z"/>
<path d="M209.3 171.8l.8 .1z"/>
<path d="M212.2 171.8l.1 .1z"/>
<path d="M213 171.8l.2 .1z"/>
<path d="M209.3 171.8h.9z"/>
<path d="M212.1 171.8h.3z"/>
<path d="M212.8 171.8h.3z"/>
<path d="M209.3 171.7l.9 .1z"/>
<path d="M212.1 171.7l.2 .1z"/>
<path d="M212.9 171.7l.2 .1z"/>
<path d="M203.5 171.7h.3z"/>
<path d="M209.3 171.7h.9z"/>
<path d="M212.1 171.7h.2z"/>
<path d="M209.4 171.6l.7 .1z"/>
<path d="M212.8 171.6l.2 .1z"/>
<path d="M212.6 171.6h.1z"/>
<path d="M212.8 171.6h.2z"/>
<path d="M212.8 171.5l.2 .1z"/>
<path d="M213 171.4h.3z"/>
<path d="M192.3 123h1v.5h-1z"/>
<path d="M190.8 123h1v.5h-1z"/>
<path d="M192.3 120.5h1v.5h-1z"/>
<path d="M190.8 120.5h1v.5h-1z"/>
<path d="M192.3 118h1v.5h-1z"/>
<path d="M190.8 118h1v.5h-1z"/>
</g>
<g fill="#c90d0c" stroke="#c90d0c" stroke-width=".21">
<path d="M120.8 33.5a1.39 1.39 0 0 1 2.2 .2 1.39 1.39 0 0 1-.8 2.1 1.39 1.39 0 0 1-1.8-1.4h.2a1.15 1.15 0 0 1 1.7-1.1 1.15 1.15 0 0 1 .2 1.9 1.15 1.15 0 0 1-1.8-.5l-.1-.3h-.2z" fill-rule="evenodd"/>
<path d="M129.9 43.9h.3a.51 .51 0 0 0 .5 .5 .51 .51 0 0 0 .5-.5h.2a.76 .76 0 0 1-.7 .8 .76 .76 0 0 1-.8-.8z" fill-rule="evenodd"/>
<path d="M127.4 43.9h.2a.51 .51 0 0 0 .5 .5 .51 .51 0 0 0 .6-.5h.2a.76 .76 0 0 1-.8 .8 .76 .76 0 0 1-.7-.8z" fill-rule="evenodd"/>
<path d="M124.8 43.9h.3a.51 .51 0 0 0 .5 .5 .51 .51 0 0 0 .5-.5h.3a.76 .76 0 0 1-.8 .8 .76 .76 0 0 1-.8-.8z" fill-rule="evenodd"/>
<path d="M130.1 39.6a.76 .76 0 0 1 .9-.2 .76 .76 0 0 1 .4 .7h-.2a.51 .51 0 0 0-.5-.5 .51 .51 0 0 0-.5 .5h-.3z" fill-rule="evenodd"/>
<path d="M127.6 39.6a.76 .76 0 0 1 .8-.2 .76 .76 0 0 1 .5 .7h-.2a.51 .51 0 0 0-.6-.5 .51 .51 0 0 0-.5 .5h-.2z" fill-rule="evenodd"/>
<path d="M125.1 39.6a.76 .76 0 0 1 .8-.2 .76 .76 0 0 1 .5 .7h-.3a.51 .51 0 0 0-.5-.5 .51 .51 0 0 0-.5 .5h-.3z" fill-rule="evenodd"/>
<path d="M135 43.9h.3a.51 .51 0 0 0 .5 .5 .51 .51 0 0 0 .5-.5h.2a.76 .76 0 0 1-.7 .8 .76 .76 0 0 1-.8-.8z" fill-rule="evenodd"/>
<path d="M132.5 43.9h.2a.51 .51 0 0 0 .5 .5 .51 .51 0 0 0 .5-.5h.3a.76 .76 0 0 1-.8 .8 .76 .76 0 0 1-.7-.8z" fill-rule="evenodd"/>
<path d="M135.2 39.6a.76 .76 0 0 1 .9-.2 .76 .76 0 0 1 .4 .7h-.2a.51 .51 0 0 0-.5-.5 .51 .51 0 0 0-.5 .5h-.3z" fill-rule="evenodd"/>
<path d="M132.7 39.6a.76 .76 0 0 1 .8-.2 .76 .76 0 0 1 .5 .7h-.3a.51 .51 0 0 0-.5-.5 .51 .51 0 0 0-.5 .5h-.2z" fill-rule="evenodd"/>
<path d="M142.6 43.9h.3a.51 .51 0 0 0 .5 .5 .51 .51 0 0 0 .5-.5h.2a.76 .76 0 0 1-.7 .8 .76 .76 0 0 1-.8-.8z" fill-rule="evenodd"/>
<path d="M140.1 43.9h.2a.51 .51 0 0 0 .5 .5 .51 .51 0 0 0 .6-.5h.2a.76 .76 0 0 1-.8 .8 .76 .76 0 0 1-.7-.8z" fill-rule="evenodd"/>
<path d="M137.5 43.9h.3a.51 .51 0 0 0 .5 .5 .51 .51 0 0 0 .5-.5h.3a.76 .76 0 0 1-.8 .8 .76 .76 0 0 1-.8-.8z" fill-rule="evenodd"/>
<path d="M142.8 39.6a.76 .76 0 0 1 .9-.2 .76 .76 0 0 1 .4 .7h-.2a.51 .51 0 0 0-.5-.5 .51 .51 0 0 0-.5 .5h-.3z" fill-rule="evenodd"/>
<path d="M140.3 39.6a.76 .76 0 0 1 .8-.2 .76 .76 0 0 1 .5 .7h-.2a.51 .51 0 0 0-.6-.5 .51 .51 0 0 0-.5 .5h-.2z" fill-rule="evenodd"/>
<path d="M137.8 39.6a.76 .76 0 0 1 .8-.2 .76 .76 0 0 1 .5 .7h-.3a.51 .51 0 0 0-.5-.5 .51 .51 0 0 0-.5 .5h-.3z" fill-rule="evenodd"/>
<path d="M147.7 43.9h.3a.51 .51 0 0 0 .5 .5 .51 .51 0 0 0 .5-.5h.2a.76 .76 0 0 1-.7 .8 .76 .76 0 0 1-.8-.8z" fill-rule="evenodd"/>
<path d="M145.2 43.9h.2a.51 .51 0 0 0 .5 .5 .51 .51 0 0 0 .5-.5h.3a.76 .76 0 0 1-.8 .8 .76 .76 0 0 1-.7-.8z" fill-rule="evenodd"/>
<path d="M147.9 39.6a.77 .77 0 0 1 .9-.2 .77 .77 0 0 1 .4 .7h-.2a.51 .51 0 0 0-.5-.5 .51 .51 0 0 0-.5 .5h-.3z" fill-rule="evenodd"/>
<path d="M145.4 39.6a.77 .77 0 0 1 .8-.2 .77 .77 0 0 1 .5 .7h-.3a.51 .51 0 0 0-.5-.5 .51 .51 0 0 0-.5 .5h-.2z" fill-rule="evenodd"/>
<path d="M155.3 43.9h.3a.51 .51 0 0 0 .5 .5 .51 .51 0 0 0 .5-.5h.2a.76 .76 0 0 1-.7 .8 .76 .76 0 0 1-.8-.8z" fill-rule="evenodd"/>
<path d="M152.8 43.9h.2a.51 .51 0 0 0 .5 .5 .51 .51 0 0 0 .6-.5h.2a.76 .76 0 0 1-.8 .8 .76 .76 0 0 1-.7-.8z" fill-rule="evenodd"/>
<path d="M150.2 43.9h.3a.51 .51 0 0 0 .5 .5 .51 .51 0 0 0 .5-.5h.3a.76 .76 0 0 1-.8 .8 .76 .76 0 0 1-.8-.8z" fill-rule="evenodd"/>
<path d="M155.5 39.6a.77 .77 0 0 1 .9-.2 .77 .77 0 0 1 .4 .7h-.2a.51 .51 0 0 0-.5-.5 .51 .51 0 0 0-.5 .5h-.3z" fill-rule="evenodd"/>
<path d="M153 39.6a.77 .77 0 0 1 .8-.2 .77 .77 0 0 1 .5 .7h-.2a.51 .51 0 0 0-.6-.5 .51 .51 0 0 0-.5 .5h-.2z" fill-rule="evenodd"/>
<path d="M150.5 39.6a.77 .77 0 0 1 .8-.2 .77 .77 0 0 1 .5 .7h-.3a.51 .51 0 0 0-.5-.5 .51 .51 0 0 0-.5 .5h-.3z" fill-rule="evenodd"/>
<path d="M160.4 43.9h.3a.51 .51 0 0 0 .5 .5 .51 .51 0 0 0 .5-.5h.2a.76 .76 0 0 1-.7 .8 .76 .76 0 0 1-.8-.8z" fill-rule="evenodd"/>
<path d="M157.9 43.9h.2a.51 .51 0 0 0 .5 .5 .51 .51 0 0 0 .5-.5h.3a.76 .76 0 0 1-.8 .8 .76 .76 0 0 1-.7-.8z" fill-rule="evenodd"/>
<path d="M160.6 39.6a.77 .77 0 0 1 .9-.2 .77 .77 0 0 1 .4 .7h-.2a.51 .51 0 0 0-.5-.5 .51 .51 0 0 0-.5 .5h-.3z" fill-rule="evenodd"/>
<path d="M158.1 39.6a.77 .77 0 0 1 .8-.2 .77 .77 0 0 1 .5 .7h-.3a.51 .51 0 0 0-.5-.5 .51 .51 0 0 0-.5 .5h-.2z" fill-rule="evenodd"/>
<path d="M165.5 43.9h.2a.51 .51 0 0 0 .5 .5 .51 .51 0 0 0 .6-.5h.2a.76 .76 0 0 1-.8 .8 .76 .76 0 0 1-.7-.8z" fill-rule="evenodd"/>
<path d="M162.9 43.9h.3a.51 .51 0 0 0 .5 .5 .51 .51 0 0 0 .5-.5h.3a.76 .76 0 0 1-.8 .8 .76 .76 0 0 1-.8-.8z" fill-rule="evenodd"/>
<path d="M165.7 39.6a.77 .77 0 0 1 .8-.2 .77 .77 0 0 1 .5 .7h-.2a.51 .51 0 0 0-.6-.5 .51 .51 0 0 0-.5 .5h-.2z" fill-rule="evenodd"/>
<path d="M163.2 39.6a.77 .77 0 0 1 .8-.2 .77 .77 0 0 1 .5 .7h-.3a.51 .51 0 0 0-.5-.5 .51 .51 0 0 0-.5 .5h-.3z" fill-rule="evenodd"/>
<path d="M173.1 43.9h.3a.51 .51 0 0 0 .5 .5 .51 .51 0 0 0 .5-.5h.2a.76 .76 0 0 1-.7 .8 .76 .76 0 0 1-.8-.8z" fill-rule="evenodd"/>
<path d="M170.6 43.9h.2a.51 .51 0 0 0 .5 .5 .51 .51 0 0 0 .5-.5h.3a.76 .76 0 0 1-.8 .8 .76 .76 0 0 1-.7-.8z" fill-rule="evenodd"/>
<path d="M168 43.9h.3a.51 .51 0 0 0 .5 .5 .51 .51 0 0 0 .5-.5h.2a.76 .76 0 0 1-.7 .8 .76 .76 0 0 1-.8-.8z" fill-rule="evenodd"/>
<path d="M173.3 39.6a.77 .77 0 0 1 .9-.2 .77 .77 0 0 1 .4 .7h-.2a.51 .51 0 0 0-.5-.5 .51 .51 0 0 0-.5 .5h-.3z" fill-rule="evenodd"/>
<path d="M170.8 39.6a.77 .77 0 0 1 .8-.2 .77 .77 0 0 1 .5 .7h-.3a.51 .51 0 0 0-.5-.5 .51 .51 0 0 0-.5 .5h-.2z" fill-rule="evenodd"/>
<path d="M168.2 39.6a.77 .77 0 0 1 .9-.2 .77 .77 0 0 1 .4 .7h-.2a.51 .51 0 0 0-.5-.5 .51 .51 0 0 0-.5 .5h-.3z" fill-rule="evenodd"/>
<path d="M267.5 41.3l.7-.3v.3a.76 .76 0 0 0-.8 .7 .76 .76 0 0 0 .8 .8v.3a1.02 1.02 0 0 1-1-.7 1.02 1.02 0 0 1 .3-1.1z" fill-rule="evenodd"/>
<path d="M267.5 43.8l.7-.2v.2a.76 .76 0 0 0-.8 .8 .76 .76 0 0 0 .8 .7v.3a1.02 1.02 0 0 1-1-.7 1.02 1.02 0 0 1 .3-1.1z" fill-rule="evenodd"/>
<path d="M267.5 46.3l.7-.2v.3a.76 .76 0 0 0-.8 .7 .76 .76 0 0 0 .8 .8v.2a1.02 1.02 0 0 1-1-.6 1.02 1.02 0 0 1 .3-1.2z" fill-rule="evenodd"/>
<path d="M267.5 48.9l.7-.3v.3a.76 .76 0 0 0-.8 .8 .76 .76 0 0 0 .8 .7v.3a1.02 1.02 0 0 1-1-.7 1.02 1.02 0 0 1 .3-1.1z" fill-rule="evenodd"/>
<path d="M267.5 51.4l.7-.2v.2a.76 .76 0 0 0-.8 .8 .76 .76 0 0 0 .8 .8v.2a1.02 1.02 0 0 1-1-.6 1.02 1.02 0 0 1 .3-1.2z" fill-rule="evenodd"/>
<path d="M267.5 54l.7-.3v.3a.76 .76 0 0 0-.8 .7 .76 .76 0 0 0 .8 .8v.3a1.02 1.02 0 0 1-1-.7 1.02 1.02 0 0 1 .3-1.1z" fill-rule="evenodd"/>
<path d="M267.5 56.5l.7-.2v.2a.76 .76 0 0 0-.8 .8 .76 .76 0 0 0 .8 .7v.3a1.02 1.02 0 0 1-1-.7 1.02 1.02 0 0 1 .3-1.1z" fill-rule="evenodd"/>
<path d="M267.5 59l.7-.2v.3a.76 .76 0 0 0-.8 .7 .76 .76 0 0 0 .8 .8v.2a1.02 1.02 0 0 1-1-.6 1.02 1.02 0 0 1 .3-1.2z" fill-rule="evenodd"/>
<path d="M267.5 61.6l.7-.3v.3a.76 .76 0 0 0-.8 .8 .76 .76 0 0 0 .8 .7v.3a1.02 1.02 0 0 1-1-.7 1.02 1.02 0 0 1 .3-1.1z" fill-rule="evenodd"/>
<path d="M27.6 52.5a1.39 1.39 0 0 1 2.2 .3 1.39 1.39 0 0 1-.8 2 1.39 1.39 0 0 1-1.8-1.3h.3a1.14 1.14 0 0 1 1.5-1.1 1.14 1.14 0 0 1 .3 1.9 1.14 1.14 0 0 1-1.8-.6v-.2h-.3z" fill-rule="evenodd"/>
<path d="M47.9 52.5a1.39 1.39 0 0 1 2.2 .3 1.39 1.39 0 0 1-.8 2 1.39 1.39 0 0 1-1.8-1.3h.3a1.14 1.14 0 0 1 1.6-1 1.14 1.14 0 0 1 .2 1.9 1.14 1.14 0 0 1-1.8-.7v-.2h-.3z" fill-rule="evenodd"/>
<path d="M67.4 29.1a1.4 1.4 0 0 1 2.3 .2 1.4 1.4 0 0 1-.8 2.1 1.4 1.4 0 0 1-1.8-1.3h.2a1.14 1.14 0 0 1 1.7-1 1.14 1.14 0 0 1 .2 2 1.14 1.14 0 0 1-1.8-.7l-.1-.3h-.2z" fill-rule="evenodd"/>
<path d="M92.8 29.1a1.4 1.4 0 0 1 2.3 .3 1.4 1.4 0 0 1-.9 2.1 1.4 1.4 0 0 1-1.7-1.4h.2a1.15 1.15 0 0 1 1.6-1.1 1.15 1.15 0 0 1 .3 1.9 1.15 1.15 0 0 1-1.8-.5l-.1-.3h-.2z" fill-rule="evenodd"/>
<path d="M28.9 76.6a1.4 1.4 0 0 1 2.2 .3 1.4 1.4 0 0 1-.9 2 1.4 1.4 0 0 1-1.7-1.3h.2a1.14 1.14 0 0 1 1.6-1.1 1.14 1.14 0 0 1 .3 1.9 1.14 1.14 0 0 1-1.8-.5l-.1-.3h-.2z" fill-rule="evenodd"/>
<path d="M54.3 76.6a1.4 1.4 0 0 1 2.2 .3 1.4 1.4 0 0 1-.9 2 1.4 1.4 0 0 1-1.7-1.3h.2a1.14 1.14 0 0 1 1.7-1 1.14 1.14 0 0 1 .1 2 1.14 1.14 0 0 1-1.8-.7v-.3h-.2z" fill-rule="evenodd"/>
<path d="M79.6 76.6a1.4 1.4 0 0 1 2.3 .3 1.4 1.4 0 0 1-.9 2 1.4 1.4 0 0 1-1.8-1.3h.3a1.15 1.15 0 0 1 1.6-1.1 1.15 1.15 0 0 1 .3 1.9 1.15 1.15 0 0 1-1.9-.5v-.3h-.3z" fill-rule="evenodd"/>
<path d="M105 76.6a1.4 1.4 0 0 1 2.3 .3 1.4 1.4 0 0 1-.9 2 1.4 1.4 0 0 1-1.8-1.3h.3a1.15 1.15 0 0 1 1.6-1.1 1.15 1.15 0 0 1 .3 1.9 1.15 1.15 0 0 1-1.9-.5v-.3h-.3z" fill-rule="evenodd"/>
<path d="M133 76.6a1.4 1.4 0 0 1 2.2 .3 1.4 1.4 0 0 1-.8 2 1.4 1.4 0 0 1-1.8-1.3h.2a1.15 1.15 0 0 1 1.7-1.1 1.15 1.15 0 0 1 .2 1.9 1.15 1.15 0 0 1-1.8-.5l-.1-.3h-.2z" fill-rule="evenodd"/>
<path d="M160.9 76.6a1.4 1.4 0 0 1 2.2 .3 1.4 1.4 0 0 1-.8 2 1.4 1.4 0 0 1-1.8-1.3h.3a1.14 1.14 0 0 1 1.6-1.1 1.14 1.14 0 0 1 .3 1.9 1.14 1.14 0 0 1-1.9-.5v-.3h-.3z" fill-rule="evenodd"/>
<path d="M143.1 132.5a1.39 1.39 0 0 1 2.2 .2 1.39 1.39 0 0 1-.8 2.1 1.39 1.39 0 0 1-1.8-1.3h.3a1.15 1.15 0 0 1 1.6-1.1 1.15 1.15 0 0 1 .3 1.9 1.15 1.15 0 0 1-1.9-.6v-.2h-.3z" fill-rule="evenodd"/>
<path d="M36.5 109.6a1.39 1.39 0 0 1 2.2 .3 1.39 1.39 0 0 1-.8 2 1.39 1.39 0 0 1-1.8-1.3h.2a1.14 1.14 0 0 1 1.6-1.1 1.14 1.14 0 0 1 .3 1.9 1.14 1.14 0 0 1-1.8-.5l-.1-.3h-.2z" fill-rule="evenodd"/>
<path d="M36.5 140.1a1.4 1.4 0 0 1 2.2 .2 1.4 1.4 0 0 1-.8 2.1 1.4 1.4 0 0 1-1.8-1.3h.2a1.14 1.14 0 0 1 1.6-1.1 1.14 1.14 0 0 1 .3 1.9 1.14 1.14 0 0 1-1.8-.5l-.1-.3h-.2z" fill-rule="evenodd"/>
<path d="M69.5 109.6a1.4 1.4 0 0 1 2.2 .2 1.4 1.4 0 0 1-.8 2.1 1.4 1.4 0 0 1-1.8-1.3h.3a1.14 1.14 0 0 1 1.6-1 1.14 1.14 0 0 1 .2 2 1.14 1.14 0 0 1-1.8-.7v-.3h-.3z" fill-rule="evenodd"/>
<path d="M69.5 140.1a1.4 1.4 0 0 1 2.2 .2 1.4 1.4 0 0 1-.8 2.1 1.4 1.4 0 0 1-1.8-1.3h.3a1.14 1.14 0 0 1 1.6-1 1.14 1.14 0 0 1 .2 1.9 1.14 1.14 0 0 1-1.8-.6v-.3h-.3z" fill-rule="evenodd"/>
<path d="M102.5 109.6a1.4 1.4 0 0 1 2.2 .3 1.4 1.4 0 0 1-.8 2.1 1.4 1.4 0 0 1-1.8-1.4h.3a1.15 1.15 0 0 1 1.6-1.1 1.15 1.15 0 0 1 .3 1.9 1.15 1.15 0 0 1-1.9-.5v-.3h-.3z" fill-rule="evenodd"/>
<path d="M102.5 140.1a1.4 1.4 0 0 1 2.2 .2 1.4 1.4 0 0 1-.8 2.1 1.4 1.4 0 0 1-1.8-1.3h.3a1.15 1.15 0 0 1 1.6-1.1 1.15 1.15 0 0 1 .3 1.9 1.15 1.15 0 0 1-1.9-.5v-.3h-.3z" fill-rule="evenodd"/>
</g>
<g fill="none" stroke="#c90d0c" stroke-width=".25">
<path d="M67.2 36.4h2.5l-1.2 2.6zM67.2 39h2.5M79.9 39h2.5M79.9 36.4h2.5l-1.2 2.6zM79.9 30.7l1.3-1.9 1.2 1.9M92.6 39h2.5M92.6 36.4h2.5l-1.2 2.6zM130.7 30.6l1.3 1.3h-2.6zM140.8 30.6l1.3 1.3h-2.5zM148.5 30.6l1.2 1.3h-2.5zM161.2 30.6l1.2 1.3h-2.5zM166.2 30.6l1.3 1.3h-2.5z"/>
<path d="M198.7 35.7v2.5l-1.2-1.2zM204.5 34.5a4 4 0 0 1 0 4.9M206.4 34.4v5.1M207.6 31.2l1.3-1.9 1.3 1.9M214 29.3h5.1M214 27.5l.9 .5 1.6 .3M216.5 20.4l1.3 1.3h-2.6zM219 27.5l-.9 .5-1.6 .3M253.3 31.9h2.6M254.6 31.9l1.3 2.5h-2.6zM257.2 28.4h5v1.8h-5zM267.3 28.1l1.3 1.2-1.3 1.3z"/>
<path d="M28.6 49.7h1.3M29.9 49.7l2.5-1.3v2.5zM30.5 48.4h-.6v2.5M32.4 52.2h2.5l-1.2 1.3zM32.4 49.7h1.3M52.7 52.2h2.6l-1.3 1.3zM67.2 54.2h2.5l-1.2 1.3zM67.6 44.1h1.8v5h-1.8zM79.9 54.2h2.5l-1.2 1.3zM80.3 44.1h1.7v5h-1.7zM92.6 54.2h2.5l-1.2 1.3zM93 44.1h1.7v5h-1.7z"/>
<path d="M125 48.4l-1.9 1.3 1.9 1.2M134.5 52.2h2.5l-1.2 1.3zM144.7 55.4l1.2 1.9 1.3-1.9M154.8 52.2h2.6l-1.3 1.3zM176.4 48.4l1.3 1.3-1.3 1.2zM188.6 44.6h5.1M188.6 54.7h5.1M188.7 46.4a4 4 0 0 1 4.9 0M191.1 55.7l1.6 .3 .9 .6M191.1 55.8l-1 .1-1.4 .7M211.4 58.5v2.6M211.4 59.8l2.6-1.3v2.6z"/>
<path d="M262.2 50.9v2.6l-1.2-1.3zM38.8 75h5v20.4h-5zM64.2 75h5v20.4h-5zM89.5 75h5.1v20.4h-5.1zM114.9 75h5.1v20.4h-5.1zM142.9 75h5.1v20.4h-5.1zM170.8 75h5.1v20.4h-5.1zM188.6 73.8v2.5l-1.3-1.3zM193.7 72.5v5.1M195.5 72.6a4 4 0 0 0 0 4.9M196.2 61.1v2.5l-1.3-1.2zM201.3 61.5h5.1v1.7h-5.1z"/>
<path d="M31.1 91.5v2.6l-1.2-1.3zM56.5 91.5v2.6l-1.2-1.3zM81.9 91.5v2.6l-1.3-1.3zM107.3 91.5v2.6l-1.3-1.3zM135.3 91.5v2.6l-1.3-1.3zM163.2 91.5v2.6l-1.3-1.3zM264.8 99.2l1.2 1.2h-2.5zM29.9 110.6h2.5M30.2 118.2h1.8v5.1h-1.8zM31.1 110.6l1.3 2.5h-2.5zM31.1 104.2l1.3 1.3h-2.5zM33.7 114.8h5.1v1.8h-5.1z"/>
<path d="M46.4 108.1h5.1v15.2h-5.1zM62.9 110.6h2.5M63.3 118.2h1.7v5.1h-1.7zM64.2 110.6l1.2 2.5h-2.5zM64.2 104.2l1.2 1.3h-2.5zM66.7 114.8h5.1v1.8h-5.1zM79.4 108.1h5.1v15.2h-5.1zM95.9 110.6h2.5M96.3 118.2h1.7v5.1h-1.7zM97.2 110.6l1.2 2.5h-2.5zM97.2 104.2l1.2 1.3h-2.5zM99.7 114.8h5.1v1.8h-5.1z"/>
<path d="M112.4 108.1h5.1v15.2h-5.1zM135.3 116.9l1.2 1.3h-2.5zM165.1 104.2l-1.9 1.3 1.9 1.3M170.8 103h5.1v25.4h-5.1zM184.8 115l1.3-1.9 1.2 1.9M202.5 110.6l1.3-1.3 1.3 1.3zM202.9 115.7h1.8v5.1h-1.8zM210.5 113.1h1.8v5.1h-1.8zM211.4 106.8l1.3 1.3h-2.5zM218.2 110.6h1.7v5.1h-1.7zM219.1 104.2l1.2 1.3h-2.5zM262.2 108.1h5.1"/>
<path d="M262.3 106.2l.9 .5 1.6 .4M267.2 106.2l-.9 .5-1.5 .3M267.9 111.9l2 1.2-2 1.3M29.9 128.4h2.5l-1.3 1.2zM31.1 134.7l1.3 1.3h-2.5zM46.4 138.5h5.1v15.3h-5.1zM62.9 128.4h2.5l-1.2 1.2zM62.9 136l1.3-1.3 1.2 1.3zM79.4 138.5h5.1v15.3h-5.1zM95.9 128.4h2.5l-1.2 1.2zM97.2 134.7l1.2 1.3h-2.5zM112.4 138.5h5.1v15.3h-5.1z"/>
<path d="M134 130.9h2.5M134.4 123.3h1.7v5.1h-1.7zM135.3 130.9l1.2 2.6h-2.5zM153 130.9h5.1v15.3h-5.1zM163.2 124.6v2.5l-1.3-1.3zM198.1 132.2l-1.9 1.3 1.9 1.2M206.4 124.9h5v1.8h-5zM206.4 130h5v1.8h-5zM206.4 132.6h5v1.7h-5zM29.9 158.8h2.5l-1.3 1.3zM29.9 141.1h2.5M30.2 148.7h1.8v5.1h-1.8z"/>
<path d="M31.1 141.1l1.3 2.5h-2.5zM33.7 145.3h5.1v1.7h-5.1zM62.9 158.8h2.5l-1.2 1.3zM62.9 141.1h2.5M63.3 148.7h1.7v5.1h-1.7zM64.2 141.1l1.2 2.5h-2.5zM66.7 145.3h5.1v1.7h-5.1zM95.9 158.8h2.5l-1.2 1.3zM95.9 141.1h2.5M96.3 148.7h1.7v5.1h-1.7zM97.2 141.1l1.2 2.5h-2.5zM99.7 145.3h5.1v1.7h-5.1z"/>
<path d="M144.1 143.6l1.3-1.3v2.6zM150.5 155l1.3 1.3h-2.6zM267.3 157.6l1.3 1.2-1.3 1.3zM33 167.7l-1.9 1.3 1.9 1.3M38.8 166.5h5v20.3h-5zM83.8 167.7l-1.9 1.3 1.9 1.3M89.5 166.5h5.1v20.3h-5.1zM104.8 167.7v2.6l-1.3-1.3zM109.9 168.1h5v1.8h-5zM116.2 171.5h2.5M117.5 171.5l1.2 2.6h-2.5zM127 170.3l-1.9 1.2 1.9 1.3"/>
<path d="M132.7 169h5.1v15.2h-5.1zM149.2 171.5h2.6M149.6 161.4h1.8v5.1h-1.8zM150.5 171.5l1.3 2.6h-2.6zM162.6 170.3l-1.9 1.2 1.9 1.3M168.3 169h5.1v15.2h-5.1zM31.1 183v2.5l-1.2-1.3zM81.9 183v2.5l-1.3-1.3zM123.8 181.7l1.3-1.3v2.6zM160.7 180.4v2.6l-1.3-1.3z"/>
</g>
<path d="M123.1 38.2h53.3v7.6h-53.3zM221.6 31.9h25.4v53.3h-25.4zM188.6 115.7h10.1v10.1h-10.1zM224.1 110.6h35.6v50.8h-35.6z" fill="none" stroke="#c90d0c" stroke-width=".42"/>
<path d="M18.4 12.8h260.3v179.1h-260.3z" fill="none" stroke="#c90d0c" stroke-width=".32"/>
<g fill="none" stroke="#0dab76" stroke-width=".21">
<path d="M28.5 38.7v-1.5l.1 1.9M28.5 39.7v1.6M32.6 37.1l-.1 4.1h1.2v8.5M48.8 36.9l.1 12.8M52.9 36.8v4.2M81.2 31.4v2.5M125.6 34.4h2.5M133.2 26.8v7.6M135.8 26.8v7.6M138.3 26.8v7.6M143.4 26.8v7.6M145.9 26.8v7.6"/>
<path d="M151 26.8v7.6M153.5 26.8v7.6M156.1 26.8v7.6M158.6 26.8v7.6M163.7 26.8v7.6M168.8 26.8v7.6M171.3 26.8v7.6M173.9 26.8v7.6M208.9 31.9v5.1h2.5v5h5.1M216.5 31.9v5.1M252.1 39.5h5.1M254.6 37v2.5"/>
<path d="M28.6 40.1v9.6M52.8 41h1.2v8.7M128.1 49.7v7.6M130.7 49.7v7.6M133.2 49.7v7.6M138.3 49.7v7.6M140.8 49.7v7.6M143.4 49.7v7.6M145.9 49.7v5M148.5 49.7v7.6M151 49.7v7.6M153.5 49.7v7.6"/>
<path d="M158.6 49.7v7.6M161.2 49.7v7.6M163.7 49.7v7.6M166.2 49.7v7.6M168.8 49.7v7.6M171.3 49.7v7.6M191.1 42h7.6v5.1h17.8M191.1 49.7h25.4M191.1 52.2h25.4M208.9 59.8v2.6M216.5 57.3v2.5M216.5 54.7h-17.8v5.1h-7.6"/>
<path d="M252.1 47.1h12.7M262.2 44.6h2.6M191.1 75v5.1h25.4M198.7 75h17.8M214 70h2.5M31.1 82.7h2.6M31.1 87.7h2.6M56.5 82.7h2.6M56.5 87.7h2.6M81.9 82.7h2.6M81.9 87.7h2.6M107.3 82.7h2.6"/>
<path d="M107.3 87.7h2.6M135.3 82.7h2.5M135.3 87.7h2.5M163.2 82.7h2.5M163.2 87.7h2.5M163.2 110.6h2.5M163.2 115.7h2.5M186.1 115.7v7.6M201.3 118.2h17.8M264.8 110.6v2.5h2.5M264.8 118.2h2.5M41.3 120.8v5h-10.2"/>
<path d="M74.3 120.8v5h-10.1M107.3 120.8v5h-10.1M132.7 138.5h15.3M135.3 128.4v2.5M135.3 136v2.5M163.2 120.8h2.5M201.3 123.3h17.8M201.3 120.8h17.8M203.8 125.8v7.7h-5.1M214 133.5h5.1M214 125.8h5.1M214 130.9h5.1"/>
<path d="M216.5 128.4v2.5M216.5 133.5v2.5M264.8 133.5h2.5M264.8 125.8h2.5M264.8 120.8h2.5M264.8 128.4h2.5M264.8 136h2.5M41.3 151.2v5.1h-10.2M74.3 151.2v5.1h-10.1M107.3 151.2v5.1h-10.1M31.1 174.1h2.6M31.1 179.2h2.6"/>
<path d="M81.9 174.1h2.6M81.9 179.2h2.6M117.5 176.6h10.1M150.5 176.6h12.7"/>
</g>
<g fill="#0dab76" stroke="#0dab76" stroke-width=".21">
<circle cx="208.9" cy="37" r=".51"/>
<circle cx="264.8" cy="113.1" r=".51"/>
<circle cx="203.8" cy="133.5" r=".51"/>
<circle cx="203.8" cy="130.9" r=".51"/>
<circle cx="186.1" cy="120.8" r=".51"/>
<circle cx="186.1" cy="118.2" r=".51"/>
<circle cx="125.6" cy="34.4" r=".51"/>
<circle cx="28.6" cy="49.7" r=".51"/>
<circle cx="28.5" cy="37.2" r=".51"/>
<circle cx="191.1" cy="75" r=".51"/>
<circle cx="33.7" cy="49.7" r=".51"/>
<circle cx="32.5" cy="41.2" r=".51"/>
<circle cx="52.8" cy="41" r=".51"/>
<circle cx="31.1" cy="125.8" r=".51"/>
<circle cx="31.1" cy="156.3" r=".51"/>
<circle cx="64.2" cy="125.8" r=".51"/>
<circle cx="64.2" cy="156.3" r=".51"/>
<circle cx="97.2" cy="125.8" r=".51"/>
<circle cx="97.2" cy="156.3" r=".51"/>
<circle cx="150.5" cy="176.6" r=".51"/>
<circle cx="97.2" cy="115.7" r=".51"/>
<circle cx="216.5" cy="59.8" r=".51"/>
<circle cx="254.6" cy="39.5" r=".51"/>
<circle cx="31.1" cy="115.7" r=".51"/>
<circle cx="216.5" cy="133.5" r=".51"/>
<circle cx="216.5" cy="130.9" r=".51"/>
<circle cx="64.2" cy="115.7" r=".51"/>
<circle cx="48.8" cy="41" r=".51"/>
<circle cx="31.1" cy="146.2" r=".51"/>
<circle cx="64.2" cy="146.2" r=".51"/>
<circle cx="97.2" cy="146.2" r=".51"/>
<circle cx="203.8" cy="123.3" r=".51"/>
<circle cx="211.4" cy="120.8" r=".51"/>
<circle cx="219.1" cy="118.2" r=".51"/>
<circle cx="135.3" cy="138.5" r=".51"/>
</g>
<use href="#words"/>
</svg>
